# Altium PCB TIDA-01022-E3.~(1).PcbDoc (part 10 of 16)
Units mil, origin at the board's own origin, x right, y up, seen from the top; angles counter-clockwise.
Board outline 6929.13 x 11614.17 mil, 12 copper layers (L1_Top Layer, L2_GND, L3_GND, L4_Signal Layer 1, L5_GND, L6_PWR, L7_GND/PWR, L8_PWR, L9_GND/PWR, L10_Signal Layer 2, L11_GND, L12_Bottom Layer), stack 64.6 mil thick; 1733 components, 993 nets, 5987 pads, 3555 vias.

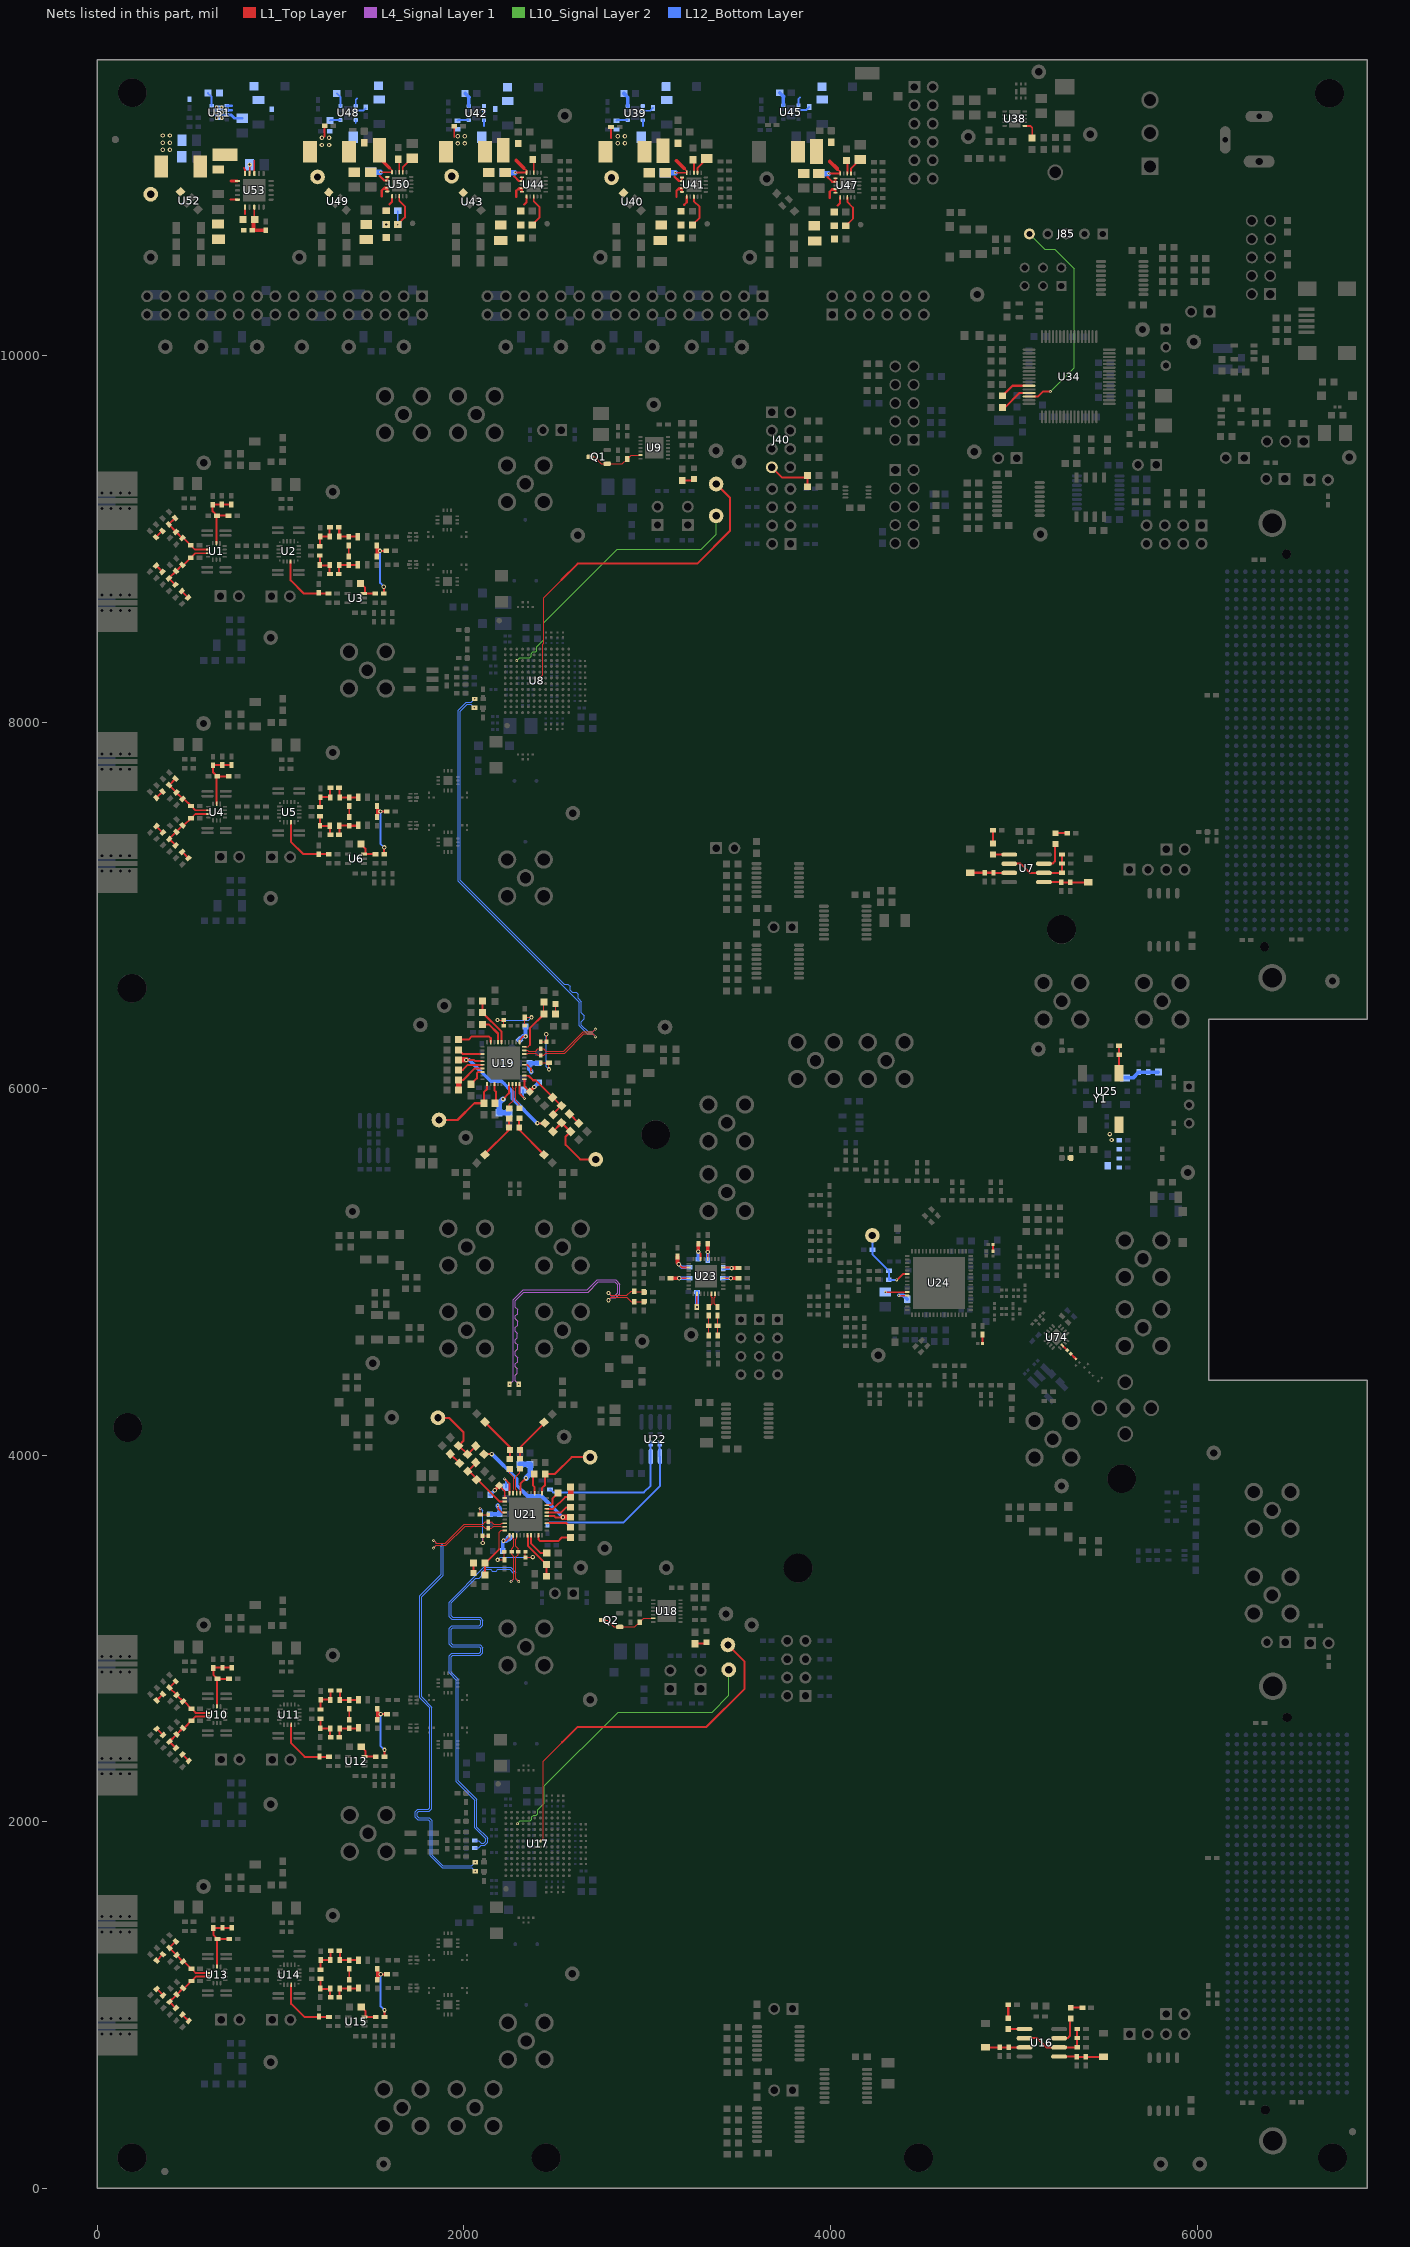
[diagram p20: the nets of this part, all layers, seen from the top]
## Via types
v1: diameter 16, hole 8, L1_Top Layer to L12_Bottom Layer, tented both sides, 1686 vias
v2: diameter 24, hole 12, L1_Top Layer to L12_Bottom Layer, tented both sides, 1590 vias
v3: diameter 20, hole 10, L1_Top Layer to L12_Bottom Layer, 279 vias

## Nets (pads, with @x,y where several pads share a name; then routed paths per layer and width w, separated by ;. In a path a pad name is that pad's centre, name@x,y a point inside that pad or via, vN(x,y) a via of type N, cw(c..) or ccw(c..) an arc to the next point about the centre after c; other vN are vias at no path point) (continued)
LMX2_CLKM: C253.2 R209.1 U21.22 | length 2893.9
  L1_Top Layer w6: v1(2256.84,3310.39) 2272.34,3325.89 2272.34,3446.04 2259.8,3458.58 R209.1@2259.8,3474.42 2259.8,3490.27 2272.2,3502.67 2272.2,3541.83 2267.86,3546.17 U21.22@2267.86,3563.98
  L12_Bottom Layer w6: C253.2@2058.74,1857.6 2080.49,1857.6 2094.99,1872.1 2112.65,1872.1 2125.78,1885.22 2129,1888.44 2129,1911.56 2125.78,1914.78 2069,1971.56 2069,2123.56 1969,2223.56 1969,2778 1930,2817 1930,2900.22 1938.28,2908.5 2088.28,2908.5 2103,2923.22 2103,2950.78 2088.28,2965.5 1938.28,2965.5 1930,2973.78 1930,3050.22 1938.28,3058.5 2088.28,3058.5 2103,3073.22 2103,3100.78 2088.28,3115.5 1938.28,3115.5 1930,3123.78 1930,3194 2019.93,3283.93 2053.16,3317.16 ; v1(2256.84,3310.39) 2272.34,3325.89 2272.34,3354.66 2250,3377 2184,3377 2175,3368 2154,3368 2145,3377 2113,3377 2097,3361 2097,3342 2083.47,3328.47 2064.47,3328.47 ; 2053.16,3317.16 2064.47,3328.47 ; 2053.16,3317.16 2064.47,3328.47
LMX2_CLKP: C252.2 R205.1 U21.23 | length 2877.7
  L1_Top Layer w6: U21.23@2287.55,3563.98 2287.55,3546.17 2283.2,3541.83 2283.2,3502.63 2295.89,3489.95 R205.1@2295.89,3474.1 2295.89,3458.26 2283.34,3445.72 2283.34,3325.89 v1(2298.84,3310.39)
  L12_Bottom Layer w6: C252.2@2058.74,1897.6 2080.49,1897.6 2094.99,1883.1 2108.1,1883.1 2118,1893 2118,1907 2058,1967 2058,2119 1958,2219 1958,2773.44 1919,2812.44 1919,2904.78 1933.72,2919.5 2083.72,2919.5 2092,2927.78 2092,2946.22 2083.72,2954.5 1933.72,2954.5 1919,2969.22 1919,3054.78 1933.72,3069.5 2083.72,3069.5 2092,3077.78 2092,3096.22 2083.72,3104.5 1933.72,3104.5 1919,3119.22 1919,3198.56 2108.44,3388 2254.56,3388 2283.34,3359.21 2283.34,3325.89 v1(2298.84,3310.39)
LMX2_CS: R454.1 U34.45 | length 180.5
  L1_Top Layer w11: R454.1@4935.38,9722.97 R454.1@4937.81,9722.97 ; R454.1@4937.81,9717 4951.96,9717 5030.35,9795.39 U34.45@5083.38,9795.39
LMX2_REFN: R244.1 R264.2 R265.1 R268.2 | length 1443.8
  L1_Top Layer w6: v2(2788.59,4845.83) 2803.54,4860.79 2888.31,4860.79 2911.19,4837.91 2929,4837.91 2929.5,4837.41 2930,4836.91 R265.1@2980,4836.91
  L4_Signal Layer 1 w4.9: v1(2248.66,4387.84) 2268.16,4407.34 2268.16,4848.13 2322.03,4902 2672.03,4902 2728.03,4958 2827,4958 2851,4934 2851,4881.61 2828.72,4859.33 2802.09,4859.33 v2(2788.59,4845.83)
LMX2_REFP: R226.2 R260.1 R262.2 R269.2 | length 1443.9
  L1_Top Layer w6: v2(2788.59,4884.83) 2801.63,4871.79 2888.31,4871.79 2911.19,4894.67 R269.2@2929,4894.67 2933,4890.67 R260.1@2981,4890.67
  L4_Signal Layer 1 w4.9: v1(2299.16,4387.35) 2280.16,4406.34 2280.16,4436 2291.16,4447 2291.16,4471 2280.16,4482 2280.16,4498 2292.16,4510 2292.16,4533 2280.16,4545 2280.16,4568 2292.16,4580 2292.16,4603 2280.16,4615 2280.16,4631 2291.16,4642 2291.16,4666 2280.16,4677 2280.16,4697 2292.16,4709 2292.16,4732 2280.16,4744 2280.16,4761 2292.16,4773 2292.16,4796 2280.16,4808 2280.16,4843.16 2327,4890 2677,4890 2733,4946 2822.03,4946 2839,4929.03 2839,4886.58 2823.75,4871.33 2802.09,4871.33 v2(2788.59,4884.83)
LMX2_SYNC: R219.2 R234.1 U22.7 | length 800.8
  L12_Bottom Layer w11: R219.2@2469.93,3813.45 2486.22,3797.16 2981.46,3797.16 3018.8,3834.5 U22.7@3018.8,3992.97 R234.1@3018.8,4064.21
LMX2_SYSREFREQ: R225.2 R239.2 U22.6 | length 934.1
  L12_Bottom Layer w11: R225.2@2455.3,3621.08 2467.49,3633.26 2870.96,3633.26 3068.8,3831.1 U22.6@3068.8,3992.97 3067.83,3993.94 R239.2@3067.83,4064.32
LMX_ADC1_SYSREF_M: C325.1 R180.1 U19.19 | length 2672
  L1_Top Layer w6: U19.19@2329.03,6208.71 2346.84,6208.71 2351.18,6204.37 2390.38,6204.37 2403.07,6217.06 R180.1@2418.91,6217.06 2434.75,6217.06 2447.3,6204.51 2545.3,6204.51 2650.1,6309.32 2701.66,6309.32 v1(2717.16,6324.82)
  L12_Bottom Layer w6: v1(2056.89,8077.19) 2037.89,8096.19 2017,8096.19 1979.97,8059.16 1979.97,7136.03 2545.93,6570.07 2567.14,6570.07 2579.16,6558.05 2579.16,6536.84 2590.47,6525.53 2611.69,6525.53 2623,6514.21 2623,6493 2641,6475 2641,6413 2656,6398 2656,6381 2641,6366 2641,6346.56 2678.24,6309.32 2701.66,6309.32 v1(2717.16,6324.82)
LMX_ADC1_SYSREF_P: C321.1 R175.2 U19.18 | length 2672.5
  L1_Top Layer w6: U19.18@2329.03,6189.03 2346.84,6189.03 2351.18,6193.37 2390.35,6193.37 2402.75,6180.97 R175.2@2418.59,6180.97 2434.43,6180.97 2443.76,6190.29 2446.98,6193.51 2549.85,6193.51 2654.66,6298.32 2701.66,6298.32 v1(2717.16,6282.82)
  L12_Bottom Layer w6: v1(2058.26,8126.19) 2039.26,8107.19 2012.44,8107.19 1968.97,8063.71 1968.97,7131.48 2630,6470.44 2630,6342 2673.68,6298.32 2701.66,6298.32 v1(2717.16,6282.82)
LMX_ADC2_SYSREF_M: C341.1 R221.1 U21.19 | length 2673.7
  L1_Top Layer w6: v1(1834.46,3493.16) 1849.96,3508.66 1901.51,3508.66 2006.32,3613.46 2104.32,3613.46 2116.86,3600.92 R221.1@2132.7,3600.92 2148.55,3600.92 2161.23,3613.6 2200.43,3613.6 2204.77,3609.26 U21.19@2222.59,3609.26
  L12_Bottom Layer w6: v1(1834.46,3493.16) 1849.96,3508.66 1868.34,3508.66 1875.67,3501.33 1875.67,3350.22 1758,3232.56 1758,2677.44 1814,2621.44 1814,2076.78 1805.72,2068.5 1748.72,2068.5 1734,2053.78 1734,2026.22 1748.72,2011.5 1805.72,2011.5 1814,2003.22 1814,1816.44 1819,1811.44 1880.25,1750.19 2042.59,1750.19 v1(2061.59,1731.19)
LMX_ADC2_SYSREF_P: C334.1 R216.2 U21.18 | length 2673.5
  L1_Top Layer w6: v1(1834.46,3535.16) 1849.96,3519.66 1896.96,3519.66 2001.76,3624.46 2104.64,3624.46 2107.86,3627.68 2117.18,3637.01 R216.2@2133.02,3637.01 2148.87,3637.01 2161.27,3624.6 2200.43,3624.6 2204.77,3628.95 U21.18@2222.59,3628.95
  L12_Bottom Layer w6: v1(1834.46,3535.16) 1849.96,3519.66 1872.9,3519.66 1886.67,3505.89 1886.67,3345.67 1769,3228 1769,2682 1825,2626 1825,2072.22 1810.28,2057.5 1753.28,2057.5 1745,2049.22 1745,2030.78 1753.28,2022.5 1810.28,2022.5 1825,2007.78 1825,1821 1884.81,1761.19 2042.59,1761.19 v1(2061.59,1780.19)
LMX_CS_1X: J85.5 U34.46 | length 1175.5
  L1_Top Layer w11: U34.46@5083.38,9775.7 5130.7,9775.7 5158,9803 v1(5199,9803)
  L10_Signal Layer 2 w6.5: J85.5@5085,10663 5168,10580 5224,10580 5330,10474 5330,9934 v1(5199,9803)
LMX_OSCIN1+: C348.2 U19.8 | length 144.6
  L1_Top Layer w6: C348.2@2246.86,5891.78 2246.86,5913.52 2268.41,5935.08 2268.41,6003.49 2264.07,6007.83 U19.8@2264.07,6025.64
LMX_OSCIN1-: C349.2 U19.9 | length 143.3
  L1_Top Layer w6: U19.9@2283.76,6025.64 2283.76,6007.83 2279.41,6003.49 2279.41,5937.85 2302.04,5915.22 C349.2@2302.04,5893.48
LMX_OSCIN2+: C378.2 U21.8 | length 144.6
  L1_Top Layer w6: U21.8@2287.55,3792.33 2287.55,3810.14 2283.2,3814.48 2283.2,3882.9 2304.76,3904.45 C378.2@2304.76,3926.2
LMX_OSCIN2-: C379.2 U21.9 | length 143.3
  L1_Top Layer w6: C379.2@2249.58,3924.5 2249.58,3902.75 2272.2,3880.13 2272.2,3814.48 2267.86,3810.14 U21.9@2267.86,3792.33
LMX_SDO: R449.1 U34.43 | length 168.3
  L1_Top Layer w11: R449.1@4937.81,9780 4992.57,9834.76 U34.43@5083.38,9834.76
LMX_SDO_MSEL: J40.7 R406.2 R408.2 | length 284.7
  L1_Top Layer w11: J40.7@3679.92,9390 3735.92,9334 3862.5,9334 R406.2@3874.5,9346 R408.2@3874.5,9284
MUXOUT1: R187.1 R190.2 U19.20 | length 300.5
  L1_Top Layer w6: U19.20@2329.03,6228.4 2349.5,6228.4 2359.81,6238.72 ; R187.1@2435.81,6472.22 2436.32,6471.72 R190.2@2436.32,6406.72
  L1_Top Layer w11: 2359.81,6238.72 2359.81,6330.21 R190.2@2436.32,6406.72
MUXOUT2: R227.1 R231.2 U21.20 | length 300.5
  L1_Top Layer w6: R227.1@2115.3,3346.26 R227.1@2115.8,3345.75 ; 2191.8,3487.76 2191.8,3579.26 2202.12,3589.58 U21.20@2222.59,3589.58
  L1_Top Layer w11: R227.1@2115.3,3346.26 R231.2@2115.3,3411.26 2191.8,3487.76
NetBG1_1: BG1.1 U8.C3 | length 1548.3
  L10_Signal Layer 2 w3.5: v1(2287.93,8335.33) 2304.6,8352 ; 2304.68,8352.08 2304.6,8352 ; 2434.67,8459.17 2434.67,8448 2397.92,8411.24 2397.92,8389.24 2391,8382.33 2376,8382.33 2366.92,8373.25 2366.92,8360.24 2358.67,8352 2304.6,8352
  L10_Signal Layer 2 w6.5: 2434.67,8459.17 2434.67,8542 2836,8943.33 3293.33,8943.33 3375.44,9025.44 BG1.1@3375.44,9124.69
NetBG2_1: BG2.1 U17.C3 | length 1659.3
  L10_Signal Layer 2 w3.5: v1(2291.26,1989.33) 2307.93,2006 ; 2308.01,2006.08 2307.93,2006 ; 2438,2113.17 2438,2102 2401.25,2065.25 2401.25,2043.25 2394.33,2036.33 2379.33,2036.33 2370.25,2027.25 2370.25,2014.25 2362,2006 2307.93,2006
  L10_Signal Layer 2 w6.5: 2438,2113.17 2438,2196 2840.75,2598.75 2850.8,2598.75 2851.05,2599 3353.77,2599 3444.77,2690 BG2.1@3444.77,2829.93
NetC1_1: C1.1 R1.1 R2.1 R3.2 R483.2 U1.2 | length 385.5
  L1_Top Layer w8: C1.1@648.91,9122.87 C1.1@652.03,9125.99
  L1_Top Layer w11: U1.2@648.91,8976.27 C1.1@648.91,9122.87 ; R2.1@715.29,9125.99 C1.1@652.03,9125.99 628.91,9149.11 R3.2@628.91,9185.99 630.29,9187.37 R483.2@678.91,9187.37 729.71,9187.37 R1.1@729.91,9187.16
NetC10_1: C10.1 C513.2 L1.1 R11.1 | length 157.9
  L1_Top Layer w11: R11.1@1213.24,8959 1213.24,9010.62 C10.1@1215,9012.38 L1.1@1266.33,9012.38 ; L1.1@1267.3,9011.41 1267.3,9060.92 C513.2@1269.38,9063
NetC11_1: C11.1 C513.1 L1.2 L2.1 | length 154.8
  L1_Top Layer w11: C513.1@1316.62,9063 1319.46,9060.16 L1.2@1319.46,9011.41 1371.01,9011.41 C11.1@1371.38,9011.05 1420.81,9011.05 L2.1@1421.18,9011.41
NetC11_2: C11.2 C16.2 | length 60.2
  L1_Top Layer w9: C16.2@1371.38,8903.65 C11.2@1371.38,8963.8
NetC12_1: C12.1 R7.1 R17.1 R22.2 | length 415.6
  L1_Top Layer w11: R17.1@1523.38,8903.65 R17.1@1523.38,8913.19 ; R7.1@1523.38,8949.76 R17.1@1523.38,8913.19 ; R7.1@1523.38,8963.8 1523.38,8952.62 1531,8945 ; v2@1539.14,8934 v2(1542,8934) ; R22.2@1562.71,8701.26 v2(1562.71,8738.45) ; C12.1@1576.38,8934 v2(1542,8934) ; R17.1@1523.38,8913.19 1531.34,8921.15 ; 1531,8945 v2(1542,8934) ; 1531,8945 1531,8921.49 1531.34,8921.15 ; 1531.34,8921.15 1543.09,8932.91 v2(1542,8934)
  L12_Bottom Layer w11: v2(1542,8934) 1542,8759.17 v2(1562.71,8738.45)
NetC13_2: C13.2 R20.2 | length 49.5
  L1_Top Layer w11: R20.2@319.21,9008.27 C13.2@354.21,9043.27
NetC14_2: C14.2 R21.2 | length 49.5
  L1_Top Layer w11: R21.2@320,8854 C14.2@355,8819
NetC15_1: C15.1 C514.2 L3.1 R15.1 | length 158.2
  L1_Top Layer w11: R15.1@1213.24,8909 1213.24,8854.87 1213,8854.62 1264.49,8854.62 L3.1@1266.3,8856.43 1266.3,8811.08 C514.2@1269.38,8808
NetC16_1: C16.1 C514.1 L3.2 L4.1 | length 153
  L1_Top Layer w11: C514.1@1316.62,8808 1318.46,8809.84 L3.2@1318.46,8856.43 C16.1@1371.38,8856.4 ; C16.1@1371.38,8856.4 1418.56,8856.4 L4.1@1421.18,8859.02
NetC26_2: C26.2 R22.1 U3.3 | length 129
  L1_Top Layer w11: C26.2@1435.59,8756.26 1460.19,8731.65 1460.19,8706.85 U3.3@1465.19,8701.85 ; U3.3@1453.38,8701.85 U3.3@1465.19,8701.85 ; R22.1@1515.47,8701.26 1514.88,8701.85 U3.3@1465.19,8701.85
NetC27_1: C27.1 R23.2 U2.7 | length 339.4
  L1_Top Layer w11: U2.7@1053.93,8876.14 1053.93,8773 1125.68,8701.26 R23.2@1260.47,8701.26
NetC35_1: C35.1 R25.1 R26.1 R27.2 R559.2 U4.2 | length 385.5
  L1_Top Layer w8: C35.1@650.71,7700.74 C35.1@653.83,7703.86
  L1_Top Layer w11: U4.2@650.71,7554.14 C35.1@650.71,7700.74 ; R26.1@717.09,7703.86 C35.1@653.83,7703.86 630.71,7726.98 R27.2@630.71,7763.86 632.09,7765.24 731.5,7765.24 R25.1@731.71,7765.04
NetC44_1: C44.1 C515.2 L5.1 R35.1 | length 157.9
  L1_Top Layer w11: R35.1@1215.04,7536.87 1215.04,7588.49 C44.1@1216.8,7590.25 L5.1@1268.13,7590.25 ; L5.1@1269.09,7589.29 1269.09,7638.79 C515.2@1271.18,7640.87
NetC45_1: C45.1 C515.1 L5.2 L6.1 | length 154.8
  L1_Top Layer w11: C515.1@1318.42,7640.87 1321.26,7638.03 L5.2@1321.26,7589.29 1372.81,7589.29 C45.1@1373.18,7588.92 1422.61,7588.92 L6.1@1422.98,7589.29
NetC45_2: C45.2 C50.2 | length 60.2
  L1_Top Layer w9: C50.2@1373.18,7481.52 C45.2@1373.18,7541.68
NetC46_1: C46.1 R31.1 R41.1 R46.2 | length 415.6
  L1_Top Layer w11: R41.1@1525.18,7481.52 R41.1@1525.18,7491.07 ; R31.1@1525.18,7527.63 R41.1@1525.18,7491.07 ; R31.1@1525.18,7541.68 1525.18,7530.49 1532.8,7522.87 ; v2@1540.94,7511.87 v2(1543.8,7511.87) ; R46.2@1564.51,7279.13 v2(1564.51,7316.32) ; C46.1@1578.18,7511.87 v2(1543.8,7511.87) ; R41.1@1525.18,7491.07 1533.13,7499.02 ; 1532.8,7522.87 v2(1543.8,7511.87) ; 1532.8,7522.87 1532.8,7499.36 1533.13,7499.02 ; 1533.13,7499.02 1544.89,7510.78 v2(1543.8,7511.87)
  L12_Bottom Layer w11: v2(1543.8,7511.87) 1543.8,7337.04 v2(1564.51,7316.32)
NetC47_2: C47.2 R44.2 | length 49.5
  L1_Top Layer w11: R44.2@321.01,7586.14 C47.2@356.01,7621.14
NetC48_2: C48.2 R45.2 | length 49.5
  L1_Top Layer w11: R45.2@321.8,7431.87 C48.2@356.8,7396.87
NetC49_1: C49.1 C520.2 L7.1 R39.1 | length 158.2
  L1_Top Layer w11: R39.1@1215.04,7486.87 1215.04,7432.74 1214.8,7432.49 1266.28,7432.49 L7.1@1268.09,7434.3 1268.09,7388.96 C520.2@1271.18,7385.87
NetC50_1: C50.1 C520.1 L7.2 L8.1 | length 153
  L1_Top Layer w11: C520.1@1318.42,7385.87 1320.26,7387.71 L7.2@1320.26,7434.3 C50.1@1373.18,7434.28 ; C50.1@1373.18,7434.28 1420.36,7434.28 L8.1@1422.98,7436.9
NetC60_2: C60.2 R46.1 U6.3 | length 129
  L1_Top Layer w11: C60.2@1437.39,7334.13 1461.99,7309.52 1461.99,7284.72 U6.3@1466.99,7279.72 ; U6.3@1455.18,7279.72 U6.3@1466.99,7279.72 ; R46.1@1517.27,7279.13 1516.68,7279.72 U6.3@1466.99,7279.72
NetC61_1: C61.1 R47.2 U5.7 | length 341.2
  L1_Top Layer w11: U5.7@1055.73,7454.01 1055.73,7347.87 1124.47,7279.13 C61.1@1208.47,7279.13 R47.2@1262.27,7279.13
NetC74_2: C74.2 D2.1 R51.2 U7.3 | length 211.9
  L1_Top Layer w11: D2.1@4763.11,7177.81 R51.2@4840.21,7177.81 C74.2@4889.21,7177.81 4889.83,7177.18 U7.3@4974.72,7177.18
NetC82_2: C82.2 R49.1 R60.2 U7.2 U7.6 | length 408
  L1_Top Layer w11: U7.2@4974.72,7227.18 5036.99,7227.18 5086.99,7177.18 U7.6@5163.7,7177.18 5261.59,7177.18 C82.2@5262.59,7178.18 R60.2@5262.59,7228.18 R49.1@5262.59,7277.18
NetC83_2: C83.2 D4.1 R62.2 U7.5 | length 243.1
  L1_Top Layer w11: U7.5@5163.7,7127.18 5257.83,7127.18 C83.2@5259.21,7125.81 R62.2@5308.21,7125.81 5406.12,7125.81 D4.1@5406.21,7125.72
NetC117_1: C117.1 Q1.1 Q1.3 U9.6 | length 311.5
  L1_Top Layer w6: Q1.3@2686.86,9446.65 2712.14,9446.65 2749.54,9409.25 Q1.1@2781.35,9409.25 2864.32,9409.25 C117.1@2890.1,9435.03 2911.29,9456.21 U9.6@2963.36,9456.21
NetC161_1: C161.1 R82.1 R83.1 R84.2 R568.2 U10.2 | length 385.5
  L1_Top Layer w8: C161.1@652.23,2776.51 C161.1@655.35,2779.63
  L1_Top Layer w11: U10.2@652.23,2629.9 C161.1@652.23,2776.51 ; R83.1@718.61,2779.63 C161.1@655.35,2779.63 632.23,2802.75 R84.2@632.23,2839.63 633.61,2841.01 733.02,2841.01 R82.1@733.23,2840.8
NetC170_1: C170.1 C521.2 L9.1 R92.1 | length 157.9
  L1_Top Layer w11: R92.1@1216.56,2612.64 1216.56,2664.26 C170.1@1218.32,2666.02 L9.1@1269.65,2666.02 ; L9.1@1270.61,2665.05 1270.61,2714.56 C521.2@1272.69,2716.64
NetC171_1: C171.1 C521.1 L9.2 L10.1 | length 154.8
  L1_Top Layer w11: C521.1@1319.94,2716.64 1322.78,2713.8 L9.2@1322.78,2665.05 1374.33,2665.05 C171.1@1374.69,2664.68 1424.13,2664.68 L10.1@1424.5,2665.05
NetC171_2: C171.2 C176.2 | length 60.2
  L1_Top Layer w9: C176.2@1374.69,2557.28 C171.2@1374.69,2617.44
NetC172_1: C172.1 R88.1 R98.1 R103.2 | length 415.6
  L1_Top Layer w11: R98.1@1526.69,2557.28 R98.1@1526.69,2566.83 ; R88.1@1526.69,2603.4 R98.1@1526.69,2566.83 ; R88.1@1526.69,2617.44 1526.69,2606.26 1534.32,2598.64 ; v2@1542.45,2587.64 v2(1545.32,2587.64) ; R103.2@1566.03,2354.9 v2(1566.03,2392.09) ; C172.1@1579.69,2587.64 v2(1545.32,2587.64) ; R98.1@1526.69,2566.83 1534.65,2574.79 ; 1534.32,2598.64 v2(1545.32,2587.64) ; 1534.32,2598.64 1534.32,2575.13 1534.65,2574.79 ; 1534.65,2574.79 1546.41,2586.55 v2(1545.32,2587.64)
  L12_Bottom Layer w11: v2(1545.32,2587.64) 1545.32,2412.8 v2(1566.03,2392.09)
NetC173_2: C173.2 R101.2 | length 49.5
  L1_Top Layer w11: R101.2@322.52,2661.9 C173.2@357.52,2696.9
NetC174_2: C174.2 R102.2 | length 49.5
  L1_Top Layer w11: R102.2@323.32,2507.64 C174.2@358.32,2472.64
NetC175_1: C175.1 C525.2 L11.1 R96.1 | length 158.2
  L1_Top Layer w11: R96.1@1216.56,2562.64 1216.56,2508.5 1216.32,2508.26 1267.8,2508.26 L11.1@1269.61,2510.07 1269.61,2464.72 C525.2@1272.69,2461.64
NetC176_1: C176.1 C525.1 L11.2 L12.1 | length 153
  L1_Top Layer w11: C525.1@1319.94,2461.64 1321.78,2463.48 L11.2@1321.78,2510.07 C176.1@1374.67,2510.07 ; C176.1@1374.69,2510.04 1421.88,2510.04 L12.1@1424.5,2512.66
NetC186_2: C186.2 R103.1 U12.3 | length 129
  L1_Top Layer w11: C186.2@1438.9,2409.9 1463.51,2385.29 1463.51,2360.49 U12.3@1468.51,2355.49 ; U12.3@1456.7,2355.49 U12.3@1468.51,2355.49 ; R103.1@1518.79,2354.9 1518.2,2355.49 U12.3@1468.51,2355.49
NetC187_1: C187.1 R104.2 U11.7 | length 338.2
  L1_Top Layer w11: U11.7@1057.25,2529.78 1057.25,2428.68 1131.04,2354.9 R104.2@1263.79,2354.9
NetC195_1: C195.1 R106.1 R107.1 R108.2 R577.2 U13.2 | length 385.5
  L1_Top Layer w8: C195.1@652.3,1357.17 C195.1@655.42,1360.29
  L1_Top Layer w11: U13.2@652.3,1210.57 C195.1@652.3,1357.17 ; R107.1@718.68,1360.29 C195.1@655.42,1360.29 632.3,1383.41 R108.2@632.3,1420.29 633.68,1421.67 733.1,1421.67 R106.1@733.3,1421.47
NetC204_1: C204.1 C526.2 L13.1 R116.1 | length 157.9
  L1_Top Layer w11: R116.1@1216.64,1193.3 1216.64,1244.92 C204.1@1218.39,1246.68 L13.1@1269.72,1246.68 ; L13.1@1270.69,1245.72 1270.69,1295.22 C526.2@1272.77,1297.3
NetC205_1: C205.1 C526.1 L13.2 L14.1 | length 154.8
  L1_Top Layer w11: C526.1@1320.01,1297.3 1322.85,1294.46 L13.2@1322.85,1245.72 1374.4,1245.72 C205.1@1374.77,1245.35 1424.21,1245.35 L14.1@1424.57,1245.72
NetC205_2: C205.2 C210.2 | length 60.2
  L1_Top Layer w9: C210.2@1374.77,1137.95 C205.2@1374.77,1198.1
NetC206_1: C206.1 R112.1 R122.1 R127.2 | length 415.6
  L1_Top Layer w11: R122.1@1526.77,1137.95 R122.1@1526.77,1147.5 ; R112.1@1526.77,1184.06 R122.1@1526.77,1147.5 ; R112.1@1526.77,1198.1 1526.77,1186.92 1534.39,1179.3 ; v2@1542.53,1168.3 v2(1545.39,1168.3) ; R127.2@1566.11,935.56 v2(1566.11,972.75) ; C206.1@1579.77,1168.3 v2(1545.39,1168.3) ; R122.1@1526.77,1147.5 1534.73,1155.45 ; 1534.39,1179.3 v2(1545.39,1168.3) ; 1534.39,1179.3 1534.39,1155.79 1534.73,1155.45 ; 1534.73,1155.45 1546.48,1167.21 v2(1545.39,1168.3)
  L12_Bottom Layer w11: v2(1545.39,1168.3) 1545.39,993.47 v2(1566.11,972.75)
NetC207_2: C207.2 R125.2 | length 49.5
  L1_Top Layer w11: R125.2@322.6,1242.57 C207.2@357.6,1277.57
NetC208_2: C208.2 R126.2 | length 49.5
  L1_Top Layer w11: R126.2@323.39,1088.3 C208.2@358.39,1053.3
NetC209_1: C209.1 C527.2 L15.1 R120.1 | length 158.2
  L1_Top Layer w11: R120.1@1216.64,1143.3 1216.64,1089.17 1216.39,1088.92 1267.88,1088.92 L15.1@1269.69,1090.73 1269.69,1045.39 C527.2@1272.77,1042.3
NetC210_1: C210.1 C527.1 L15.2 L16.1 | length 153
  L1_Top Layer w11: C527.1@1320.01,1042.3 1321.85,1044.14 L15.2@1321.85,1090.73 C210.1@1374.77,1090.7 ; C210.1@1374.77,1090.7 1421.95,1090.7 L16.1@1424.57,1093.33
NetC220_2: C220.2 R127.1 U15.3 | length 129
  L1_Top Layer w11: C220.2@1438.98,990.56 1463.59,965.95 1463.59,941.15 U15.3@1468.59,936.15 ; U15.3@1456.78,936.15 U15.3@1468.59,936.15 ; R127.1@1518.86,935.56 1518.27,936.15 U15.3@1468.59,936.15
NetC221_1: C221.1 R128.2 U14.7 | length 339.4
  L1_Top Layer w11: U14.7@1057.33,1110.44 1057.33,1007.35 1129.11,935.56 R128.2@1263.86,935.56
NetC234_2: C234.2 D7.1 R132.2 U16.3 | length 213.2
  L1_Top Layer w11: D7.1@4845.28,770.78 4846.19,769.87 R132.2@4923.3,769.87 C234.2@4972.3,769.87 4972.92,769.25 U16.3@5057.81,769.25
NetC242_2: C242.2 R130.1 R141.2 U16.2 U16.6 | length 408
  L1_Top Layer w11: U16.2@5057.81,819.25 5127.31,819.25 5177.31,769.25 U16.6@5246.78,769.25 5344.67,769.25 C242.2@5345.67,770.25 R130.1@5345.67,869.25
NetC243_2: C243.2 D9.1 R143.2 U16.5 | length 243.1
  L1_Top Layer w11: U16.5@5246.78,719.25 5340.92,719.25 C243.2@5342.3,717.87 R143.2@5391.3,717.87 5489.21,717.87 D9.1@5489.3,717.79
NetC277_1: C277.1 Q2.1 Q2.3 U18.6 | length 311.5
  L1_Top Layer w6: Q2.3@2755.19,3100.88 2780.47,3100.88 2817.87,3063.48 Q2.1@2849.68,3063.48 2932.65,3063.48 C277.1@2958.43,3089.26 2979.62,3110.45 U18.6@3031.69,3110.45
NetC307_1: C307.1 R401.2 | length 40.5
  L1_Top Layer w11: C307.1@5310.19,4553.81 R401.2@5338.81,4525.19
NetC307_2: C307.2 U74.2 | length 38.2
  L1_Top Layer w11: U74.2@5264.65,4598.78 5291.24,4572.19 C307.2@5291.81,4572.19
NetC322_2: C322.2 L17.2 R164.2 R168.2 | length 339
  L1_Top Layer w6: v2(2182.77,6374.32) 2214.22,6374.32 2214.77,6373.77 L17.2@2216.07,6375.07 2216.36,6374.78 R164.2@2216.36,6343.87 ; R168.2@2331.19,6343.55 2331.07,6343.67 C322.2@2331.07,6388.15 2367.45,6388.15 v2(2368.07,6388.77)
  L12_Bottom Layer w6: v2(2182.77,6374.32) 2352.52,6374.32 2353.07,6373.77 v2(2368.07,6388.77)
NetC323_2: C323.2 R165.2 U19.7 | length 233.3
  L1_Top Layer w11: v2(2213.28,5942.92) 2244.39,5974.02 U19.7@2244.39,6025.64
  L12_Bottom Layer w30: C323.2@2191.16,5868.21 2191.16,5920.79 v2(2213.28,5942.92) ; C323.2@2191.25,5868.3 R165.2@2245.1,5868.3
NetC324_2: C324.2 R167.2 U19.11 | length 159.7
  L1_Top Layer w11: U19.11@2329.03,6051.23 2329.03,6013.34 C324.2@2365.07,5977.3
  L1_Top Layer w20: C324.2@2358.61,5983.87 v2(2383.73,6008.99)
  L12_Bottom Layer w20: v2(2383.73,6008.99) 2408.65,6033.92 R167.2@2408.72,6033.92
NetC326_1: C326.1 R170.2 U19.15 | length 169.1
  L1_Top Layer w9: U19.15@2329.03,6129.97 2345.56,6129.97 2365.25,6110.28 2365.25,6093.58 v1(2367.87,6090.96)
  L12_Bottom Layer w25: v1(2367.87,6090.96) 2367.87,6095.88 2357.12,6106.7 C326.1@2357.12,6138.82 2408.13,6138.82 R170.2@2408.8,6138.15
NetC327_2: C327.2 R169.2 U19.21 | length 146.8
  L1_Top Layer w10: U19.21@2303.44,6253.99 2303.44,6264.45 2323.8,6284.82 v2(2335.86,6284.82)
  L12_Bottom Layer w20: R169.2@2335.25,6338.72 2335.86,6338.11 v2(2335.86,6284.82)
  L12_Bottom Layer w25: C327.2@2302.55,6265.5 2321.86,6284.82 v2(2335.86,6284.82)
NetC332_2: C332.2 R171.1 U19.26 | length 266.7
  L1_Top Layer w11: R171.1@2101.43,6477.29 2100.78,6476.64 C332.2@2100.78,6414.92 2205.02,6310.68 U19.26@2205.02,6253.99
NetC333_2: C333.2 R173.1 U19.37 | length 211.9
  L1_Top Layer w11: C333.2@1970.15,6047.12 1995.57,6047.12 2058.74,6110.29 U19.37@2100.68,6110.29
  L1_Top Layer w30: R173.1@1970.15,5991.92 C333.2@1970.15,6047.12
NetC335_2: C335.2 R176.1 U19.35 | length 723.4
  L1_Top Layer w11: v2(2012.28,6156.42) 2053.52,6156.42 2060.28,6149.66 U19.35@2100.68,6149.66 ; v2@2401.02,5811.09 R176.1@2441.39,5811.09
  L1_Top Layer w30: C335.2@1970.15,6156.42 v2(2012.28,6156.42)
  L12_Bottom Layer w20: v2(2012.28,6156.42) 2029.11,6156.42 2145.52,6040.01 2205.72,6040.01 2264.21,5981.52 2264.21,5946.06 v2@2398.49,5811.78
  other v2: 2400.32,5811.78
NetC336_1: C336.1 R176.2 R177.2 Vtune_TP1.1 | length 391.6
  L1_Top Layer w11: R176.2@2485.93,5766.55 2531.93,5812.55 R177.2@2531.93,5813.45 2579.29,5766.09 C336.1@2581.39,5766.09 2554.28,5738.98 2554.28,5692.92 2633.38,5613.82 Vtune_TP1.1@2693.66,5613.82
NetC337_1: C337.1 C339.1 R177.1 U19.12 | length 327
  L1_Top Layer w8: U19.12@2329.03,6070.92 2351.7,6070.92 2354.66,6067.96
  L1_Top Layer w11: 2354.66,6067.96 2376.81,6045.81 2391.39,6045.81 C337.1@2524.28,5912.92 ; R177.1@2487.39,5862.09 C337.1@2531.39,5906.09
  L1_Top Layer w30: R177.1@2487.39,5857.99 R177.1@2487.39,5862.09
NetC337_2: C337.2 R179.1 | length 71.1
  L1_Top Layer w11: C337.2@2575.93,5861.55 R179.1@2626.01,5811.47
  L1_Top Layer w30: R179.1@2626.01,5811.19 R179.1@2626.01,5811.47
NetC338_2: C338.2 L18.2 R175.1 R180.2 | length 352
  L1_Top Layer w6: R175.1@2418.59,6141.6 2418.71,6141.72 C338.2@2463.19,6141.72 2463.19,6105.34 v2(2463.81,6104.72) ; R180.2@2418.91,6256.43 2449.82,6256.43 L18.2@2450.11,6256.72 2448.81,6258.02 v2(2448.81,6296.72)
  L12_Bottom Layer w6: v2(2448.81,6296.72) 2448.81,6119.72 v2(2463.81,6104.72)
NetC340_2: C340.2 U19.10 | length 138.8
  L1_Top Layer w11: U19.10@2303.44,6025.64 2303.44,5972.93 v1(2329.56,5946.82)
  L12_Bottom Layer w11: C340.2@2322,5992.83 2322,5954.37 v1(2329.56,5946.82)
NetC342_1: C342.1 U19.36 | length 142.1
  L1_Top Layer w11: C342.1@1970.15,6102.02 1993.38,6102.02 2021.34,6129.97 U19.36@2100.68,6129.97
NetC343_2: C343.2 U19.38 | length 105.8
  L1_Top Layer w11: C343.2@2038.16,6024.21 2069.86,6055.91 2069.86,6082.87 2077.59,6090.6 U19.38@2100.68,6090.6
NetC344_1: C344.1 U19.29 | length 208.8
  L1_Top Layer w11: C344.1@1970.15,6267.52 2024.82,6267.52 2042.83,6285.52 2130.44,6285.52 2130.55,6285.42 2135.78,6285.42 2145.96,6275.24 U19.29@2145.96,6253.99
NetC345_1: C345.1 U19.3 | length 116.7
  L1_Top Layer w11: C345.1@2165.65,5923.33 C345.1@2168.66,5920.31 2175.78,5927.43 2175.78,5981.75 2165.65,5991.88 U19.3@2165.64,6025.64
NetC346_2: C346.2 U19.27 | length 152.5
  L1_Top Layer w11: C346.2@2100.37,6350.82 2135.38,6350.82 2185.33,6300.87 U19.27@2185.33,6253.99
NetC347_2: C347.2 U19.33 | length 139.7
  L1_Top Layer w11: C347.2@1970.15,6211.12 1992.24,6189.03 U19.33@2100.68,6189.03
NetC348_1: C348.1 R192.2 R196.2 | length 252.3
  L1_Top Layer w11: R192.2@2111.13,5640.53 2111.91,5641.31 2246.86,5776.26 2246.86,5788.82 C348.1@2246.86,5836.66
NetC349_1: C349.1 R196.1 R199.1 | length 251.9
  L1_Top Layer w11: C349.1@2302.04,5838.36 2300.54,5836.86 2300.54,5775.26 R199.1@2433.59,5642.21
NetC352_2: C352.2 L19.2 R205.2 R209.2 | length 352
  L1_Top Layer w6: v2(2183.55,3429.2) 2184.17,3429.82 C352.2@2220.55,3429.82 2220.55,3474.3 R209.2@2220.43,3474.42 ; R205.2@2335.26,3474.1 2335.26,3443.19 L19.2@2335.55,3442.9 2336.85,3444.2 v2(2375.55,3444.2)
  L12_Bottom Layer w6: v2(2183.55,3429.2) 2198.55,3444.2 v2(2375.55,3444.2)
NetC353_2: C353.2 R206.2 U21.7 | length 233.3
  L1_Top Layer w11: U21.7@2307.23,3792.33 2307.23,3843.95 v2(2338.34,3875.06)
  L12_Bottom Layer w30: R206.2@2306.51,3949.67 C353.2@2360.37,3949.67 ; v2(2338.34,3875.06) 2360.46,3897.18 C353.2@2360.46,3949.76
NetC354_2: C354.2 R208.2 U21.11 | length 159.7
  L1_Top Layer w10: C354.2@2186.55,3840.67 2222.59,3804.63 U21.11@2222.59,3766.74
  L1_Top Layer w20: v2(2167.89,3808.98) C354.2@2193.01,3834.11
  L12_Bottom Layer w20: R208.2@2142.89,3784.06 2142.96,3784.06 v2(2167.89,3808.98)
NetC355_1: C355.1 C494.1 L87.1 U39.1 U39.2 | length 61.3
  L12_Bottom Layer w10: U39.2@2976,11335.45 3015.83,11335.45 C355.1@3031,11350.62
NetC356_1: C356.1 R211.2 U21.15 | length 167.3
  L1_Top Layer w9: v1(2184.09,3726.67) 2186.71,3724.04 2186.71,3707.35 2206.41,3687.65 U21.15@2222.93,3687.65
  L12_Bottom Layer w25: R211.2@2142.48,3677.57 C356.1@2193.49,3677.57 ; v1@2183.34,3723.16 v1@2183.74,3723.56 ; v1@2183.71,3722.06 2194.5,3711.27 C356.1@2194.5,3679.16 ; v1@2183.74,3722.09 v1@2183.74,3723.56 ; v1@2183.74,3725.59 v1@2183.74,3723.56
NetC357_2: C357.2 R210.2 U21.21 | length 145.9
  L1_Top Layer w10: v2(2215.76,3533.16) 2227.81,3533.16 2248.18,3553.52 U21.21@2248.18,3563.98
  L12_Bottom Layer w20: R210.2@2211.44,3477.61 v2@2211.44,3530.91
  L12_Bottom Layer w25: v2(2215.76,3533.16) 2229.76,3533.16 C357.2@2249.07,3552.47
NetC362_2: C362.2 R212.1 U21.26 | length 267.2
  L1_Top Layer w11: U21.26@2346.6,3563.98 2348.39,3562.19 2348.39,3505.51 C362.2@2450.84,3403.06 2450.9,3403 R212.1@2450.9,3339.98
NetC363_2: C363.2 R214.1 U21.37 | length 211.9
  L1_Top Layer w11: U21.37@2450.93,3707.69 2488.1,3707.69 2551.27,3770.86 C363.2@2581.46,3770.86
  L1_Top Layer w30: C363.2@2581.46,3770.86 R214.1@2581.46,3826.06
NetC364_1: C364.1 C537.1 L88.1 U42.1 U42.2
NetC365_2: C365.2 R218.1 U21.35 | length 723.4
  L1_Top Layer w11: R218.1@2110.23,4006.89 v2@2150.6,4006.89 ; U21.35@2450.93,3668.32 2491.34,3668.32 2498.09,3661.56 v2(2539.34,3661.56)
  L1_Top Layer w30: v2(2539.34,3661.56) C365.2@2581.46,3661.56
  L12_Bottom Layer w20: v2@2153.13,4006.19 2287.41,3871.91 2287.41,3836.45 2345.89,3777.97 2422.92,3777.97 v2(2539.34,3661.56)
  other v2: 2151.29,4006.19
NetC366_1: C366.1 R217.2 R218.2 Vtune_TP2.1 | length 391.6
  L1_Top Layer w11: Vtune_TP2.1@1857.96,4204.16 1918.24,4204.16 1997.34,4125.06 1997.34,4078.99 C366.1@1970.23,4051.89 1972.33,4051.89 2019.69,4004.53 R217.2@2019.69,4005.43 R218.2@2064.32,4050.07 R218.2@2065.69,4051.43
NetC367_1: C367.1 C369.1 R217.1 U21.12 | length 327
  L1_Top Layer w10: 2194.8,3747.06 U21.12@2222.59,3747.06
  L1_Top Layer w11: C367.1@2020.23,3911.89 R217.1@2064.23,3955.89 ; C367.1@2027.34,3905.06 2036.8,3905.06 2194.8,3747.06
  L1_Top Layer w30: R217.1@2064.23,3955.89 R217.1@2064.23,3959.99
NetC367_2: C367.2 R220.1 | length 71.1
  L1_Top Layer w11: R220.1@1925.61,4006.51 C367.2@1975.69,3956.43
  L1_Top Layer w30: R220.1@1925.61,4006.51 R220.1@1925.61,4006.79
NetC368_2: C368.2 L20.2 R216.1 R221.2 | length 352.4
  L1_Top Layer w6: v1(2088,3710) 2088,3712.21 2088.43,3712.64 C368.2@2088.43,3676.26 2132.91,3676.26 R216.1@2133.02,3676.38 ; v2(2102.8,3521.26) 2102.8,3559.96 2101.5,3561.26 L20.2@2101.79,3561.55 R221.2@2132.7,3561.55
  L12_Bottom Layer w6: v1(2088,3710) 2091.06,3710 2102.8,3698.26 v2(2102.8,3521.26)
NetC370_2: C370.2 U21.10 | length 138.8
  L1_Top Layer w10: v1(2222.06,3871.16) 2248.18,3845.04 U21.10@2248.18,3792.33
  L12_Bottom Layer w11: v1(2222.06,3871.16) 2229.61,3863.6 C370.2@2229.61,3825.15
NetC371_1: C371.1 C600.1 L89.1 U45.1 U45.2 | length 109.7
  L12_Bottom Layer w10: U45.1@3825.01,11365.18 3825.01,11399.26 3832.75,11407
  L12_Bottom Layer w12: U45.2@3825.01,11339.59 3866.96,11339.59 C371.1@3883,11355.62
NetC372_1: C372.1 U21.36 | length 142.1
  L1_Top Layer w11: U21.36@2450.93,3688 2530.28,3688 2558.24,3715.96 C372.1@2581.46,3715.96
NetC373_2: C373.2 U21.38 | length 105.8
  L1_Top Layer w11: U21.38@2450.93,3727.37 2474.03,3727.37 2481.76,3735.1 2481.76,3762.06 C373.2@2513.46,3793.76
NetC374_1: C374.1 U21.29 | length 209.5
  L1_Top Layer w11: U21.29@2405.66,3563.98 2405.66,3542.74 2416.86,3531.53 2513.13,3531.53 2532.06,3550.46 C374.1@2581.46,3550.46
NetC375_1: C375.1 U21.3 | length 116.7
  L1_Top Layer w11: U21.3@2385.97,3792.33 2385.97,3826.09 2375.84,3836.22 2375.84,3890.54 C375.1@2382.96,3897.66 C375.1@2385.97,3894.65
NetC376_2: C376.2 U21.27 | length 152.5
  L1_Top Layer w11: U21.27@2366.29,3563.98 2366.29,3517.11 2416.24,3467.16 C376.2@2451.25,3467.16
NetC377_2: C377.2 U21.33 | length 139.7
  L1_Top Layer w11: U21.33@2450.93,3628.95 2559.37,3628.95 C377.2@2581.46,3606.86
NetC378_1: C378.1 R233.2 R237.2 | length 252.3
  L1_Top Layer w11: C378.1@2304.76,3981.32 2304.76,4041.72 R233.2@2440.49,4177.45
NetC379_1: C379.1 R237.1 R242.1 | length 251.9
  L1_Top Layer w11: R242.1@2118.03,4175.77 2251.08,4042.72 2251.08,4029.16 2251.08,3981.12 C379.1@2249.58,3979.62
NetC384_1: C384.1 R245.1 U23.2 | length 171.9
  L1_Top Layer w10: v2(3172,5042) 3189.01,5024.99 U23.2@3225.8,5024.99
  L1_Top Layer w20: R245.1@3164.5,5084.17 3164.5,5049.5 v2(3172,5042)
  L12_Bottom Layer w20: v2(3172,5042) 3188.71,5025.29 C384.1@3230.88,5025.29
NetC385_2: C385.2 R251.1 U23.10 | length 154
  L1_Top Layer w8: v2(3270.5,4808.91) U23.10@3270.5,4880.71
  L12_Bottom Layer w20: v2(3270.5,4808.91) 3271.5,4809.91 C385.2@3271.5,4890.67
NetC386_1: C386.1 R246.1 U23.5 | length 155
  L1_Top Layer w10: v2(3174,4966) 3174.07,4965.93 U23.5@3225.8,4965.93
  L1_Top Layer w20: R246.1@3127.12,4965.79 3173.79,4965.79 v2(3174,4966)
  L12_Bottom Layer w20: v2(3174,4966) 3174.71,4965.29 C386.1@3229.88,4965.29
NetC387_2: C387.2 R250.1 U23.28 | length 129
  L1_Top Layer w10: v2(3330,5109) 3330.13,5108.87 U23.28@3330.13,5070.26
  L1_Top Layer w20: v2(3330,5109) 3330,5153.17 R250.1@3330.5,5153.67
  L12_Bottom Layer w20: v2(3330,5109) 3330.5,5108.5 C387.2@3330.5,5063.91
NetC388_1: C388.1 R247.1 U23.20 | length 128.4
  L1_Top Layer w10: U23.20@3414.78,4965.93 3455.93,4965.93 v2(3455.87,4966)
  L1_Top Layer w20: v2(3455.87,4966) 3497.59,4966 R247.1@3497.88,4966.29
  L12_Bottom Layer w20: C388.1@3411.12,4965.29 3455.15,4965.29 v2(3455.87,4966)
NetC389_1: C389.1 R248.1 U23.23 | length 130.1
  L1_Top Layer w10: U23.23@3414.78,5024.99 3456.01,5024.99 v2(3460,5021)
  L1_Top Layer w20: v2(3460,5021) 3460.29,5021.29 R248.1@3497.88,5021.29
  L12_Bottom Layer w20: C389.1@3414.78,5021.05 3414.83,5021 v2(3460,5021)
NetC390_1: C390.1 R249.1 U23.30 | length 130.1
  L1_Top Layer w10: v2(3278,5111) 3290.76,5098.24 U23.30@3290.76,5070.26
  L1_Top Layer w20: v2(3278,5111) 3278,5151.67 R249.1@3279.5,5153.17
  L12_Bottom Layer w20: v2(3278,5111) 3278.12,5110.88 C390.1@3278.12,5069.79
NetC391_1: C391.1 R263.2 R267.2 | length 109.1
  L1_Top Layer w6: R263.2@3335.5,4652.91 3335.5,4706.91 R267.2@3335.88,4707.29 3335.88,4761.29 C391.1@3335.5,4761.67
NetC391_2: C391.2 U23.14 | length 81.9
  L1_Top Layer w6: C391.2@3335.5,4808.91 3354.16,4827.57 3354.16,4859.13 3349.81,4863.48 U23.14@3349.81,4881.29
NetC392_1: C392.1 R267.1 R270.2 | length 109.5
  L1_Top Layer w6: C392.1@3383.5,4761.67 3383.12,4761.29 R267.1@3383.12,4707.29 3384.5,4705.91 R270.2@3384.5,4652.91
NetC392_2: C392.2 U23.15 | length 81.8
  L1_Top Layer w6: U23.15@3369.5,4881.29 3369.5,4863.48 3365.16,4859.13 3365.16,4827.25 C392.2@3383.5,4808.91
NetC393_2: C393.2 R275.2 | length 38
  L1_Top Layer w11: C393.2@4886.47,5112.93 R275.2@4886.46,5150.94
NetC398_1: C398.1 R284.2 | length 48.4
  L1_Top Layer w11: R284.2@4828.96,4610.02 C398.1@4828.97,4658.39
NetC410_1: C410.1 R344.1
NetC411_2: C411.2 C412.2 L56.2 U25.6@5605.97,6058.67 | length 195.9
  L12_Bottom Layer w20: U25.6@5605.97,6058.67 5649.47,6058.67 C412.2@5680.97,6090.22 ; C412.2@5680.97,6090.22 C411.2@5733.97,6090.22 ; C411.2@5734.27,6089.92 C411.2@5733.97,6090.22 ; L56.2@5788.35,6090.22 C411.2@5733.97,6090.22
NetC414_2: C414.2 C416.2 C418.2 C419.2 L21.1 Y1.4
  other v2: 5533,5720 5523,5752
NetC417_2: C417.2 R359.1 Y1.1 | length 150.6
  L1_Top Layer w11: Y1.1@5574.02,6083.56 5574.02,6184.83 C417.2@5574.28,6185.09 5574.28,6233.79 R359.1@5574.12,6233.95
NetC424_2: C424.2 R369.2 R412.1 SYNC1.1 U24.6 | length 393.1
  L1_Top Layer w9.84: 4390,4984.26 4394.68,4988.94 U24.6@4418.03,4988.94
  L1_Top Layer w11: v1(4360.89,4957) 4362.74,4957 4390,4984.26
  L12_Bottom Layer w11: SYNC1.1@4227.97,5199.02 4227.97,5097.06 C424.2@4318.09,5006.94 4317.72,5006.56 R369.2@4317.72,4956.94 4317.78,4957 v1(4360.89,4957)
NetC431_1: C431.1 U24.12 | length 103.3
  L1_Top Layer w8: v1(4372.72,4871.96) 4371.78,4871.96 4371,4871.19 4371.47,4870.72 4371.58,4870.83 U24.12@4418.03,4870.83
  L12_Bottom Layer w20: v1(4372.72,4871.96) 4397.21,4871.96 C431.1@4418.03,4851.14
NetC432_1: C432.1 U24.11 | length 118.6
  L1_Top Layer w8: v1@4299.47,4890.51 U24.11@4418.03,4890.51
  other v1: 4298.97,4890.02
NetC481_1: C481.1 U38.1 | length 99.7
  L1_Top Layer w10: U38.1@5059.82,11252.43 5088.89,11252.43 5099.82,11241.51 C481.1@5099.82,11186.3
NetC490_1: C490.1 R5.1 R6.1 R8.2 R553.1 U1.5 | length 321.4
  L1_Top Layer w10: R6.1@509.38,8964 532.55,8940.83 U1.5@603.64,8940.83
  L1_Top Layer w11: C490.1@424.21,9113.27 R8.2@389.21,9078.27 428.62,9038.85 R553.1@428.62,9037.98 R5.1@463.62,9002.98 470.4,9002.98 R6.1@509.38,8964
NetC491_2: C491.2 R12.2 R16.1 R19.2 R554.1 U1.6 | length 320.2
  L1_Top Layer w10: R16.1@509.38,8897 533.53,8921.15 U1.6@603.64,8921.15
  L1_Top Layer w11: C491.2@425,8749 R12.2@390,8784 390,8784.38 R554.1@428.62,8823 R19.2@463.62,8858 470.38,8858 R16.1@509.38,8897
NetC492_2: C492.2 R555.2 | length 49.5
  L1_Top Layer w11: C492.2@460,8714 R555.2@495,8679
NetC493_1: C493.1 R29.1 R30.1 R32.2 R562.1 U4.5 | length 313.7
  L1_Top Layer w10: R30.1@511.18,7541.87 534.34,7518.71 U4.5@605.43,7518.71
  L1_Top Layer w11: C493.1@426.01,7691.14 R32.2@391.01,7656.14 R562.1@430.42,7616.73 ; R562.1@430.42,7615.85 R29.1@465.42,7580.85 ; R29.1@472.2,7580.85 R30.1@511.18,7541.87
NetC495_1: C495.1 L57.2 R489.2 R490.2 R491.2 TP21.1 U39.4 U39.5 U40.1 | length 157.2
  L1_Top Layer w10: 2802.69,11185.81 R489.2@2802.69,11246.7
  L12_Bottom Layer w10: R490.2@2832.28,11281.33 2835.23,11284.27 U39.5@2893.32,11284.27 ; 2976,11250.25 U39.4@2976,11284.27
  other v2: 2839.04,11157.49 2878.04,11157.49 2839.04,11196.49 2878.04,11196.49
NetC499_2: C499.2 R36.2 R40.1 R43.2 R563.1 U4.6 | length 313
  L1_Top Layer w10: R40.1@511.18,7474.87 535.32,7499.02 U4.6@605.43,7499.02
  L1_Top Layer w11: R36.2@391.8,7361.87 C499.2@426.8,7326.87 ; R36.2@391.8,7362.25 R563.1@430.42,7400.87 R43.2@465.42,7435.87 ; R43.2@472.18,7435.87 R40.1@511.18,7474.87
NetC500_2: C500.2 R564.2 | length 49.5
  L1_Top Layer w11: C500.2@461.8,7291.87 R564.2@496.8,7256.87
NetC501_2: C501.2 U39.8 | length 77.2
  L12_Bottom Layer w20: C501.2@2873.16,11429.33 2893.99,11408.51 2893.32,11407.84 U39.8@2893.32,11361.05
NetC502_1: C502.1 R86.1 R87.1 R89.2 R571.1 U10.5 | length 313.7
  L1_Top Layer w10: R87.1@512.69,2617.64 535.86,2594.47 U10.5@606.95,2594.47
  L1_Top Layer w11: C502.1@427.52,2766.9 R89.2@392.52,2731.9 R571.1@431.94,2692.49 ; R571.1@431.94,2691.62 R86.1@466.94,2656.62 ; R86.1@473.71,2656.62 R87.1@512.69,2617.64
NetC503_2: C503.2 R93.2 R97.1 R100.2 R572.1 U10.6 | length 313
  L1_Top Layer w10: R97.1@512.69,2550.64 536.84,2574.79 U10.6@606.95,2574.79
  L1_Top Layer w11: R93.2@393.32,2437.64 C503.2@428.32,2402.64 ; R93.2@393.32,2438.02 R572.1@431.94,2476.64 R100.2@466.94,2511.64 ; R100.2@473.7,2511.64 R97.1@512.69,2550.64
NetC504_2: C504.2 R573.2 | length 49.5
  L1_Top Layer w11: C504.2@463.32,2367.64 R573.2@498.32,2332.64
NetC505_1: C505.1 R110.1 R111.1 R113.2 R580.1 U13.5 | length 313.7
  L1_Top Layer w10: R111.1@512.77,1198.3 535.94,1175.14 U13.5@607.03,1175.14
  L1_Top Layer w11: C505.1@427.6,1347.57 R113.2@392.6,1312.57 R580.1@432.01,1273.16 ; R580.1@432.01,1272.28 R110.1@467.01,1237.28 ; R110.1@473.79,1237.28 R111.1@512.77,1198.3
NetC506_2: C506.2 R117.2 R121.1 R124.2 R581.1 U13.6 | length 313
  L1_Top Layer w10: R121.1@512.77,1131.3 536.92,1155.45 U13.6@607.03,1155.45
  L1_Top Layer w11: R117.2@393.39,1018.3 C506.2@428.39,983.3 ; R117.2@393.39,1018.68 R581.1@432.01,1057.3 R124.2@467.01,1092.3 ; R124.2@473.77,1092.3 R121.1@512.77,1131.3
NetC507_2: C507.2 R582.2 | length 49.5
  L1_Top Layer w11: C507.2@463.39,948.3 R582.2@498.39,913.3
NetC509_1: C509.1 C643.1 L90.1 U48.1 U48.2 | length 104.9
  L12_Bottom Layer w10: U48.1@1409.21,11361.21 1409.21,11395.07 1417.14,11403
  L12_Bottom Layer w11: U48.2@1409.21,11335.62 1451.13,11335.62 C509.1@1463.76,11348.25
NetC510_1: C510.1 C690.1 L91.2 U51.1 U51.2 | length 54.6
  L12_Bottom Layer w15: U51.2@705.89,11337.44 733.38,11337.44 ; U51.1@705.89,11363.03 732.98,11363.03
NetC516_1: C516.1 C517.1 C518.1 L57.1 R222.1 TP82.1 U41.15 U41.16 U41.17 | length 279.1
  L1_Top Layer w10: v1(3152.42,10997.6) 3153.42,10996.6 U41.15@3215.18,10996.6 3215.18,11006.53 3200.25,11021.46 ; U41.17@3189.59,10951.32 U41.16@3189.59,10971.01
  L1_Top Layer w12: 3147.7,10976.28 3172.65,10951.32 U41.17@3189.59,10951.32
  L1_Top Layer w20: 3159.16,11062.55 3200.25,11021.46
  L12_Bottom Layer w20: v1@3151.5,10996.68 v1(3152.42,10997.6)
  L12_Bottom Layer w30: C517.1@3097.92,10996.68 v1@3151.5,10996.68
NetC519_1: C519.1 C522.1 R493.1 R494.2 R614.1 U41.1 U41.19 U41.20 | length 157.8
  L1_Top Layer w10: 3165.03,10903.6 3166.43,10905.01 3189.59,10905.01 U41.20@3189.59,10892.27
  L1_Top Layer w12: 3158.7,10864.66 3158.7,10897.28 3173.38,10911.95 U41.19@3189.59,10911.95 ; 3201.6,10822.01 3215.18,10835.59 U41.1@3215.18,10866.68
NetC522_2: C522.2 U41.3 | length 183.9
  L1_Top Layer w10: C522.2@3246.35,10711.68 3285.36,10750.68 3285.36,10810.66 3254.55,10841.47 U41.3@3254.55,10866.68
NetC523_1: C523.1 U41.12 | length 98.1
  L1_Top Layer w10: U41.12@3274.24,10996.6 3274.24,11022.99 C523.1@3324.92,11073.68
NetC524_1: C524.1 U41.13 | length 73.9
  L1_Top Layer w10: C524.1@3248.92,11068.18 3254.55,11062.55 U41.13@3254.55,10996.6
NetC538_1: C538.1 L58.2 R501.2 R502.1 R503.2 TP25.1 U42.4 U42.5 U43.1 | length 155.9
  L1_Top Layer w10: 1946.76,11191.25 R503.2@1946.76,11250.87
  L12_Bottom Layer w10: R501.2@1965.28,11281.28 1968.23,11284.23 U42.5@2026.32,11284.23 ; 2109,11250.2 U42.4@2109,11284.23
  other v2: 1965.53,11156.86 2004.53,11156.86 1965.53,11195.86 2004.53,11195.86
NetC544_2: C544.2 U42.8 | length 77.2
  L12_Bottom Layer w20: C544.2@2006.17,11429.28 2026.99,11408.46 2026.32,11407.8 U42.8@2026.32,11361
NetC587_1: C587.1 C588.1 C589.1 L58.1 R415.1 TP83.1 U44.15 U44.16 U44.17 | length 279.1
  L1_Top Layer w10: v1(2278.59,10998.46) 2279.59,10997.46 U44.15@2341.35,10997.46 2341.35,11007.39 2326.42,11022.32 ; U44.17@2315.76,10952.18 U44.16@2315.76,10971.87
  L1_Top Layer w12: 2273.87,10977.13 2298.83,10952.18 U44.17@2315.76,10952.18
  L1_Top Layer w20: 2285.34,11063.41 2326.42,11022.32
  L12_Bottom Layer w20: v1@2277.67,10997.54 v1(2278.59,10998.46)
  L12_Bottom Layer w30: C588.1@2224.09,10997.54 v1@2277.67,10997.54
NetC590_1: C590.1 C593.1 R505.1 R506.2 R618.1 U44.1 U44.19 U44.20 | length 157.8
  L1_Top Layer w10: 2291.2,10904.46 2292.6,10905.86 2315.76,10905.86 U44.20@2315.76,10893.13
  L1_Top Layer w12: 2284.87,10865.52 2284.87,10898.13 2299.55,10912.81 U44.19@2315.76,10912.81 ; 2327.77,10822.86 2341.35,10836.44 U44.1@2341.35,10867.54
NetC593_2: C593.2 U44.3 | length 183.9
  L1_Top Layer w10: C593.2@2372.53,10712.54 2411.53,10751.54 2411.53,10811.52 2380.72,10842.33 U44.3@2380.72,10867.54
NetC595_1: C595.1 U44.13 | length 73.9
  L1_Top Layer w10: C595.1@2375.09,11069.04 2380.72,11063.41 U44.13@2380.72,10997.46
NetC608_2: C608.2 U45.8 | length 77.2
  L12_Bottom Layer w20: C608.2@3722.17,11433.46 3742.99,11412.64 3742.33,11411.97 U45.8@3742.33,11365.18
NetC613_1: C613.1 C614.1 C615.1 L59.1 R417.1 TP84.1 U47.15 U47.16 U47.17 | length 279.1
  L1_Top Layer w10: v1(3989.4,10993.59) 3990.4,10992.59 U47.15@4052.15,10992.59 4052.15,11002.53 4037.22,11017.46 ; U47.17@4026.56,10947.32 U47.16@4026.56,10967
  L1_Top Layer w12: 3984.67,10972.27 4009.63,10947.32 U47.17@4026.56,10947.32
  L1_Top Layer w20: 3996.14,11058.54 4037.22,11017.46
  L12_Bottom Layer w20: v1@3988.47,10992.67 v1(3989.4,10993.59)
  L12_Bottom Layer w30: C615.1@3934.9,10992.67 v1@3988.47,10992.67
NetC616_1: C616.1 C619.1 R517.1 R518.2 R622.1 U47.1 U47.19 U47.20 | length 157.8
  L1_Top Layer w10: 4002,10899.59 4003.41,10901 4026.56,10901 U47.20@4026.56,10888.26
  L1_Top Layer w12: 3995.67,10860.65 3995.67,10893.27 4010.35,10907.95 U47.19@4026.56,10907.95 ; 4038.57,10818 4052.15,10831.58 U47.1@4052.15,10862.67
NetC619_2: C619.2 U47.3 | length 183.9
  L1_Top Layer w10: C619.2@4083.33,10707.67 4122.33,10746.67 4122.33,10806.65 4091.53,10837.46 U47.3@4091.53,10862.67
NetC620_1: C620.1 U47.12 | length 98.1
  L1_Top Layer w10: U47.12@4111.21,10992.59 4111.21,11018.99 C620.1@4161.9,11069.67
NetC621_1: C621.1 U47.13 | length 73.9
  L1_Top Layer w10: C621.1@4085.9,11064.17 4091.53,11058.54 U47.13@4091.53,10992.59
NetC647_1: C647.1 L68.2 R525.2 R526.2 R527.2 TP42.1 U48.4 U48.5 U49.1 | length 134.8
  L1_Top Layer w10: 1239.76,11194.53 R525.2@1239.76,11252.87
  L12_Bottom Layer w10: R526.2@1268.37,11281.5 1271.31,11284.44 U48.5@1326.53,11284.44 ; 1409.21,11267.36 U48.4@1409.21,11284.44
  other v2: 1224.83,11148.44 1263.83,11148.44 1224.83,11187.44 1263.83,11187.44
NetC654_2: C654.2 U48.8 | length 76.6
  L12_Bottom Layer w10: C654.2@1306.37,11429.5 1326.53,11409.34 U48.8@1326.53,11361.21
NetC655_1: C655.1 C656.1 C657.1 L68.1 R419.1 TP85.1 U50.15 U50.16 U50.17 | length 279.1
  L1_Top Layer w10: v1(1544.72,11000.32) 1545.72,10999.32 U50.15@1607.48,10999.32 1607.48,11009.26 1592.55,11024.19 ; U50.17@1581.89,10954.05 U50.16@1581.89,10973.73
  L1_Top Layer w12: 1540,10979 1564.95,10954.05 U50.17@1581.89,10954.05
  L1_Top Layer w20: TP85.1@1551.46,11065.28 1592.55,11024.19
  L12_Bottom Layer w20: v1@1543.8,10999.4 v1(1544.72,11000.32)
  L12_Bottom Layer w30: C657.1@1490.22,10999.4 v1@1543.8,10999.4
NetC660_1: C660.1 C667.1 R529.1 R530.2 R531.2 R626.1 U50.1 U50.19 U50.20 | length 159.2
  L1_Top Layer w8: C667.1@1574.66,10713.4 v2(1575.66,10714.4)
  L1_Top Layer w10: 1557.33,10906.33 1558.73,10907.73 1581.89,10907.73 U50.20@1581.89,10894.99
  L1_Top Layer w12: 1551,10867.38 1551,10900 1565.68,10914.68 U50.19@1581.89,10914.68 ; 1593.9,10824.73 1607.48,10838.31 U50.1@1607.48,10869.4
NetC667_2: C667.2 R531.1 R532.2 U50.3 | length 258.9
  L1_Top Layer w10: v1(1638.65,10714.4) 1677.66,10753.41 1677.66,10813.39 1646.85,10844.19 U50.3@1646.85,10869.4
  L12_Bottom Layer w8: v1(1638.65,10714.4) R532.2@1638.65,10789.4
NetC668_1: C668.1 U50.12 | length 98.1
  L1_Top Layer w8: U50.12@1666.54,10999.32 1666.54,11025.72 C668.1@1717.22,11076.4
NetC669_1: C669.1 U50.13 | length 73.9
  L1_Top Layer w8: C669.1@1641.22,11070.91 1646.85,11065.28 U50.13@1646.85,10999.32
NetC695_2: C695.2 C696.2 C697.2 C698.1 L69.2 R535.1 TP59.1 U51.3 U51.9 U52.1 | length 139.9
  L12_Bottom Layer w10: U51.9@666.05,11326.14 U51.9@664.55,11324.65 677.35,11311.85 U51.3@705.89,11311.85
  L12_Bottom Layer w15: U51.3@705.89,11311.85 730.07,11311.85 747.55,11294.36 C695.2@789.8,11294.36
  other v2: 356.39,11122 395.39,11122 356.39,11161 395.39,11161 356.39,11200 395.39,11200
  other v3: 650.55,11295.12 678.55,11295.59 650.55,11324.65 678.55,11325.12 650.55,11354.18 678.55,11354.65
NetC698_2: C698.2 U51.8 | length 76.6
  L12_Bottom Layer w10: C698.2@603.06,11431.32 623.22,11411.16 U51.8@623.22,11363.03
NetC714_1: C714.1 C716.1 R536.2 R630.1 U53.1 U53.20 | length 76.8
  L1_Top Layer w11: 725.19,10849.92 U53.20@764.38,10849.92 ; 804.73,10771.99 U53.1@804.73,10809.57
NetC715_2: C715.2 L69.1 TP86.1 U53.13 U53.15 U53.16 | length 139.8
  L1_Top Layer w8: U53.13@855.91,10992.64 855.91,11065.17
  L1_Top Layer w10: 798,11023 804.73,11016.27 U53.15@804.73,10992.64
  L1_Top Layer w18: 730.29,10952.29 U53.16@764.38,10952.29
NetC716_2: C716.2 R536.1 R537.2 U53.3 | length 206.7
  L1_Top Layer w8: C716.2@855.91,10744.66 U53.3@855.91,10809.57
  L1_Top Layer w20: C716.2@855.91,10744.66 C716.2@858,10742.57 851.42,10735.99 851.42,10688.87 R536.1@845.12,10682.57 918.12,10682.57 R537.2@918.5,10682.95
NetC723_1: C723.1 U53.14 | length 49
  L1_Top Layer w8: U53.14@830.32,10992.64 v2@830.32,11041.47
  L1_Top Layer w10: v2@830.32,11041.47 v2(830.42,11041.57)
NetCALSAT1_1: CALSAT1.1 U8.F7 | length 1900.8
  L1_Top Layer w3.5: U8.F7@2413.91,8240.84 2429.93,8256.86 2429.93,8425.11 2433.82,8429 2433.82,8677.49 2531.33,8775
  L1_Top Layer w11: 2531.33,8775 2620.33,8864 3272,8864 3451.44,9043.44 3451.44,9222.69 CALSAT1.1@3375.44,9298.69
NetCALSAT2_1: CALSAT2.1 U17.F7 | length 1981.1
  L1_Top Layer w3.5: U17.F7@2417.24,1894.85 2433.26,1910.86 2433.26,2331.48 2535.87,2434.09
  L1_Top Layer w11: 2535.87,2434.09 2619.79,2518 3323,2518 3531,2726 3531,2874 CALSAT2.1@3440,2965
NetCE_TP1_1: CE_TP1.1 R172.2 U19.1 | length 395.5
  L1_Top Layer w11: CE_TP1.1@1863.66,5828.82 1964.61,5828.82 2056.1,5920.31 R172.2@2108.66,5920.31 2108.66,5980.56 2126.28,5998.18 U19.1@2126.28,6025.64
NetCE_TP2_1: CE_TP2.1 R213.2 U21.1 | length 395.5
  L1_Top Layer w11: U21.1@2425.34,3792.33 2425.34,3819.8 2442.96,3837.41 R213.2@2442.96,3897.66 2495.51,3897.66 2587.01,3989.16 CE_TP2.1@2687.96,3989.16
NetD1_1: D1.1 U7.1 | length 88.7
  L1_Top Layer w11: D1.1@4886.21,7277.66 4886.68,7277.18 U7.1@4974.72,7277.18
NetD1_2: D1.2 R50.2 | length 72.6
  L1_Top Layer w11: D1.2@4886.21,7336.71 4886.21,7408.81 R50.2@4886.59,7409.18
NetD3_1: D3.1 U7.7 | length 161.3
  L1_Top Layer w11: U7.7@5163.7,7227.18 5210.71,7227.18 5223.21,7239.68 5223.21,7330.66 D3.1@5227.21,7334.66
NetD3_2: D3.2 R61.2 | length 63.6
  L1_Top Layer w11: D3.2@5227.21,7393.71 5290.12,7393.71 R61.2@5290.59,7394.18
NetD5_2: D5.2 R77.2 | length 67.5
  L1_Top Layer w11: R77.2@3191.1,9317.53 3246.61,9317.53 D5.2@3255.1,9326.03
NetD6_1: D6.1 U16.1 | length 88.7
  L1_Top Layer w11: D6.1@4969.3,869.72 4969.77,869.25 U16.1@5057.81,869.25
NetD6_2: D6.2 R131.2 | length 72.6
  L1_Top Layer w11: D6.2@4969.3,928.78 4969.3,1000.87 R131.2@4969.67,1001.25
NetD8_1: D8.1 U16.7 | length 161.3
  L1_Top Layer w11: U16.7@5246.78,819.25 5293.8,819.25 5306.3,831.75 5306.3,922.72 D8.1@5310.3,926.72
NetD8_2: D8.2 R142.2 | length 63.6
  L1_Top Layer w11: D8.2@5310.3,985.78 5373.2,985.78 R142.2@5373.67,986.25
NetD10_2: D10.2 R158.2 | length 67.5
  L1_Top Layer w11: R158.2@3259.43,2971.76 3314.94,2971.76 D10.2@3323.43,2980.26
NetD11_1: D11.1 R190.1 | length 54.7
  L1_Top Layer w6: R190.1@2499.31,6406.72 2499.31,6460.69 D11.1@2499.81,6461.19
NetD12_1: D12.1 R231.1 | length 54.7
  L1_Top Layer w6: D12.1@2051.8,3356.79 D12.1@2052.31,3357.29
  L1_Top Layer w11: D12.1@2052.31,3357.29 R231.1@2052.31,3411.26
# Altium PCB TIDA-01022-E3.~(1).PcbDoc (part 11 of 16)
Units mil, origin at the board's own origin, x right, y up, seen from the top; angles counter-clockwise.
Board outline 6929.13 x 11614.17 mil, 12 copper layers (L1_Top Layer, L2_GND, L3_GND, L4_Signal Layer 1, L5_GND, L6_PWR, L7_GND/PWR, L8_PWR, L9_GND/PWR, L10_Signal Layer 2, L11_GND, L12_Bottom Layer), stack 64.6 mil thick; 1733 components, 993 nets, 5987 pads, 3555 vias.

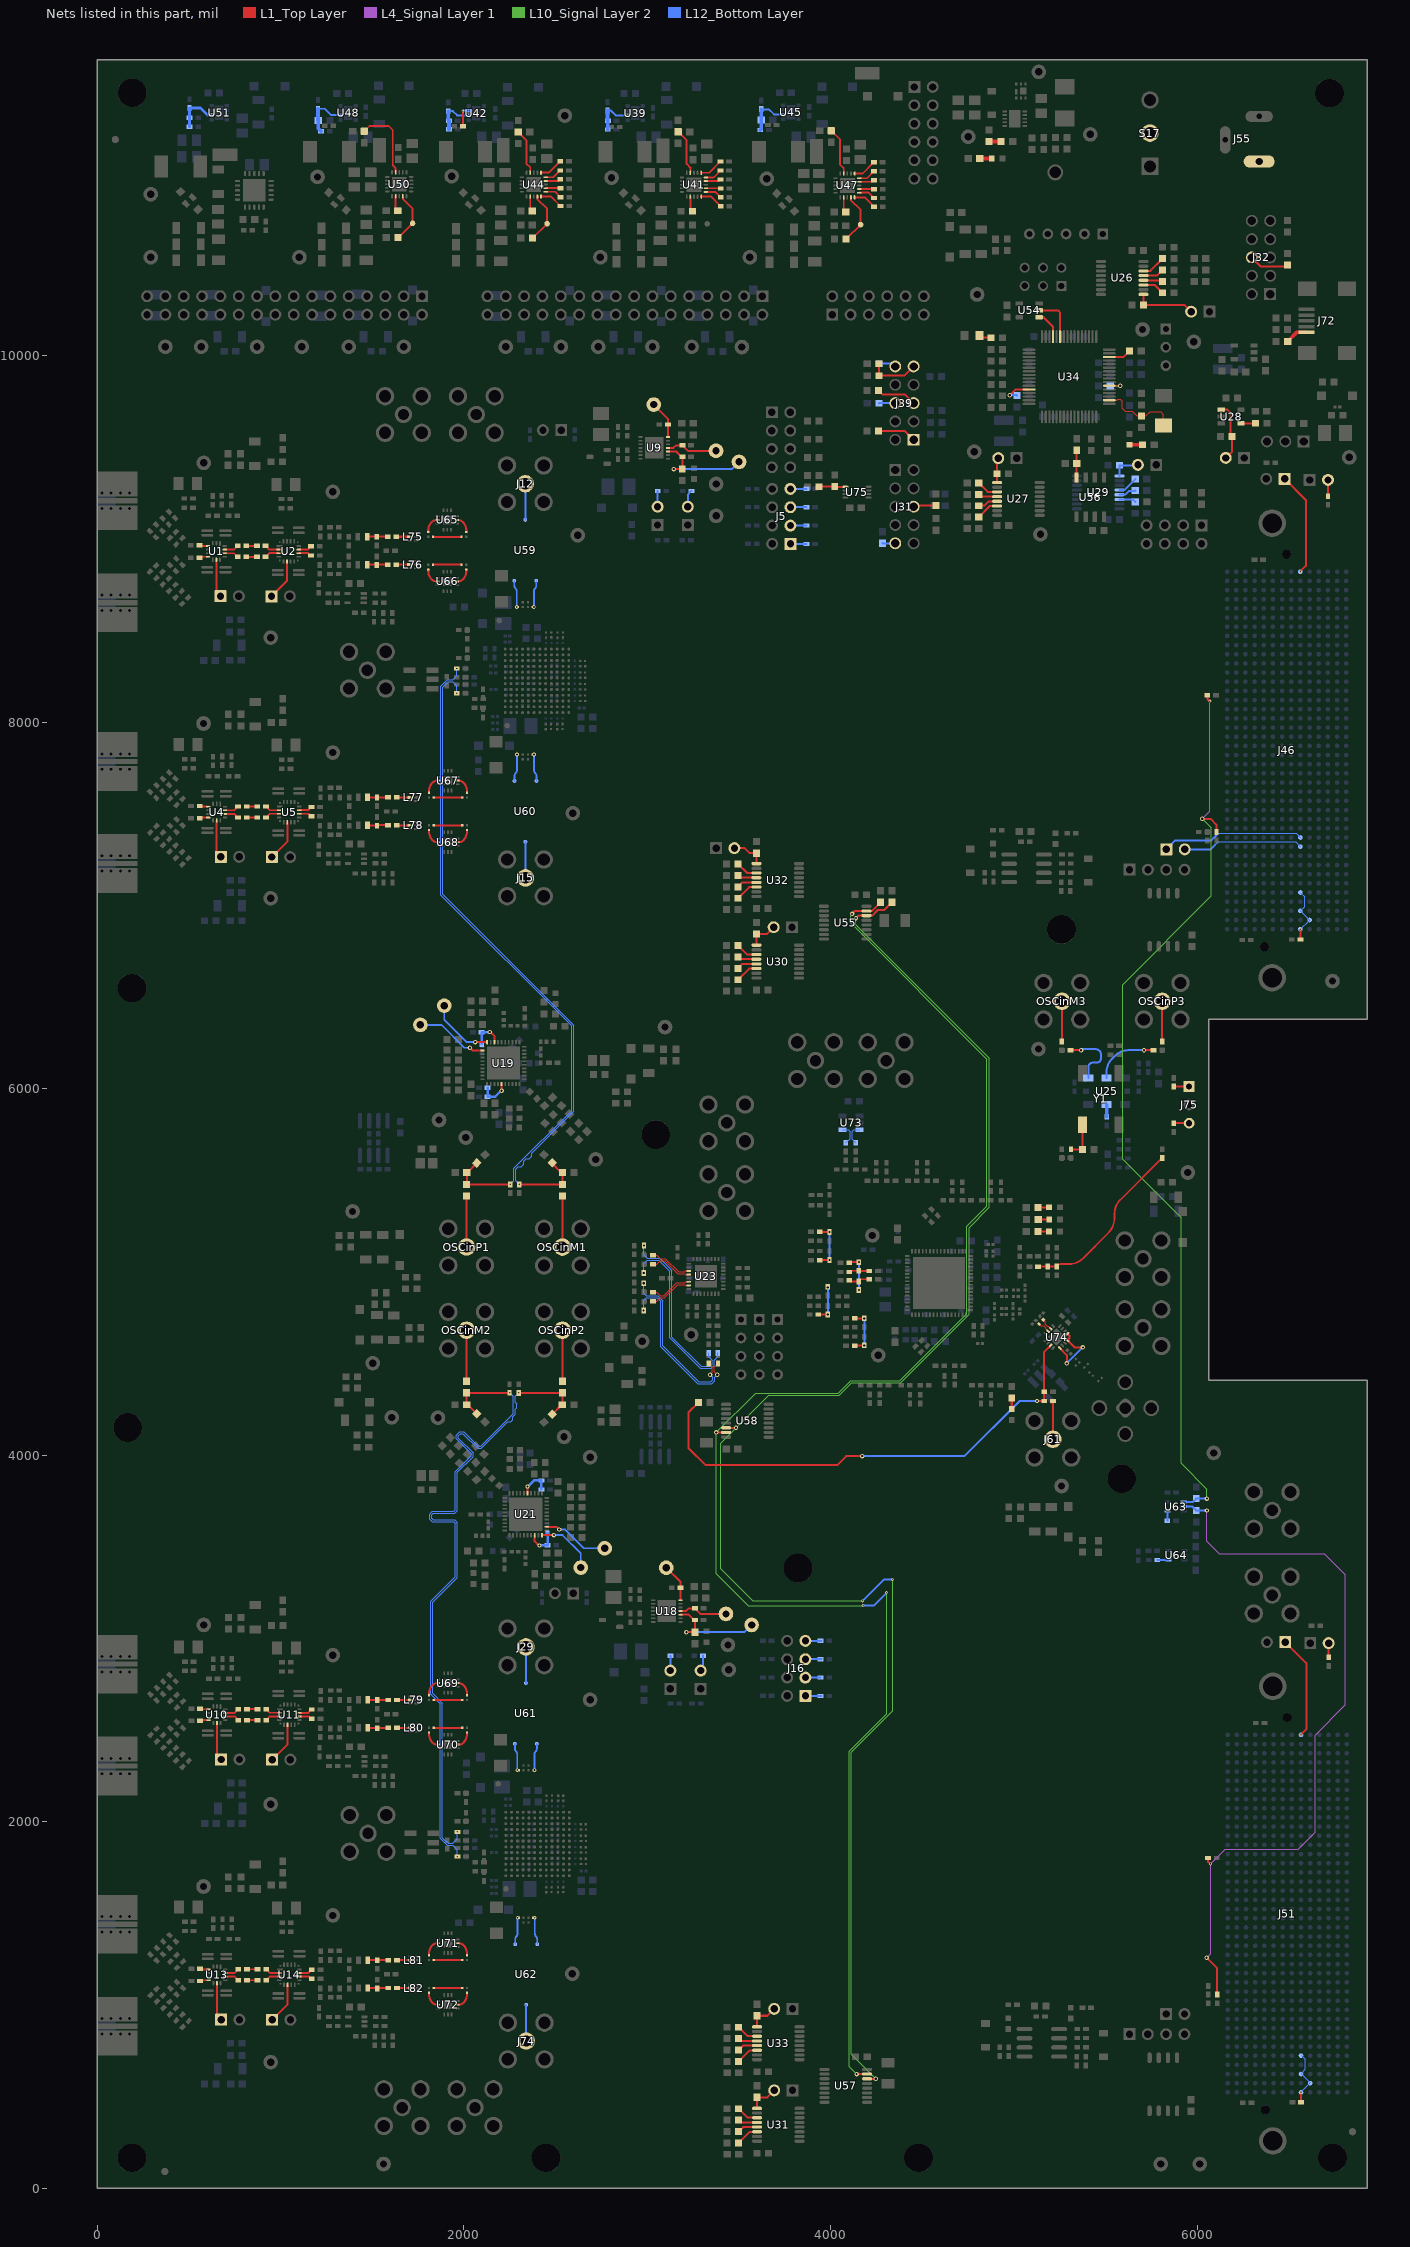
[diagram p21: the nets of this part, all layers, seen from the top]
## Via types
v1: diameter 16, hole 8, L1_Top Layer to L12_Bottom Layer, tented both sides, 1686 vias
v2: diameter 24, hole 12, L1_Top Layer to L12_Bottom Layer, tented both sides, 1590 vias
v3: diameter 20, hole 10, L1_Top Layer to L12_Bottom Layer, 279 vias

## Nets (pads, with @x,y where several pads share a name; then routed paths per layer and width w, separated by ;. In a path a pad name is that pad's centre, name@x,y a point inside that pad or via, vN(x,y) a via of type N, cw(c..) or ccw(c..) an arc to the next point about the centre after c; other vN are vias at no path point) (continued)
NetD13_1: D13.1 R370.2 | length 61.4
  L1_Top Layer w11: R370.2@5130.98,5352.39 5190.96,5352.39 D13.1@5191.96,5353.39
NetD14_1: D14.1 R371.2 | length 60
  L1_Top Layer w11: R371.2@5132.52,5286.39 D14.1@5192.5,5286.39
NetD15_1: D15.1 R372.2 | length 60
  L1_Top Layer w11: D15.1@4988.39,4251.5 R372.2@4988.39,4311.48
NetD16_1: D16.1 R373.2 | length 61
  L1_Top Layer w11: R373.2@5130.97,5220.14 D16.1@5191.94,5220.14
NetD17_2: D17.2 R469.2 | length 71
  L1_Top Layer w20: D17.2@5630.88,9512.44 R469.2@5701.86,9512.44
NetD18_2: D18.2 R549.2 | length 66.9
  L1_Top Layer w11: D18.2@4813.34,10109 4825.34,10097 R549.2@4875.31,10097
NetD21_1: D21.1 R485.1 | length 65.5
  L1_Top Layer w20: R485.1@4813.81,11074.8 D21.1@4879.29,11074.8
NetJ5_1: J5.1 R57.2 | length 87.5
  L12_Bottom Layer w6: J5.1@3781.08,8971.88 J5.1@3781.97,8970.99
  L12_Bottom Layer w11: J5.1@3781.97,8970.99 R57.2@3868.18,8970.99
NetJ5_3: J5.3 R56.2 | length 87.1
  L12_Bottom Layer w6: J5.3@3781.08,9071.88 J5.3@3781.19,9071.99
  L12_Bottom Layer w11: J5.3@3781.19,9071.99 R56.2@3868.18,9071.99
NetJ5_5: J5.5 R55.2 | length 87.1
  L12_Bottom Layer w6: J5.5@3781.08,9171.88 J5.5@3781.19,9171.99
  L12_Bottom Layer w11: J5.5@3781.19,9171.99 R55.2@3868.18,9171.99
NetJ5_7: J5.7 R54.2 | length 87.1
  L12_Bottom Layer w6: R54.2@3868.07,9271.88 R54.2@3868.18,9271.99
  L12_Bottom Layer w11: J5.7@3781.08,9271.88 R54.2@3868.07,9271.88
NetJ6_2: J6.2 R63.1 | length 86.2
  L12_Bottom Layer w11: J6.2@3056.08,9174.99 3056.08,9260.31 R63.1@3056.68,9260.91
NetJ7_2: J7.2 R64.1 | length 94.1
  L12_Bottom Layer w11: J7.2@3221.08,9174.99 3221.08,9241.06 R64.1@3240.92,9260.91
NetJ12_1: J12.1 U59.1 | length 197
  L12_Bottom Layer w11: U59.1@2334.48,9103.21 J12.1@2334.48,9300.21
NetJ15_1: J15.1 U60.1 | length 197
  L12_Bottom Layer w11: J15.1@2335.24,7149.98 U60.1@2335.24,7346.98
NetJ16_1: J16.1 R138.2 | length 87.5
  L12_Bottom Layer w6: J16.1@3862.72,2686.99 J16.1@3863.61,2686.1
  L12_Bottom Layer w11: J16.1@3863.61,2686.1 R138.2@3949.81,2686.1
NetJ16_3: J16.3 R137.2 | length 87.1
  L12_Bottom Layer w6: J16.3@3862.72,2786.99 J16.3@3862.82,2787.1 ; R137.2@3945.09,2787.1 R137.2@3949.81,2787.1
  L12_Bottom Layer w11: J16.3@3862.82,2787.1 R137.2@3945.09,2787.1
NetJ16_5: J16.5 R136.2 | length 87.1
  L12_Bottom Layer w6: J16.5@3862.72,2886.99 J16.5@3862.82,2887.1
  L12_Bottom Layer w11: J16.5@3862.82,2887.1 R136.2@3949.81,2887.1
NetJ16_7: J16.7 R135.2 | length 87
  L12_Bottom Layer w11: J16.7@3862.72,2986.99 R135.2@3949.71,2986.99
NetJ17_2: J17.2 R144.1 | length 80.7
  L12_Bottom Layer w11: J17.2@3126.01,2825.21 3126.01,2905.4 R144.1@3126.37,2905.76
NetJ18_2: J18.2 R145.1 | length 86.6
  L12_Bottom Layer w11: J18.2@3291.01,2825.21 3303.9,2838.1 R145.1@3303.9,2906.49
NetJ29_1: J29.1 U61.1 | length 197
  L12_Bottom Layer w11: U61.1@2337.48,2757.59 J29.1@2337.48,2954.59
NetJ31_6: J31.6 R595.2 | length 130.4
  L1_Top Layer w11: J31.6@4447.07,9182.1 4448.07,9181.1 J31.6@4453,9181.1 ; J31.6@4453,9175 4459.1,9181.1 R595.2@4574.57,9181.1
NetJ31_9: J31.9 R593.1 | length 70.2
  L12_Bottom Layer w11: R593.1@4283,8975.5 4283.5,8975 J31.9@4353,8975
NetJ32_6: J32.6 R596.2 | length 218.1
  L1_Top Layer w11: J32.6@6298.35,10534.59 6348.35,10484.59 6483.74,10484.59 R596.2@6492.24,10493.09
NetJ35_2: J35.2 R404.2 U26.9 | length 332.7
  L1_Top Layer w11: U26.9@5707,10333.41 R404.2@5707,10276 5930,10276 J35.2@5967,10239
NetJ36_2: J36.2 R411.2 U27.9 | length 136.1
  L1_Top Layer w11: U27.9@4908.68,9306.77 4908.68,9354.65 R411.2@4908.32,9355 4908.32,9433.5 J36.2@4914.82,9440
NetJ37_2: J37.2 R420.2 U28.1 | length 321.6
  L1_Top Layer w11: U28.1@6131.45,9704.31 6164.69,9704.31 6183,9686 6183,9564.83 R420.2@6190.54,9557.28 6190.54,9475.54 J37.2@6156,9441
NetJ38_2: J38.2 R425.2 U29.9 | length 160.1
  L12_Bottom Layer w11: U29.9@5575.96,9342.57 5575.96,9400.65 R425.2@5576.31,9401 5675,9401 J38.2@5677,9403
NetJ39_1: J39.1 R601.2 | length 210.9
  L1_Top Layer w11: R601.2@4262,9588 4405,9588 J39.1@4453,9540
NetJ39_5: J39.5 R602.2 | length 219.6
  L1_Top Layer w11: R602.2@4262,9809 4282.82,9788.18 4404.82,9788.18 J39.5@4453,9740
NetJ39_6: J39.6 R600.2 | length 89.9
  L12_Bottom Layer w11: R600.2@4263.5,9739 4264.5,9740 J39.6@4353,9740
NetJ39_9: J39.9 R597.1 R598.1 | length 276.2
  L1_Top Layer w11: R597.1@4263.5,9889 R597.1@4263.5,9890 ; R598.1@4263.5,9955 R597.1@4263.5,9890 ; J39.9@4453,9940 4403,9890 R597.1@4263.5,9890
NetJ39_10: J39.10 R599.1 | length 95.7
  L12_Bottom Layer w11: R599.1@4263.5,9955 4338,9955 J39.10@4353,9940
NetJ41_2: J41.2 R440.2 U30.9 | length 170.1
  L1_Top Layer w11: U30.9@3595.33,6782.79 3595.33,6842.97 R440.2@3595.07,6843.23 3651.58,6843.23 J41.2@3689.07,6880.73
NetJ42_2: J42.2 R441.2 U31.9 | length 170.1
  L1_Top Layer w11: U31.9@3598.66,436.79 3598.66,496.98 R441.2@3598.4,497.23 3654.91,497.23 J42.2@3692.4,534.73
NetJ43_2: J43.2 R467.2 U32.9 | length 188.7
  L1_Top Layer w11: J43.2@3475.43,7312.26 3531.43,7312.26 3558.93,7284.76 R467.2@3595.43,7284.76 3595.33,7284.66 U32.9@3595.33,7227.49
NetJ44_2: J44.2 R468.2 U33.9 | length 169.7
  L1_Top Layer w11: R468.2@3598.4,941.94 3654.91,941.94 J44.2@3692.4,979.44 ; U33.9@3598.66,881.5 R468.2@3598.66,941.68
NetJ45_1: J45.1 J46.D1 | length 563.5
  L1_Top Layer w11: J45.1@6477.4,9326.54 6592.51,9211.42 6592.51,8851.9 v1@6563.42,8822.81
  other v1: 6563.11,8820.01
NetJ46_C39: J46.C39 J46.D36 J46.D38 J46.D40 R474.2 | length 316.9
  L1_Top Layer w11: R474.2@6563.11,6813.63 v1(6563.11,6870.01)
  L12_Bottom Layer w5: v1(6563.11,6870.01) J46.C39@6613.11,6920.01 J46.D38@6563.11,6970.01 6586.11,6993.01 6586.11,7047.01 J46.D36@6563.11,7070.01
NetJ46_D30: J46.D30 J47.1 | length 776.9
  L12_Bottom Layer w5: 6104.09,7381.18 6115.92,7393.01 6540.11,7393.01 J46.D30@6563.11,7370.01
  L12_Bottom Layer w11: J47.1@5832.09,7305.18 5880.91,7354 6076.91,7354 6104.09,7381.18
NetJ46_D31: J46.D31 J47.2 | length 658.7
  L12_Bottom Layer w5: 6098.09,7330.01 6114.09,7346.01 6537.11,7346.01 J46.D31@6563.11,7320.01
  L12_Bottom Layer w11: J47.2@5932.09,7305.18 6073.26,7305.18 6098.09,7330.01
NetJ49_2: J49.2 R475.2 | length 88.9
  L1_Top Layer w11: J49.2@6713.79,9320.76 R475.2@6713.79,9232.4 R475.2@6714.19,9232.81
NetJ50_1: J50.1 J51.D1 | length 563.5
  L1_Top Layer w11: J50.1@6480.73,2980.54 6595.84,2865.43 6595.84,2505.91 v1@6566.75,2476.81
  other v1: 6566.44,2474.01
NetJ51_C39: J51.C39 J51.D36 J51.D38 J51.D40 R479.2 | length 313.4
  L1_Top Layer w11: v1(6566.44,524.01) 6566.75,523.7 R479.2@6566.75,470.43
  L12_Bottom Layer w5: J51.D40@6566.75,526.81 6616.75,576.81 6566.75,626.81 6588.75,648.81 6588.75,704.81 J51.D36@6566.75,726.81
NetJ54_2: J54.2 R480.2 | length 77.1
  L1_Top Layer w11: R480.2@6717.12,2897.67 J54.2@6717.12,2974.77
NetJ55_1: J55.1 S17.2
NetJ61_1: J61.1 R393.1 | length 209.1
  L1_Top Layer w11: J61.1@5212.88,4087.24 5212.88,4295.95 R393.1@5213.17,4296.24
NetJ64_1: J64.1 U2.6 | length 225.5
  L1_Top Layer w11: J64.1@949.68,8685.66 1034.25,8770.23 U2.6@1034.25,8876.14
NetJ67_1: J67.1 U1.9 | length 208.5
  L1_Top Layer w11: U1.9@648.91,8885.71 648.91,8709.42 J67.1@671.68,8686.66
NetJ68_1: J68.1 U5.6 | length 225.5
  L1_Top Layer w11: J68.1@951.47,7263.53 1036.05,7348.1 U5.6@1036.05,7454.01
NetJ72_1: J72.1 R470.1 | length 123
  L1_Top Layer w20: R470.1@6493.71,10077.06 6542.46,10125.81 J72.1@6596.53,10125.81
NetJ74_1: J74.1 U62.1 | length 197
  L12_Bottom Layer w11: J74.1@2339.42,804.02 U62.1@2339.42,1001.02
NetJ75_1: J75.1 R163.1 | length 83.8
  L1_Top Layer w11: R163.1@5872.62,6011.62 R163.1@5872.89,6011.36 J75.1@5956.31,6011.36
NetJ75_3: J75.3 R166.2 | length 83.4
  L1_Top Layer w11: R166.2@5872.89,5811.36 J75.3@5956.31,5811.36
NetJ78_1: J78.1 U4.9 | length 208.5
  L1_Top Layer w11: U4.9@650.71,7463.59 650.71,7287.29 J78.1@673.47,7264.53
NetJ79_1: J79.1 U11.6 | length 225.5
  L1_Top Layer w11: J79.1@952.99,2339.29 1037.57,2423.87 U11.6@1037.57,2529.78
NetJ82_1: J82.1 U10.9 | length 208.5
  L1_Top Layer w11: U10.9@652.23,2539.35 652.23,2363.06 J82.1@674.99,2340.29
NetJ83_1: J83.1 U14.6 | length 225.5
  L1_Top Layer w11: J83.1@953.07,919.96 1037.64,1004.53 U14.6@1037.64,1110.44
NetJ84_1: J84.1 U13.9 | length 208.5
  L1_Top Layer w11: U13.9@652.3,1120.02 652.3,943.72 J84.1@675.07,920.96
NetL2_2: L2.2 R4.1 R7.2 | length 111.8
  L1_Top Layer w11: L2.2@1471.57,9011.41 R7.2@1523.01,9011.41 ; R7.2@1523.38,9011.05 R4.1@1583.76,9011 R4.1@1583.76,9011
NetL4_2: L4.2 R17.2 R18.1 | length 112.5
  L1_Top Layer w11: L4.2@1471.57,8859.02 1523,8859.02 1523.38,8859.4 1583.38,8859.4 R18.1@1583.76,8859.02
NetL6_2: L6.2 R28.1 R31.2 | length 112.4
  L1_Top Layer w11: L6.2@1473.37,7589.29 1524.81,7589.29 R31.2@1525.18,7588.92 R28.1@1585.55,7588.87 R28.1@1585.55,7588.87
NetL8_2: L8.2 R41.2 R42.1 | length 112.5
  L1_Top Layer w11: L8.2@1473.37,7436.9 1524.8,7436.9 1525.18,7437.28 1585.18,7437.28 R42.1@1585.55,7436.9
NetL10_2: L10.2 R85.1 R88.2 | length 111.8
  L1_Top Layer w11: L10.2@1474.89,2665.05 R88.2@1526.33,2665.05 ; R88.2@1526.69,2664.68 1587.03,2664.68 R85.1@1587.07,2664.64
NetL12_2: L12.2 R98.2 R99.1 | length 112.5
  L1_Top Layer w11: L12.2@1474.89,2512.66 1526.32,2512.66 1526.69,2513.04 1586.69,2513.04 R99.1@1587.07,2512.66
NetL14_2: L14.2 R109.1 R112.2 | length 112.4
  L1_Top Layer w11: L14.2@1474.97,1245.72 1526.4,1245.72 R112.2@1526.77,1245.35 R109.1@1587.15,1245.3 R109.1@1587.15,1245.3
NetL16_2: L16.2 R122.2 R123.1 | length 112.5
  L1_Top Layer w11: L16.2@1474.97,1093.33 1526.39,1093.33 1526.77,1093.7 1586.77,1093.7 R123.1@1587.15,1093.33
NetL75_2: L75.2 R4.2 R638.1 | length 74.8
  L1_Top Layer w9: L75.2@1705.5,9011.13 L75.2@1705.63,9011
  L1_Top Layer w9.84: R638.1@1697.76,9011 L75.2@1705.63,9011
  L1_Top Layer w11: R4.2@1631,9011 R638.1@1697.76,9011
NetL76_2: L76.2 R18.2 R639.1 | length 66.8
  L1_Top Layer w11: R18.2@1631,8859.02 R639.1@1697.76,8859
NetL77_2: L77.2 R28.2 R640.1 | length 74.8
  L1_Top Layer w9: L77.2@1707.29,7589.01 L77.2@1707.43,7588.87
  L1_Top Layer w9.84: R640.1@1699.55,7588.87 L77.2@1707.43,7588.87
  L1_Top Layer w11: R28.2@1632.8,7588.87 R640.1@1699.55,7588.87
NetL78_2: L78.2 R42.2 R641.1 | length 66.8
  L1_Top Layer w11: R42.2@1632.8,7436.9 R641.1@1699.55,7436.87
NetL79_2: L79.2 R85.2 R642.1 | length 74.8
  L1_Top Layer w9: L79.2@1708.81,2664.77 L79.2@1708.95,2664.64
  L1_Top Layer w9.84: R642.1@1701.07,2664.64 L79.2@1708.95,2664.64
  L1_Top Layer w11: R85.2@1634.32,2664.64 R642.1@1701.07,2664.64
NetL80_2: L80.2 R99.2 R643.1 | length 66.8
  L1_Top Layer w11: R99.2@1634.32,2512.66 R643.1@1701.07,2512.64
NetL81_2: L81.2 R109.2 R644.1 | length 74.8
  L1_Top Layer w9: L81.2@1708.89,1245.44 L81.2@1709.02,1245.3
  L1_Top Layer w9.84: R644.1@1701.15,1245.3 L81.2@1709.02,1245.3
  L1_Top Layer w11: R109.2@1634.39,1245.3 R644.1@1701.15,1245.3
NetL82_2: L82.2 R123.2 R645.1 | length 66.8
  L1_Top Layer w11: R123.2@1634.39,1093.33 R645.1@1701.15,1093.3
NetOSCinM1_1: OSCinM1.1 R198.1 | length 278.5
  L1_Top Layer w11: OSCinM1.1@2537.16,5135.82 R198.1@2537.16,5414.32
NetOSCinM2_1: OSCinM2.1 R241.1 | length 278.5
  L1_Top Layer w11: R241.1@2014.46,4403.65 OSCinM2.1@2014.46,4682.16
NetOSCinM3_1: OSCinM3.1 R326.2 | length 219.8
  L1_Top Layer w11: R326.2@5262.04,6257.06 OSCinM3.1@5262.06,6476.85
NetOSCinP1_1: OSCinP1.1 R191.1 | length 278.5
  L1_Top Layer w11: OSCinP1.1@2014.46,5135.82 R191.1@2014.46,5414.32
NetOSCinP2_1: OSCinP2.1 R232.1 | length 278.5
  L1_Top Layer w11: R232.1@2537.16,4403.65 OSCinP2.1@2537.16,4682.16
NetOSCinP3_1: OSCinP3.1 R323.2 | length 219.8
  L1_Top Layer w11: R323.2@5809.06,6257.06 OSCinP3.1@5809.06,6476.85
NetR6_2: R6.2 U1.4 | length 48.5
  L1_Top Layer w10: R6.2@556.62,8964 560.1,8960.52 U1.4@603.64,8960.52
NetR9_1: R9.1 U1.13 | length 79.5
  L1_Top Layer w10: U1.13@694.19,8940.83 745.13,8940.83 R9.1@765.29,8960.99
NetR9_2: R9.2 R10.2 | length 58
  L1_Top Layer w6: R10.2@870.2,8960.99 R10.2@870.47,8961.26
  L1_Top Layer w10: R9.2@812.53,8960.99 R10.2@870.2,8960.99
NetR10_1: R10.1 U2.2 | length 79.6
  L1_Top Layer w10: R10.1@917.71,8961.26 937.87,8941.1 U2.2@988.97,8941.1
NetR11_2: R11.2 U2.11 | length 74.2
  L1_Top Layer w11: U2.11@1099.21,8941.1 1148.1,8941.1 R11.2@1166,8959
NetR13_1: R13.1 U1.12 | length 79.5
  L1_Top Layer w10: U1.12@694.19,8921.15 745.13,8921.15 R13.1@765.29,8900.99
NetR13_2: R13.2 R14.2 | length 58
  L1_Top Layer w6: R14.2@870.2,8900.99 R14.2@870.47,8901.26
  L1_Top Layer w10: R13.2@812.53,8900.99 R14.2@870.2,8900.99
NetR14_1: R14.1 U2.3 | length 79.6
  L1_Top Layer w10: R14.1@917.71,8901.26 937.87,8921.42 U2.3@988.97,8921.42
NetR15_2: R15.2 U2.10 | length 71.9
  L1_Top Layer w10: U2.10@1099.21,8921.42 1150.55,8921.42 1162.97,8909 R15.2@1166,8909
NetR16_2: R16.2 U1.7 | length 48.9
  L1_Top Layer w10: R16.2@556.62,8897 561.08,8901.46 U1.7@603.64,8901.46
NetR30_2: R30.2 U4.4 | length 43.5
  L1_Top Layer w10: R30.2@561.9,7538.39 U4.4@605.43,7538.39
NetR33_1: R33.1 U4.13 | length 79.5
  L1_Top Layer w10: U4.13@695.98,7518.71 746.93,7518.71 R33.1@767.09,7538.86
NetR33_2: R33.2 R34.2 | length 58
  L1_Top Layer w6: R34.2@872,7538.86 R34.2@872.27,7539.13
  L1_Top Layer w10: R33.2@814.33,7538.86 R34.2@872,7538.86
NetR34_1: R34.1 U5.2 | length 79.6
  L1_Top Layer w10: R34.1@919.51,7539.13 939.67,7518.97 U5.2@990.77,7518.97
NetR35_2: R35.2 U5.11 | length 74.2
  L1_Top Layer w11: U5.11@1101.01,7518.97 1149.9,7518.97 R35.2@1167.8,7536.87
NetR37_1: R37.1 U4.12 | length 79.5
  L1_Top Layer w10: U4.12@695.98,7499.02 746.93,7499.02 R37.1@767.09,7478.86
NetR37_2: R37.2 R38.2 | length 58
  L1_Top Layer w6: R38.2@872,7478.86 R38.2@872.27,7479.13
  L1_Top Layer w10: R37.2@814.33,7478.86 R38.2@872,7478.86
NetR38_1: R38.1 U5.3 | length 79.6
  L1_Top Layer w10: R38.1@919.51,7479.13 939.67,7499.29 U5.3@990.77,7499.29
NetR39_2: R39.2 U5.10 | length 71.9
  L1_Top Layer w10: U5.10@1101.01,7499.29 1152.35,7499.29 1164.76,7486.87 R39.2@1167.8,7486.87
NetR40_2: R40.2 U4.7 | length 42.6
  L1_Top Layer w10: R40.2@562.88,7479.34 U4.7@605.43,7479.34
NetR74_1: R74.1 R77.1 TP1.1 U9.10 | length 575.3
  L1_Top Layer w11: U9.10@3112.97,9475.9 3156.89,9475.9 3185.76,9447.03 R74.1@3191.48,9447.03 3191.48,9380.9 R77.1@3191.1,9380.52 3190.68,9380.1 v2@3145.25,9380.1
  L12_Bottom Layer w11: v2(3144.61,9380.1) 3461.21,9380.1 TP1.1@3500.46,9419.35
NetR75_1: R75.1 TP3.1 U9.11 | length 266.5
  L1_Top Layer w11: U9.11@3112.97,9495.58 3142.59,9495.58 3157.03,9510.03 R75.1@3191.48,9510.03 3221.61,9479.89 TP3.1@3360.97,9479.89
NetR76_1: R76.1 TP2.1 U9.14 | length 209.6
  L1_Top Layer w11: TP2.1@3035.1,9732.03 3112.72,9654.4 R76.1@3112.72,9623.03 3112.97,9622.78 U9.14@3112.97,9554.64
NetR87_2: R87.2 U10.4 | length 43.5
  L1_Top Layer w10: R87.2@563.42,2614.16 U10.4@606.95,2614.16
NetR90_1: R90.1 U10.13 | length 79.5
  L1_Top Layer w10: U10.13@697.5,2594.47 748.45,2594.47 R90.1@768.61,2614.63
NetR90_2: R90.2 R91.2 | length 58
  L1_Top Layer w6: R91.2@873.52,2614.63 R91.2@873.79,2614.9
  L1_Top Layer w10: R90.2@815.85,2614.63 R91.2@873.52,2614.63
NetR91_1: R91.1 U11.2 | length 79.6
  L1_Top Layer w10: R91.1@921.03,2614.9 941.19,2594.74 U11.2@992.29,2594.74
NetR92_2: R92.2 U11.11 | length 74.2
  L1_Top Layer w11: U11.11@1102.53,2594.74 1151.42,2594.74 R92.2@1169.32,2612.64
NetR94_1: R94.1 U10.12 | length 79.5
  L1_Top Layer w10: U10.12@697.5,2574.79 748.45,2574.79 R94.1@768.61,2554.63
NetR94_2: R94.2 R95.2 | length 58
  L1_Top Layer w6: R95.2@873.52,2554.63 R95.2@873.79,2554.9
  L1_Top Layer w10: R94.2@815.85,2554.63 R95.2@873.52,2554.63
NetR95_1: R95.1 U11.3 | length 79.6
  L1_Top Layer w10: R95.1@921.03,2554.9 941.19,2575.05 U11.3@992.29,2575.05
NetR96_2: R96.2 U11.10 | length 68.9
  L1_Top Layer w10: U11.10@1102.53,2575.05 1153.87,2575.05 R96.2@1166.28,2562.64
NetR97_2: R97.2 U10.7 | length 42.6
  L1_Top Layer w10: R97.2@564.4,2555.1 U10.7@606.95,2555.1
NetR111_2: R111.2 U13.4 | length 43.5
  L1_Top Layer w10: R111.2@563.5,1194.82 U13.4@607.03,1194.82
NetR114_1: R114.1 U13.13 | length 79.5
  L1_Top Layer w10: U13.13@697.58,1175.14 748.52,1175.14 R114.1@768.68,1195.29
NetR114_2: R114.2 R115.2 | length 58
  L1_Top Layer w6: R115.2@873.59,1195.29 R115.2@873.86,1195.56
  L1_Top Layer w10: R114.2@815.92,1195.29 R115.2@873.59,1195.29
NetR115_1: R115.1 U14.2 | length 79.6
  L1_Top Layer w10: R115.1@921.11,1195.56 941.26,1175.4 U14.2@992.37,1175.4
NetR116_2: R116.2 U14.11 | length 74.2
  L1_Top Layer w11: U14.11@1102.6,1175.4 1151.49,1175.4 R116.2@1169.39,1193.3
NetR118_1: R118.1 U13.12 | length 79.5
  L1_Top Layer w10: U13.12@697.58,1155.45 748.52,1155.45 R118.1@768.68,1135.29
NetR118_2: R118.2 R119.2 | length 58
  L1_Top Layer w6: R119.2@873.59,1135.29 R119.2@873.86,1135.56
  L1_Top Layer w10: R118.2@815.92,1135.29 R119.2@873.59,1135.29
NetR119_1: R119.1 U14.3 | length 79.6
  L1_Top Layer w10: R119.1@921.11,1135.56 941.26,1155.72 U14.3@992.37,1155.72
NetR120_2: R120.2 U14.10 | length 68.9
  L1_Top Layer w10: U14.10@1102.6,1155.72 1153.94,1155.72 R120.2@1166.36,1143.3
NetR121_2: R121.2 U13.7 | length 42.6
  L1_Top Layer w10: R121.2@564.48,1135.76 U13.7@607.03,1135.76
NetR155_1: R155.1 R158.1 TP7.1 U18.10 | length 574.7
  L1_Top Layer w11: U18.10@3181.3,3130.13 3225.22,3130.13 3254.09,3101.26 R155.1@3259.81,3101.26 3259.81,3035.13 R158.1@3259.43,3034.75 v2@3214.01,3034.75
  L12_Bottom Layer w11: v2(3213.36,3034.75) 3529.96,3034.75 TP7.1@3569.21,3074
NetR156_1: R156.1 TP9.1 U18.11 | length 266.5
  L1_Top Layer w11: U18.11@3181.3,3149.82 3210.92,3149.82 3225.36,3164.26 R156.1@3259.81,3164.26 3289.95,3134.12 TP9.1@3429.3,3134.12
NetR157_1: R157.1 TP8.1 U18.14 | length 209.6
  L1_Top Layer w11: TP8.1@3103.43,3386.26 3181.05,3308.64 R157.1@3181.05,3277.26 3181.3,3277.01 U18.14@3181.3,3208.87
NetR178_1: R178.1 R182.1 U19.5 | length 176.3
  L1_Top Layer w11: v2@2205.02,5988.82 U19.5@2205.02,6025.64
  L1_Top Layer w13.5: v2@2205.02,5988.82 v2(2205.31,5988.52)
  L12_Bottom Layer w13.5: R178.1@2128.93,6004.52 R182.1@2128.93,5955.52 2169.31,5955.52 2202.31,5988.52 v2(2205.31,5988.52)
NetR183_1: R183.1 R184.1 U19.28 | length 176.8
  L1_Top Layer w11: v2(2140.28,6308.92) 2144.28,6308.92 2165.65,6287.55 U19.28@2165.64,6253.99
  L12_Bottom Layer w13.5: R184.1@2096.31,6244.14 2095.93,6244.52 R183.1@2095.93,6308.52 2139.89,6308.52 v2(2140.28,6308.92)
NetR185_1: R185.1 R189.1 R191.2 R192.1 R195.2 | length 3680.5
  L1_Top Layer w11: R191.2@2015.15,5477.82 R189.1@2015.15,5542.82 ; R191.2@2015.41,5477.56 v1(2252.66,5477.56) ; R189.1@2016.91,5541.06 R192.1@2069.99,5594.15
  L12_Bottom Layer w6: v1(1960.92,8292.24) 1960.92,8252.42 1939,8230.5 1908.5,8230.5 1873,8195 1873,7056 2587,6342 2587,5880 2271.76,5564.76 2271.76,5496.66 v1(2252.66,5477.56)
NetR197_2: R197.2 R198.2 R199.2 R202.2 R203.2 | length 3676.6
  L1_Top Layer w11: R203.2@2302.41,5477.31 R198.2@2537.16,5477.31 ; R199.2@2481.53,5591.65 2533.76,5539.42 2537.16,5536.02 R198.2@2537.16,5477.37
  L12_Bottom Layer w6: v1(1960.92,8157.76) 1960.92,8197.58 1939,8219.5 1913.06,8219.5 1884,8190.44 1884,7060.56 2598,6346.56 2598,5875.44 2369,5646.44 2369,5630 2356.28,5617.28 2339.84,5617.28 2326,5603.44 2326,5587 2312.44,5573.44 2296,5573.44 2282.76,5560.2 2282.76,5496.35 v1(2301.86,5477.25)
NetR219_1: R219.1 R223.1 U21.5 | length 176.3
  L1_Top Layer w11: U21.5@2346.6,3792.33 v2@2346.6,3829.16
  L1_Top Layer w13.5: v2(2346.3,3829.45) v2@2346.6,3829.16
  L12_Bottom Layer w13.5: v2(2346.3,3829.45) 2349.3,3829.45 2382.3,3862.45 R223.1@2422.68,3862.45 R219.1@2422.68,3813.45
NetR222_2: R222.2 R386.1 R387.2 U41.14 | length 251.6
  L1_Top Layer w10: R222.2@3168,11220.5 R386.1@3168.46,11220.04 3214.54,11173.95 3214.54,11045.15 3234.87,11024.83 U41.14@3234.87,10996.6
NetR224_1: R224.1 R225.1 U21.28 | length 179.3
  L1_Top Layer w11: U21.28@2385.97,3563.98 2385.97,3530.42 2408.9,3507.49 v2(2411.74,3507.49)
  L12_Bottom Layer w13.5: v2(2411.74,3507.49) 2411.73,3509.45 R224.1@2455.68,3509.45 2455.68,3573.45 R225.1@2455.3,3573.83
NetR226_1: R226.1 R230.1 R232.2 R233.1 R236.2 | length 3680.7
  L1_Top Layer w11: v1(2298.96,4340.41) 2299.16,4340.41 R232.2@2536.21,4340.41 ; R233.1@2481.63,4223.83 R230.1@2534.71,4276.91 ; R230.1@2536.46,4275.16 R232.2@2536.46,4340.16
  L12_Bottom Layer w6: v1(1964.25,1944.84) 1964.25,1907.47 1939.88,1883.1 1912.76,1883.1 1882,1913.86 1882,2647.56 1828.78,2700.78 1828.78,3197.78 1963,3332 1963,3632.78 1948.28,3647.5 1831.28,3647.5 1823,3655.78 1823,3674.22 1831.28,3682.5 1948.28,3682.5 1963,3697.22 1963,3906 2049.24,3992.24 2049.24,4013.06 1968.63,4093.67 1968.63,4105.38 1981.67,4118.42 1993.38,4118.42 2073.99,4037.81 2094.81,4037.81 2239,4182 2256,4182 2266.58,4192.58 2266.58,4209.58 2279.58,4222.58 2279.58,4251 2288.58,4260 2288.58,4281 2279.58,4290 2279.58,4321.04 v1(2298.96,4340.41)
NetR238_2: R238.2 R241.2 R242.2 R243.2 R244.2 | length 3676.5
  L1_Top Layer w11: R241.2@2014.45,4340.61 2014.45,4281.96 2017.85,4278.56 R242.2@2070.09,4226.33 ; R241.2@2014.46,4340.66 2248.66,4340.66 v1(2249.21,4340.66)
  L12_Bottom Layer w6: v1(1964.25,1810.35) 1964.25,1847.72 1939.88,1872.1 1908.2,1872.1 1881.26,1899.04 1871,1909.3 1871,2643 1821,2693 1817.78,2696.22 1817.78,3202.33 1821,3205.56 1952,3336.56 1952,3628.22 1943.72,3636.5 1826.72,3636.5 1812,3651.22 1812,3678.78 1826.72,3693.5 1943.72,3693.5 1952,3701.78 1952,3910.56 2038.24,3996.8 2038.24,4008.51 1957.63,4089.12 1957.63,4109.94 1977.12,4129.42 1997.94,4129.42 2078.55,4048.81 2090.25,4048.81 2175.22,4133.78 2268.58,4227.14 2268.58,4321.29 v1(2249.21,4340.66)
NetR252_2: R252.2 R253.1 | length 963.1
  L12_Bottom Layer w6: v2(2982,5143.91) 2982,5092.92 3000.13,5074.79 3067.9,5074.79 3134.13,5008.56 3134.13,4644.87 3293.55,4485.45 3344.45,4485.45 3354.5,4495.5 3354.5,4517.67 3335.5,4536.67 R253.1@3335.5,4558.42
NetR254_1: R254.1 U23.3 | length 234.5
  L1_Top Layer w6: R254.1@3030.62,5091.58 3052.37,5091.58 3071.37,5072.58 3099.11,5072.58 3170.73,5000.96 3203.65,5000.96 3207.99,5005.3 U23.3@3225.8,5005.3
NetR255_1: R255.1 U23.4 | length 234.5
  L1_Top Layer w6: R255.1@3030.62,5042.58 3052.37,5042.58 3071.37,5061.58 3094.56,5061.58 3166.17,4989.96 3203.65,4989.96 3207.99,4985.62 U23.4@3225.8,4985.62
NetR256_2: R256.2 R257.1 | length 981.7
  L12_Bottom Layer w6: v2(2981,4994.67) 2981,5044.66 3000.13,5063.79 3063.35,5063.79 3123.13,5004 3123.13,4640.31 3288.99,4474.45 3349.01,4474.45 3352.23,4477.68 3365.5,4490.94 3365.5,4517.67 3384.5,4536.67 R257.1@3384.5,4558.42
NetR260_2: R260.2 R261.1 | length 888.3
  L1_Top Layer w6: R261.1@3335.75,4499.92 3355.25,4480.42 3355.25,4451.24 v2(3342.71,4438.69)
  L12_Bottom Layer w6: v2(2981,4937.91) 2981,4882.42 2994.13,4869.29 3058.4,4869.29 3084.13,4843.56 3084.13,4596.33 3280.01,4400.45 3346.71,4400.45 3356.71,4410.45 3356.71,4424.69 v2(3342.71,4438.69)
NetR262_1: R262.1 U23.6 | length 234.5
  L1_Top Layer w6: R262.1@3030.62,4889.29 3052.37,4889.29 3071.37,4870.29 3088.96,4870.29 3160.58,4941.91 3203.65,4941.91 3207.99,4946.25 U23.6@3225.8,4946.25
NetR264_1: R264.1 U23.7 | length 234.5
  L1_Top Layer w6: R264.1@3030.62,4840.29 3052.37,4840.29 3071.37,4859.29 3093.51,4859.29 3165.13,4930.91 3203.65,4930.91 3207.99,4926.56 U23.7@3225.8,4926.56
NetR265_2: R265.2 R266.1 | length 908.2
  L1_Top Layer w6: v2(3381.71,4438.69) 3366.25,4454.15 3366.25,4480.42 R266.1@3385.75,4499.92
  L12_Bottom Layer w6: v2(2980,4789.67) 2980,4844.16 2994.13,4858.29 3053.85,4858.29 3073.13,4839 3073.13,4591.78 3275.45,4389.45 3351.26,4389.45 3367.71,4405.9 3367.71,4424.69 v2(3381.71,4438.69)
NetR271_1: R271.1 R272.2 R273.1 R274.1 | length 259.1
  L1_Top Layer w6: R272.2@3941.09,5064.44 R272.2@3942.02,5065.37
  L1_Top Layer w9.84: R271.1@3941.09,5219.44 R271.1@3942.92,5217.61
  L1_Top Layer w10: R272.2@3942.02,5065.37 v2(3993.95,5065.37) ; R271.1@3942.92,5217.61 v2(3993.95,5217.61)
  L12_Bottom Layer w11: v2(3993.95,5065.37) v2(3993.95,5217.61)
NetR276_1: R276.1 R277.1 R282.2 | length 112
  L1_Top Layer w10: R277.1@4102.03,4999.77 4108.41,5006.15 R282.2@4154.41,5006.15 4155.79,5004.77 R276.1@4210.79,5004.77
NetR279_1: R279.1 R280.1 R283.2 | length 116.1
  L1_Top Layer w10: R280.1@4102.03,4954.77 4108.41,4948.39 R283.2@4154.41,4948.39 4165.79,4959.77 R279.1@4210.79,4959.77
NetR282_1: R282.1 R283.1 R285.1 | length 206.1
  L1_Top Layer w6: R285.1@4102.03,5049.77 R285.1@4105.65,5053.39
  L1_Top Layer w10: R285.1@4105.65,5053.39 v2(4154.41,5053.39)
  L12_Bottom Layer w11: v2(4154.41,4901.15) v2(4154.41,5053.39)
NetR286_1: R286.1 R287.2 R288.1 R289.1 | length 253.1
  L1_Top Layer w6: R287.2@4131.63,4598.08 R287.2@4133.01,4599.46 ; R286.1@4131.63,4748.08 R286.1@4133.01,4746.7
  L1_Top Layer w10: R287.2@4133.01,4599.46 v2(4184.01,4599.46) ; R286.1@4133.01,4746.7 v2(4184.01,4746.7)
  L12_Bottom Layer w11: v2(4184.01,4599.46) v2(4184.01,4746.7)
NetR299_1: R299.1 R300.1 R303.1 | length 198.8
  L1_Top Layer w10: R303.1@3934.14,4767.15 v2(3985.03,4767.15)
  L12_Bottom Layer w6: v2@3984.89,4767.29 v2(3985.03,4767.15)
  L12_Bottom Layer w11: v2@3984.89,4767.29 v2(3984.89,4915)
NetR344_2: R344.2 R351.2 Y1.3 | length 198.4
  L1_Top Layer w11: R344.2@5311.63,5668.72 5374.51,5668.72 R351.2@5374.63,5668.6 ccw(c5373.68,5669.55) 5375.03,5669.55 5375.03,5801.14 ccw(c5371.6,5801.14) Y1.3@5374.02,5803.56
NetR356_1: R356.1 U25.4@5405.97,6058.67 | length 349.9
  L1_Top Layer w11: R356.1@5319.44,6209.82 v2(5366.82,6209.82)
  L12_Bottom Layer w11: v2(5366.82,6209.82) cw(c5382.65,6193.99) 5382.65,6216.37 5441.03,6216.37 cw(c5441.03,6177.65) 5468.42,6205.03 cw(c5454.76,6191.37) 5474.08,6191.37 5474.08,6161.45 cw(c5457.01,6161.45) 5469.08,6149.37 cw(c5452.18,6166.27) 5452.18,6142.37 5432.39,6142.37 ccw(c5432.39,6115.06) 5413.08,6134.37 ccw(c5430.23,6117.22) 5405.97,6117.22 U25.4@5405.97,6058.67
NetR357_1: R357.1 U25.5@5505.97,6058.67 | length 353.5
  L1_Top Layer w11: v2(5709.82,6209.82) R357.1@5761.82,6209.82
  L12_Bottom Layer w11: U25.5@5505.97,6058.67 5505.97,6091.85 cw(c5605.97,6091.85) 5535.26,6162.56 5553.22,6180.52 cw(c5623.93,6109.81) 5623.93,6209.81 v2(5709.82,6209.82)
NetR358_2: R358.2 U25.2@5505.97,5913 | length 66.9
  L12_Bottom Layer w20: R358.2@5505.97,5846.11 U25.2@5505.97,5913
NetR388_1: R388.1 R389.2 R415.2 U44.14 | length 249
  L1_Top Layer w10: R415.2@2296,11219.5 2296,11218.77 2340.72,11174.06 2340.72,11046.01 2361.04,11025.69 U44.14@2361.04,10997.46
NetR390_2: R390.2 U73.3 | length 115.3
  L12_Bottom Layer w6: R390.2@4137.62,5704.37 4117,5724.99 4117,5765 4127.6,5775.6 U73.3@4158.74,5775.6
NetR391_2: R391.2 U73.4 | length 116.4
  L12_Bottom Layer w6: U73.4@4064.26,5775.6 4095.4,5775.6 4106,5765 4106,5727.75 R391.2@4082.62,5704.37
NetR393_2: R393.2 R397.2 R403.1 U74.15 | length 2714.2
  L1_Top Layer w11: R403.1@3279.8,4288.29 3225,4233.5 3225,4038.78 3318.33,3945.44 4035.44,3945.44 4085,3995 v2(4173,3995) ; v2(5126,4296) 5126.24,4296.24 R393.2@5165.92,4296.24 5165.64,4296.53 5165.64,4563.8 U74.15@5200.62,4598.78
  L12_Bottom Layer w11: v2(4173,3995) 4730,3995 5031,4296 v2(5126,4296)
NetR394_1: R394.1 U26.14 | length 131.5
  L1_Top Layer w11: U26.14@5707,10461.36 5744.09,10461.36 R394.1@5810.85,10528.12
NetR395_2: R395.2 U74.10 | length 69.2
  L1_Top Layer w6: R395.2@5160.46,4739.65 5171.11,4729.01 5171.11,4714.02 5181.88,4703.24 5188.02,4703.24 U74.10@5200.62,4690.65
NetR396_1: R396.1 U26.13 | length 116.4
  L1_Top Layer w11: U26.13@5707,10435.77 5780.5,10435.77 R396.1@5810.85,10466.12
NetR398_1: R398.1 U26.12 | length 106.4
  L1_Top Layer w11: U26.12@5707,10410.18 5804.79,10410.18 R398.1@5810.85,10404.12
NetR399_2: R399.2 U74.11 | length 69.6
  L1_Top Layer w6: R399.2@5137.13,4716.32 5147.77,4705.67 5163.9,4705.67 5174.11,4695.46 5174.11,4689.32 U74.11@5186.7,4676.73
NetR400_1: R400.1 U26.11 | length 121.4
  L1_Top Layer w11: U26.11@5707,10384.59 5768.38,10384.59 R400.1@5810.85,10342.12
NetR402_1: R402.1 U27.14 | length 125.5
  L1_Top Layer w11: R402.1@4808.31,9118.2 4868.93,9178.81 U27.14@4908.68,9178.81
NetR405_1: R405.1 U27.13 | length 110.4
  L1_Top Layer w11: R405.1@4808.31,9180.2 4839,9180.2 4863.2,9204.4 U27.13@4908.68,9204.4
NetR407_1: R407.1 U27.12 | length 105.4
  L1_Top Layer w11: R407.1@4808.31,9242.2 4820.52,9230 U27.12@4908.68,9230
NetR408_1: R408.1 R410.1 U75.5 | length 143.7
  L1_Top Layer w11: R408.1@3937.5,9284 4022.5,9284 4022.97,9283.53 U75.5@4081.01,9283.53
NetR409_1: R409.1 U27.11 | length 120.5
  L1_Top Layer w11: R409.1@4808.31,9304.2 4856.93,9255.59 U27.11@4908.68,9255.59
NetR416_1: R416.1 U28.4 | length 78
  L1_Top Layer w11: U28.4@6239.72,9629.51 6317.02,9629.51 R416.1@6317.5,9630
NetR417_2: R417.2 R418.1 U47.14 | length 262
  L1_Top Layer w10: R418.1@4003.63,11226.3 4051.52,11178.41 4051.52,11041.15 4071.84,11020.82 U47.14@4071.84,10992.59
NetR419_2: R419.2 R422.1 U50.14 | length 414
  L1_Top Layer w10: R422.1@1455.74,11223.3 1484.44,11252 1589.7,11252 1611.52,11230.18 1611.52,11036.95 1627.17,11021.3 U50.14@1627.17,10999.32
NetR421_1: R421.1 U29.14 | length 91.9
  L12_Bottom Layer w11: U29.14@5575.96,9214.61 5648.91,9214.61 R421.1@5662.32,9201.2
NetR423_1: R423.1 U29.13 | length 95.9
  L12_Bottom Layer w11: U29.13@5575.96,9240.2 5608.2,9240.2 5629,9261 5660.12,9261 R423.1@5662.32,9263.2
NetR424_1: R424.1 U29.12 | length 111
  L12_Bottom Layer w11: U29.12@5575.96,9265.8 5602.92,9265.8 R424.1@5662.32,9325.2
NetR432_1: R432.1 U30.14 | length 125.5
  L1_Top Layer w11: R432.1@3494.97,6594.22 3555.58,6654.83 U30.14@3595.33,6654.83
NetR433_1: R433.1 U31.14 | length 125.5
  L1_Top Layer w11: R433.1@3498.3,248.22 3558.91,308.84 U31.14@3598.66,308.84
NetR434_1: R434.1 U30.13 | length 110.4
  L1_Top Layer w11: R434.1@3494.97,6656.22 3519.17,6680.42 U30.13@3595.33,6680.42
NetR435_1: R435.1 U31.13 | length 110.4
  L1_Top Layer w11: R435.1@3498.3,310.22 3522.5,334.43 U31.13@3598.66,334.43
NetR436_1: R436.1 U30.12 | length 105.4
  L1_Top Layer w11: R436.1@3494.97,6718.22 3507.17,6706.01 U30.12@3595.33,6706.01
NetR437_1: R437.1 U31.12 | length 105.4
  L1_Top Layer w11: R437.1@3498.3,372.22 3510.5,360.02 U31.12@3598.66,360.02
NetR438_1: R438.1 U30.11 | length 120.5
  L1_Top Layer w11: R438.1@3494.97,6780.22 3496.58,6780.22 3545.19,6731.61 U30.11@3595.33,6731.61
NetR439_1: R439.1 U31.11 | length 120.5
  L1_Top Layer w11: R439.1@3498.3,434.22 3499.91,434.22 3548.52,385.61 U31.11@3598.66,385.61
NetR442_1: R442.1 U55.14 U57.14 U58.14 | length 9091
  L1_Top Layer w11: U58.14@3430.04,4149.77 3483.84,4149.77 v2(3484.18,4149.43) ; v2(4138.43,6930.26) 4152.07,6943.9 U55.14@4195.96,6943.9 ; U57.14@4199.29,597.9 4246.23,597.9 v2(4246.4,597.73) ; U55.14@4212.96,6943.9 4226.37,6943.9 4255.89,6973.42 4291.28,6973.42 R442.1@4334.36,7016.5
  L10_Signal Layer 2 w6.5: v2(4138.43,6930.26) 4138.43,6893.57 4867,6165 4867,5352 4756.22,5241.22 4756.22,4768.03 4383.19,4395 4114.9,4395 4046.63,4326.74 3661.49,4326.74 v2(3484.18,4149.43) 3400.21,4065.46 3400.21,3379.79 3575,3205 v1(4175,3205) ; v2(4246.4,597.73) 4113.59,730.54 4113.59,2380.59 4338,2605 v1(4338,3323)
  L12_Bottom Layer w11: v1(4175,3205) 4293,3323 v1(4338,3323)
NetR443_1: R443.1 U55.15 U57.15 U58.15 | length 9002.1
  L1_Top Layer w11: v2(3375.89,4124.51) 3376.23,4124.17 U58.15@3430.04,4124.17 ; v2(4117.18,6953.47) 4133.2,6969.49 U55.15@4195.96,6969.49 4227.01,6969.49 4271.61,7014.09 R443.1@4271.61,7016.31 ; v2(4142.17,623.49) U57.15@4199.29,623.49
  L10_Signal Layer 2 w6.5: v2(4117.18,6953.47) 4110,6946.29 4110,6904.32 4852.76,6161.56 4852.76,5358.76 4743.72,5249.72 4743.72,4773.21 4378.01,4407.5 4109.72,4407.5 4041.46,4339.24 3590.62,4339.24 v2(3375.89,4124.51) 3375.89,3353.07 3549.97,3179 v1(4178,3179) ; v2(4142.17,623.49) 4101.09,664.57 4101.09,2385.77 4305.5,2590.18 v1(4305.5,3250)
  L12_Bottom Layer w11: v2@4117.18,6947.83 v2(4117.18,6953.47) ; v1(4178,3179) 4234.5,3179 v1(4305.5,3250)
NetR455_1: R455.1 U32.14 | length 125.5
  L1_Top Layer w11: R455.1@3494.97,7038.93 3555.58,7099.54 U32.14@3595.33,7099.54
NetR456_1: R456.1 U33.14 | length 125.5
  L1_Top Layer w11: R456.1@3498.3,692.93 3558.91,753.55 U33.14@3598.66,753.55
NetR458_1: R458.1 U32.13 | length 110.4
  L1_Top Layer w11: R458.1@3494.97,7100.93 3519.17,7125.13 U32.13@3595.33,7125.13
NetR459_1: R459.1 U33.13 | length 110.4
  L1_Top Layer w11: R459.1@3498.3,754.93 3522.5,779.14 U33.13@3598.66,779.14
NetR461_1: R461.1 U32.12 | length 105.4
  L1_Top Layer w11: R461.1@3494.97,7162.93 3507.17,7150.72 U32.12@3595.33,7150.72
NetR462_1: R462.1 U33.12 | length 105.4
  L1_Top Layer w11: R462.1@3498.3,816.93 3510.5,804.73 U33.12@3598.66,804.73
NetR464_1: R464.1 U32.11 | length 120.5
  L1_Top Layer w11: R464.1@3494.97,7224.93 3496.58,7224.93 3545.19,7176.31 U32.11@3595.33,7176.31
NetR465_1: R465.1 U33.11 | length 120.5
  L1_Top Layer w11: R465.1@3498.3,878.93 3499.91,878.93 3548.52,830.32 U33.11@3598.66,830.32
NetR487_1: R487.1 R488.2 | length 66.7
  L1_Top Layer w20: R487.1@4863.82,11167.31 4929.83,11167.31 R488.2@4930.32,11167.8
NetR490_1: R490.1 R491.1 R492.2 U39.6 | length 225.8
  L12_Bottom Layer w10: 2827.89,11309.86 2827.93,11309.83 2893.28,11309.83 U39.6@2893.32,11309.86
  L12_Bottom Layer w11: R492.2@2782.75,11336.31 2801.45,11336.31 2827.89,11309.86
  L12_Bottom Layer w20: R492.2@2782.75,11336.31 2782.75,11283.61 R490.1@2785.04,11281.33 2785.04,11233.31 R491.1@2784.82,11233.09
NetR494_1: R494.1 U41.2 | length 84.8
  L1_Top Layer w10: U41.2@3234.87,10866.68 3234.87,10798.17 R494.1@3246.35,10786.68
NetR495_2: R495.2 U41.11 | length 131.1
  L1_Top Layer w10: U41.11@3293.92,10996.6 3337.22,10996.6 R495.2@3399.3,11058.68
NetR496_2: R496.2 U41.10 | length 95.4
  L1_Top Layer w10: U41.10@3319.51,10971.01 3361.63,10971.01 R496.2@3399.3,11008.68
NetR497_2: R497.2 U41.9 | length 83.2
  L1_Top Layer w10: U41.9@3319.51,10951.32 3390.94,10951.32 R497.2@3399.3,10959.68
NetR498_2: R498.2 U41.7 | length 81.3
  L1_Top Layer w10: U41.7@3319.51,10911.95 3399.02,10911.95 R498.2@3400.3,10910.68
NetR499_2: R499.2 U41.6 | length 93
  L1_Top Layer w10: U41.6@3319.51,10892.27 3370.71,10892.27 R499.2@3400.3,10862.68
NetR500_2: R500.2 U41.5 | length 127.9
  L1_Top Layer w10: U41.5@3293.92,10866.68 3348.3,10866.68 R500.2@3400.3,10814.68
NetR501_1: R501.1 R502.2 R504.2 U42.6 | length 223.8
  L12_Bottom Layer w10: 2003,11309.82 U42.6@2026.32,11309.82
  L12_Bottom Layer w11: R504.2@1913.41,11332.69 1939.32,11332.69 1962.18,11309.82 2003,11309.82
  L12_Bottom Layer w20: R504.2@1913.41,11332.69 1913.41,11285.91 R501.1@1918.04,11281.28 1918.04,11233.37 R502.2@1918.13,11233.28
NetR503_1: R503.1 U42.7 | length 115.5
  L1_Top Layer w10: R503.1@1994,11250.87 v1(1994,11333)
  L12_Bottom Layer w11: v1(1994,11333) 1996.41,11335.41 U42.7@2026.32,11335.41
NetR505_2: R505.2 TP78.1 U44.4 | length 282.9
  L1_Top Layer w10: R505.2@2373.13,10640.92 2375.25,10640.92 TP78.1@2453.2,10718.86 2453.2,10799.55 2400.41,10852.34 U44.4@2400.41,10867.54
NetR506_1: R506.1 U44.2 | length 84.8
  L1_Top Layer w10: U44.2@2361.04,10867.54 2361.04,10799.02 R506.1@2372.53,10787.54
NetR507_2: R507.2 U44.11 | length 131.1
  L1_Top Layer w10: U44.11@2420.09,10997.46 2463.39,10997.46 R507.2@2525.47,11059.54
NetR508_2: R508.2 U44.10 | length 95.4
  L1_Top Layer w10: U44.10@2445.69,10971.87 2487.8,10971.87 R508.2@2525.47,11009.54
NetR509_2: R509.2 U44.9 | length 83.2
  L1_Top Layer w10: U44.9@2445.69,10952.18 2517.12,10952.18 R509.2@2525.47,10960.54
NetR510_2: R510.2 U44.7 | length 81.3
  L1_Top Layer w10: U44.7@2445.69,10912.81 2525.2,10912.81 R510.2@2526.47,10911.54
NetR511_2: R511.2 U44.6 | length 93
  L1_Top Layer w10: U44.6@2445.69,10893.13 2496.88,10893.13 R511.2@2526.47,10863.54
NetR512_2: R512.2 U44.5 | length 127.9
  L1_Top Layer w10: U44.5@2420.09,10867.54 2474.47,10867.54 R512.2@2526.47,10815.54
NetR514_1: R514.1 R515.1 R516.2 U45.6 | length 248.2
  L12_Bottom Layer w10: 3663.5,11343.03 3691.38,11315.16 3741.16,11315.16 U45.6@3742.33,11313.99
  L12_Bottom Layer w11: R516.2@3621.17,11343.03 3663.5,11343.03
  L12_Bottom Layer w20: R515.1@3616.87,11229.79 3621.17,11234.09 R514.1@3621.17,11285.46 R516.2@3621.17,11343.03
NetR517_2: R517.2 TP79.1 U47.4 | length 280.8
  L1_Top Layer w10: R517.2@4086.06,10636.06 TP79.1@4164,10714 4164,10794.68 4111.21,10847.47 U47.4@4111.21,10862.67
NetR518_1: R518.1 U47.2 | length 84.8
  L1_Top Layer w10: U47.2@4071.84,10862.67 4071.84,10794.16 R518.1@4083.33,10782.67
NetR519_2: R519.2 U47.11 | length 131.1
  L1_Top Layer w10: U47.11@4130.9,10992.59 4174.19,10992.59 R519.2@4236.27,11054.67
NetR520_2: R520.2 U47.10 | length 95.4
  L1_Top Layer w10: U47.10@4156.49,10967 4198.6,10967 R520.2@4236.27,11004.67
NetR521_2: R521.2 U47.9 | length 83.2
  L1_Top Layer w10: U47.9@4156.49,10947.32 4227.92,10947.32 R521.2@4236.27,10955.67
NetR522_2: R522.2 U47.7 | length 81.3
  L1_Top Layer w10: U47.7@4156.49,10907.95 4236,10907.95 R522.2@4237.27,10906.67
NetR523_2: R523.2 U47.6 | length 93
  L1_Top Layer w10: U47.6@4156.49,10888.26 4207.68,10888.26 R523.2@4237.27,10858.67
NetR524_2: R524.2 U47.5 | length 127.9
  L1_Top Layer w10: U47.5@4130.9,10862.67 4185.27,10862.67 R524.2@4237.27,10810.67
NetR526_1: R526.1 R527.1 R528.2 U48.6 | length 266.7
  L12_Bottom Layer w10: R528.2@1203.63,11345.9 1241.36,11345.9 1276.06,11311.2 1325.37,11311.2 U48.6@1326.53,11310.03
  L12_Bottom Layer w20: R528.2@1203.63,11345.9 1203.63,11283.25 R526.1@1205.37,11281.5 1205.37,11238.47 R527.1@1220.04,11223.81
NetR529_2: R529.2 TP80.1 U50.4 | length 282.9
  L1_Top Layer w10: R529.2@1639.25,10642.79 1641.38,10642.79 TP80.1@1719.33,10720.73 1719.33,10801.41 1666.54,10854.2 U50.4@1666.54,10869.4
NetR530_1: R530.1 U50.2 | length 84.8
  L1_Top Layer w10: U50.2@1627.17,10869.4 1627.17,10800.89 R530.1@1638.65,10789.4
NetR533_1: R533.1 R534.1 R535.2 U51.6 | length 239
  L12_Bottom Layer w15: R533.1@502.37,11247.92 R534.1@502.37,11296.92 502.75,11297.3 R535.2@502.75,11350.33 562.59,11350.33 601.07,11311.85 U51.6@623.22,11311.85
NetR542_1: R542.1 U34.6 | length 114.7
  L1_Top Layer w10: U34.6@5520.39,9834.76 5579.58,9834.76 v2(5579.87,9834.47)
  L12_Bottom Layer w10: R542.1@5525.38,9832.97 5526.88,9834.47 v2(5579.87,9834.47)
NetR543_2: R543.2 U34.14 | length 124.6
  L1_Top Layer w10: U34.14@5520.39,9992.24 5598.66,9992.24 R543.2@5631.39,10024.97
NetR545_1: R545.1 R547.1 U56.4 | length 148.6
  L1_Top Layer w11: U56.4@5341.88,9334.25 5342.88,9335.25 R545.1@5342.88,9410.97 R547.1@5342.88,9482.47
NetR551_1: R551.1 U59.3 | length 147.3
  L12_Bottom Layer w10: v3@2381.32,8627.43 2381.32,8714.05 cw(c2400.64,8714.05) 2386.98,8727.71 ccw(c2368.86,8745.82) 2394.48,8745.82 U59.3@2394.49,8771.21
  other v3: 2381.27,8627.43
NetR552_1: R552.1 U59.2 | length 147.3
  L12_Bottom Layer w10: U59.2@2274.48,8771.21 2274.49,8745.82 ccw(c2300.1,8745.82) 2281.99,8727.71 cw(c2268.33,8714.05) 2287.65,8714.05 v3@2287.65,8627.43
  other v3: 2288.27,8627.43
NetR560_1: R560.1 U60.3 | length 147.3
  L12_Bottom Layer w10: U60.3@2275.24,7678.98 2275.24,7704.37 cw(c2300.86,7704.37) 2282.74,7722.49 ccw(c2269.09,7736.15) 2288.4,7736.15 v3@2288.4,7822.77
  other v3: 2289.08,7822.77
NetR561_1: R561.1 U60.2 | length 147.3
  L12_Bottom Layer w10: v3(2382.08,7822.77) 2382.08,7736.15 ccw(c2401.39,7736.14) 2387.74,7722.49 cw(c2369.62,7704.37) 2395.24,7704.37 U60.2@2395.24,7678.98
NetR569_1: R569.1 U61.3 | length 147.3
  L12_Bottom Layer w10: v3(2384.32,2281.8) 2384.32,2368.43 cw(c2403.63,2368.43) 2389.97,2382.08 ccw(c2371.86,2400.2) 2397.48,2400.2 U61.3@2397.48,2425.59
NetR570_1: R570.1 U61.2 | length 147.3
  L12_Bottom Layer w10: U61.2@2277.48,2425.59 2277.48,2400.2 ccw(c2303.1,2400.2) 2284.98,2382.08 cw(c2271.32,2368.43) 2290.64,2368.43 v3(2290.64,2281.8)
NetR578_1: R578.1 U62.3 | length 147.3
  L12_Bottom Layer w10: U62.3@2279.42,1333.02 2279.42,1358.41 cw(c2305.04,1358.41) 2286.92,1376.53 ccw(c2273.27,1390.18) 2292.58,1390.18 v3(2292.58,1476.8)
NetR579_1: R579.1 U62.2 | length 147.3
  L12_Bottom Layer w10: v3(2386.26,1476.8) 2386.26,1390.18 ccw(c2405.57,1390.18) 2391.92,1376.53 cw(c2373.8,1358.41) 2399.42,1358.41 U62.2@2399.42,1333.02
NetR586_1: R586.1 R587.2 R635.1 U63.1 | length 5082.3
  L1_Top Layer w11: v2(6028,7472) 6073,7472 6105.11,7439.89 R587.2@6105.11,7400.63 ; R586.1@6055.48,8146.01 6055.48,8125.63 6067.11,8114.01 v1(6069.11,8114.01)
  L4_Signal Layer 1 w5.5: v2(6028,7472) 6069.11,7513.11 v1(6069.11,8114.01)
  L10_Signal Layer 2 w6.5: v2(6028,7472) 6078,7422 6078,7052 5593,6567 5593,5615 5912,5296 5912,3956 6053.31,3814.68 v2(6053.31,3763.32)
  L12_Bottom Layer w11: U63.1@5926.76,3745.69 5977.27,3745.69 R635.1@5994.9,3763.32 v2(6053.31,3763.32)
NetR588_1: R588.1 U63.4 | length 51.8
  L12_Bottom Layer w11: R588.1@5837.38,3643 5838.18,3643.8 U63.4@5838.18,3694.51
NetR589_2: R589.2 R590.2 R634.1 U63.2 | length 4035.5
  L1_Top Layer w11: v2(6051.21,1258.71) 6108.75,1201.17 R589.2@6108.75,1057.43 ; R590.2@6059.13,1802.81 6059.13,1782.43 6070.75,1770.81 v1(6072.75,1770.81)
  L4_Signal Layer 1 w5.5: v2(6051.21,1258.71) 6072.75,1280.24 v1(6072.75,1770.81) 6152.94,1851 6552,1851 6643,1942 6643,2472.78 6809.25,2639.03 6809.25,3346.9 6694.15,3462 6121.31,3462 6053.31,3530 v2(6053.31,3698.31)
  L12_Bottom Layer w11: U63.2@5926.76,3720.1 5973.11,3720.1 R634.1@5994.9,3698.31 v2(6053.31,3698.31)
NetR591_1: R591.1 U34.44 | length 158.3
  L1_Top Layer w11: v2(4978,9783) 5010.07,9815.07 U34.44@5083.38,9815.07
  L12_Bottom Layer w11: v2(4978,9783) 5015.5,9783 R591.1@5017,9781.5
NetR636_1: R636.1 U64.4 | length 60.1
  L12_Bottom Layer w11: R636.1@5782.62,3428 5782.85,3428.23 U64.4@5842.61,3428.23
NetR646_2: R646.2 U65.2 | length 94.1
  L1_Top Layer w11: R646.2@1805.01,9036.66 1805.01,9044.86 cw(c1871.22,9044.86) 1824.4,9091.68 cw(c1850.61,9065.47) 1850.61,9102.54 U65.2@1855.38,9102.54
NetR647_2: R647.2 U65.8 | length 94.1
  L1_Top Layer w11: U65.8@1962.46,9102.54 1967.23,9102.54 cw(c1967.23,9065.47) 1993.44,9091.68 cw(c1946.63,9044.86) 2012.83,9044.86 R647.2@2012.83,9036.66
NetR648_2: R648.2 R649.1 | length 155.9
  L1_Top Layer w11: R648.2@1830.99,9010.68 R649.1@1986.85,9010.68
NetR650_2: R650.2 U66.2 | length 94.1
  L1_Top Layer w11: R650.2@1805.01,8832.72 1805.01,8824.52 ccw(c1871.22,8824.52) 1824.4,8777.7 ccw(c1850.61,8803.91) 1850.61,8766.84 U66.2@1855.38,8766.84
NetR651_2: R651.2 U66.8 | length 94.1
  L1_Top Layer w11: U66.8@1962.46,8766.84 1967.23,8766.84 ccw(c1967.23,8803.91) 1993.44,8777.7 ccw(c1946.63,8824.52) 2012.83,8824.52 R651.2@2012.83,8832.72
NetR652_2: R652.2 R653.1 | length 155.9
  L1_Top Layer w11: R652.2@1830.99,8858.7 R653.1@1986.85,8858.7
NetR654_2: R654.2 U67.8 | length 94.1
  L1_Top Layer w11: U67.8@1966.08,7680.46 1970.85,7680.46 cw(c1970.85,7643.39) 1997.06,7669.6 cw(c1950.24,7622.78) 2016.45,7622.78 R654.2@2016.45,7614.58
NetR655_2: R655.2 U67.2 | length 94.1
  L1_Top Layer w11: R655.2@1808.63,7614.58 1808.63,7622.78 cw(c1874.83,7622.78) 1828.02,7669.6 cw(c1854.23,7643.39) 1854.23,7680.46 U67.2@1859,7680.46
NetR656_2: R656.2 R657.1 | length 155.9
  L1_Top Layer w11: R656.2@1834.61,7588.6 R657.1@1990.47,7588.6
NetR658_2: R658.2 U68.2 | length 94.1
  L1_Top Layer w11: R658.2@1808.63,7410.64 1808.63,7402.44 ccw(c1874.83,7402.44) 1828.02,7355.62 ccw(c1854.23,7381.83) 1854.23,7344.76 U68.2@1859,7344.76
NetR659_2: R659.2 U68.8 | length 94.1
  L1_Top Layer w11: U68.8@1966.08,7344.76 1970.85,7344.76 ccw(c1970.85,7381.83) 1997.06,7355.62 ccw(c1950.24,7402.44) 2016.45,7402.44 R659.2@2016.45,7410.64
NetR660_2: R660.2 R661.1 | length 155.9
  L1_Top Layer w11: R660.2@1834.61,7436.62 R661.1@1990.47,7436.62
NetR662_2: R662.2 U69.8 | length 94.1
  L1_Top Layer w11: U69.8@1966.08,2756.86 1970.85,2756.86 cw(c1970.85,2719.79) 1997.06,2746 cw(c1950.24,2699.18) 2016.45,2699.18 R662.2@2016.45,2690.98
NetR663_2: R663.2 U69.2 | length 94.1
  L1_Top Layer w11: R663.2@1808.63,2690.98 1808.63,2699.18 cw(c1874.83,2699.18) 1828.02,2746 cw(c1854.23,2719.79) 1854.23,2756.86 U69.2@1859,2756.86
NetR664_2: R664.2 R665.1 | length 155.9
  L1_Top Layer w11: R664.2@1834.61,2665 R665.1@1990.47,2665
NetR666_2: R666.2 U70.2 | length 94.1
  L1_Top Layer w11: R666.2@1808.63,2487.04 1808.63,2478.84 ccw(c1874.83,2478.84) 1828.02,2432.02 ccw(c1854.23,2458.23) 1854.23,2421.16 U70.2@1859,2421.16
NetR667_2: R667.2 U70.8 | length 94.1
  L1_Top Layer w11: U70.8@1966.08,2421.16 1970.85,2421.16 ccw(c1970.85,2458.23) 1997.06,2432.02 ccw(c1950.24,2478.84) 2016.45,2478.84 R667.2@2016.45,2487.04
NetR668_2: R668.2 R669.1 | length 155.9
  L1_Top Layer w11: R668.2@1834.61,2513.02 R669.1@1990.47,2513.02
NetR670_2: R670.2 U71.8 | length 94.1
  L1_Top Layer w11: U71.8@1966.08,1337.76 1970.85,1337.76 cw(c1970.85,1300.69) 1997.06,1326.9 cw(c1950.24,1280.08) 2016.45,1280.08 R670.2@2016.45,1271.88
NetR671_2: R671.2 U71.2 | length 94.1
  L1_Top Layer w11: R671.2@1808.63,1271.88 1808.63,1280.08 cw(c1874.83,1280.08) 1828.02,1326.9 cw(c1854.23,1300.69) 1854.23,1337.76 U71.2@1859,1337.76
NetR672_2: R672.2 R673.1 | length 155.9
  L1_Top Layer w11: R672.2@1834.61,1245.9 R673.1@1990.47,1245.9
NetR674_2: R674.2 U72.2 | length 94.1
  L1_Top Layer w11: R674.2@1808.63,1067.94 1808.63,1059.74 ccw(c1874.83,1059.74) 1828.02,1012.92 ccw(c1854.23,1039.13) 1854.23,1002.06 U72.2@1859,1002.06
NetR675_2: R675.2 U72.8 | length 94.1
  L1_Top Layer w11: U72.8@1966.08,1002.06 1970.85,1002.06 ccw(c1970.85,1039.13) 1997.06,1012.92 ccw(c1950.24,1059.74) 2016.45,1059.74 R675.2@2016.45,1067.94
NetR676_2: R676.2 R677.1 | length 155.9
  L1_Top Layer w11: R676.2@1834.61,1093.92 R677.1@1990.47,1093.92
NetRMPCLK1_1: RMPCLK1.1 U19.30 | length 361.6
  L1_Top Layer w11: v2(2061.28,6253.92) 2126.2,6253.92 U19.30@2126.28,6253.99
  L12_Bottom Layer w9.84: RMPCLK1.1@1892.22,6452.81 1892.22,6375.81 2014.12,6253.92 v2(2061.28,6253.92)
NetRMPCLK2_1: RMPCLK2.1 U21.30 | length 352.5
  L1_Top Layer w11: U21.30@2425.34,3563.98 2425.41,3564.06 v2(2490.34,3564.06)
  L12_Bottom Layer w9.84: v2(2490.34,3564.06) 2537.5,3564.06 2637.47,3464.09 RMPCLK2.1@2637.47,3387.09 ; RMPCLK2.1@2659.39,3365.17 RMPCLK2.1@2659.39,3387.09
NetRMPDIR1_1: RMPDIR1.1 U19.32 | length 396.1
  L1_Top Layer w11: v2(2032.28,6222.92) 2046.48,6208.71 U19.32@2100.68,6208.71
  L12_Bottom Layer w9.84: RMPDIR1.1@1762.22,6347.81 1877.22,6347.81 2002.12,6222.92 v2(2032.28,6222.92)
NetRMPDIR2_1: RMPDIR2.1 U21.32 | length 387
  L1_Top Layer w11: U21.32@2450.93,3609.26 2505.13,3609.26 v2(2519.34,3595.06)
  L12_Bottom Layer w9.84: v2(2519.34,3595.06) 2549.5,3595.06 2652.47,3492.09 RMPDIR2.1@2767.47,3492.09 ; RMPDIR2.1@2767.47,3470.17 RMPDIR2.1@2789.39,3470.17
NetU34_27: U34.27 U54.2 | length 250.9
  L1_Top Layer w11: U54.2@5138.02,10245.97 5138.71,10245.28 5241.06,10245.28 5252.67,10233.67 U34.27@5252.67,10102.47
NetU34_29: U34.29 U54.1 | length 151.2
  L1_Top Layer w11: U54.1@5138.02,10208.57 5161.77,10208.57 5213.3,10157.04 U34.29@5213.3,10102.47
NetU74_1: U74.1 U74.4 U74.5 | length 368
  L1_Top Layer w11: U74.1@5250.73,4584.86 5289,4546.59 v2(5289,4501) ; U74.4@5292.49,4626.51 U74.4@5292.49,4626.62 ; U74.5@5292.49,4662.81 5303,4652.29 5303,4637.13 U74.4@5292.49,4626.62 ; v2(5376.35,4588.35) 5330.76,4588.35 U74.4@5292.49,4626.62
  L12_Bottom Layer w11: v2(5289,4501) v2(5376.35,4588.35)
OSCI: C739.1 U34.2 Y2.1 | length 432.1
  L1_Top Layer w6: U34.2@5520.39,9756.02 5561.82,9756.02 5566.16,9760.36 5580.31,9760.36 5590.31,9750.36 5590.31,9712.88 5605.49,9697.69 5608.72,9694.47 5647.18,9694.47 5671.18,9670.47 C739.1@5695.88,9670.47 5720.58,9670.47 5743.59,9693.47 5800.31,9693.47 5815.88,9677.89 Y2.1@5815.88,9618.26
OSCIN+: C407.2 R319.2 R321.2 R324.2 | length 975.6
  L1_Top Layer w10: C407.2@5132.28,5028.8 5185.31,5028.8 R319.2@5185.67,5029.16 R321.2@5234.67,5029.16 5243.87,5038.35 cw(c5255.17,5027.05) 5255.17,5043.03 5304.16,5043.03 ccw(c5304.16,5143.03) 5374.88,5072.32 5383.08,5080.52 5512.1,5209.54 ccw(c5421.59,5300.05) 5549.59,5300.05 5549.59,5321.34 cw(c5649.59,5321.34) 5578.87,5392.05 R324.2@5809.09,5622.27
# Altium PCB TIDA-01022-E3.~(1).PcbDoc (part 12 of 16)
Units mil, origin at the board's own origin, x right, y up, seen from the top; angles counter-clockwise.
Board outline 6929.13 x 11614.17 mil, 12 copper layers (L1_Top Layer, L2_GND, L3_GND, L4_Signal Layer 1, L5_GND, L6_PWR, L7_GND/PWR, L8_PWR, L9_GND/PWR, L10_Signal Layer 2, L11_GND, L12_Bottom Layer), stack 64.6 mil thick; 1733 components, 993 nets, 5987 pads, 3555 vias.

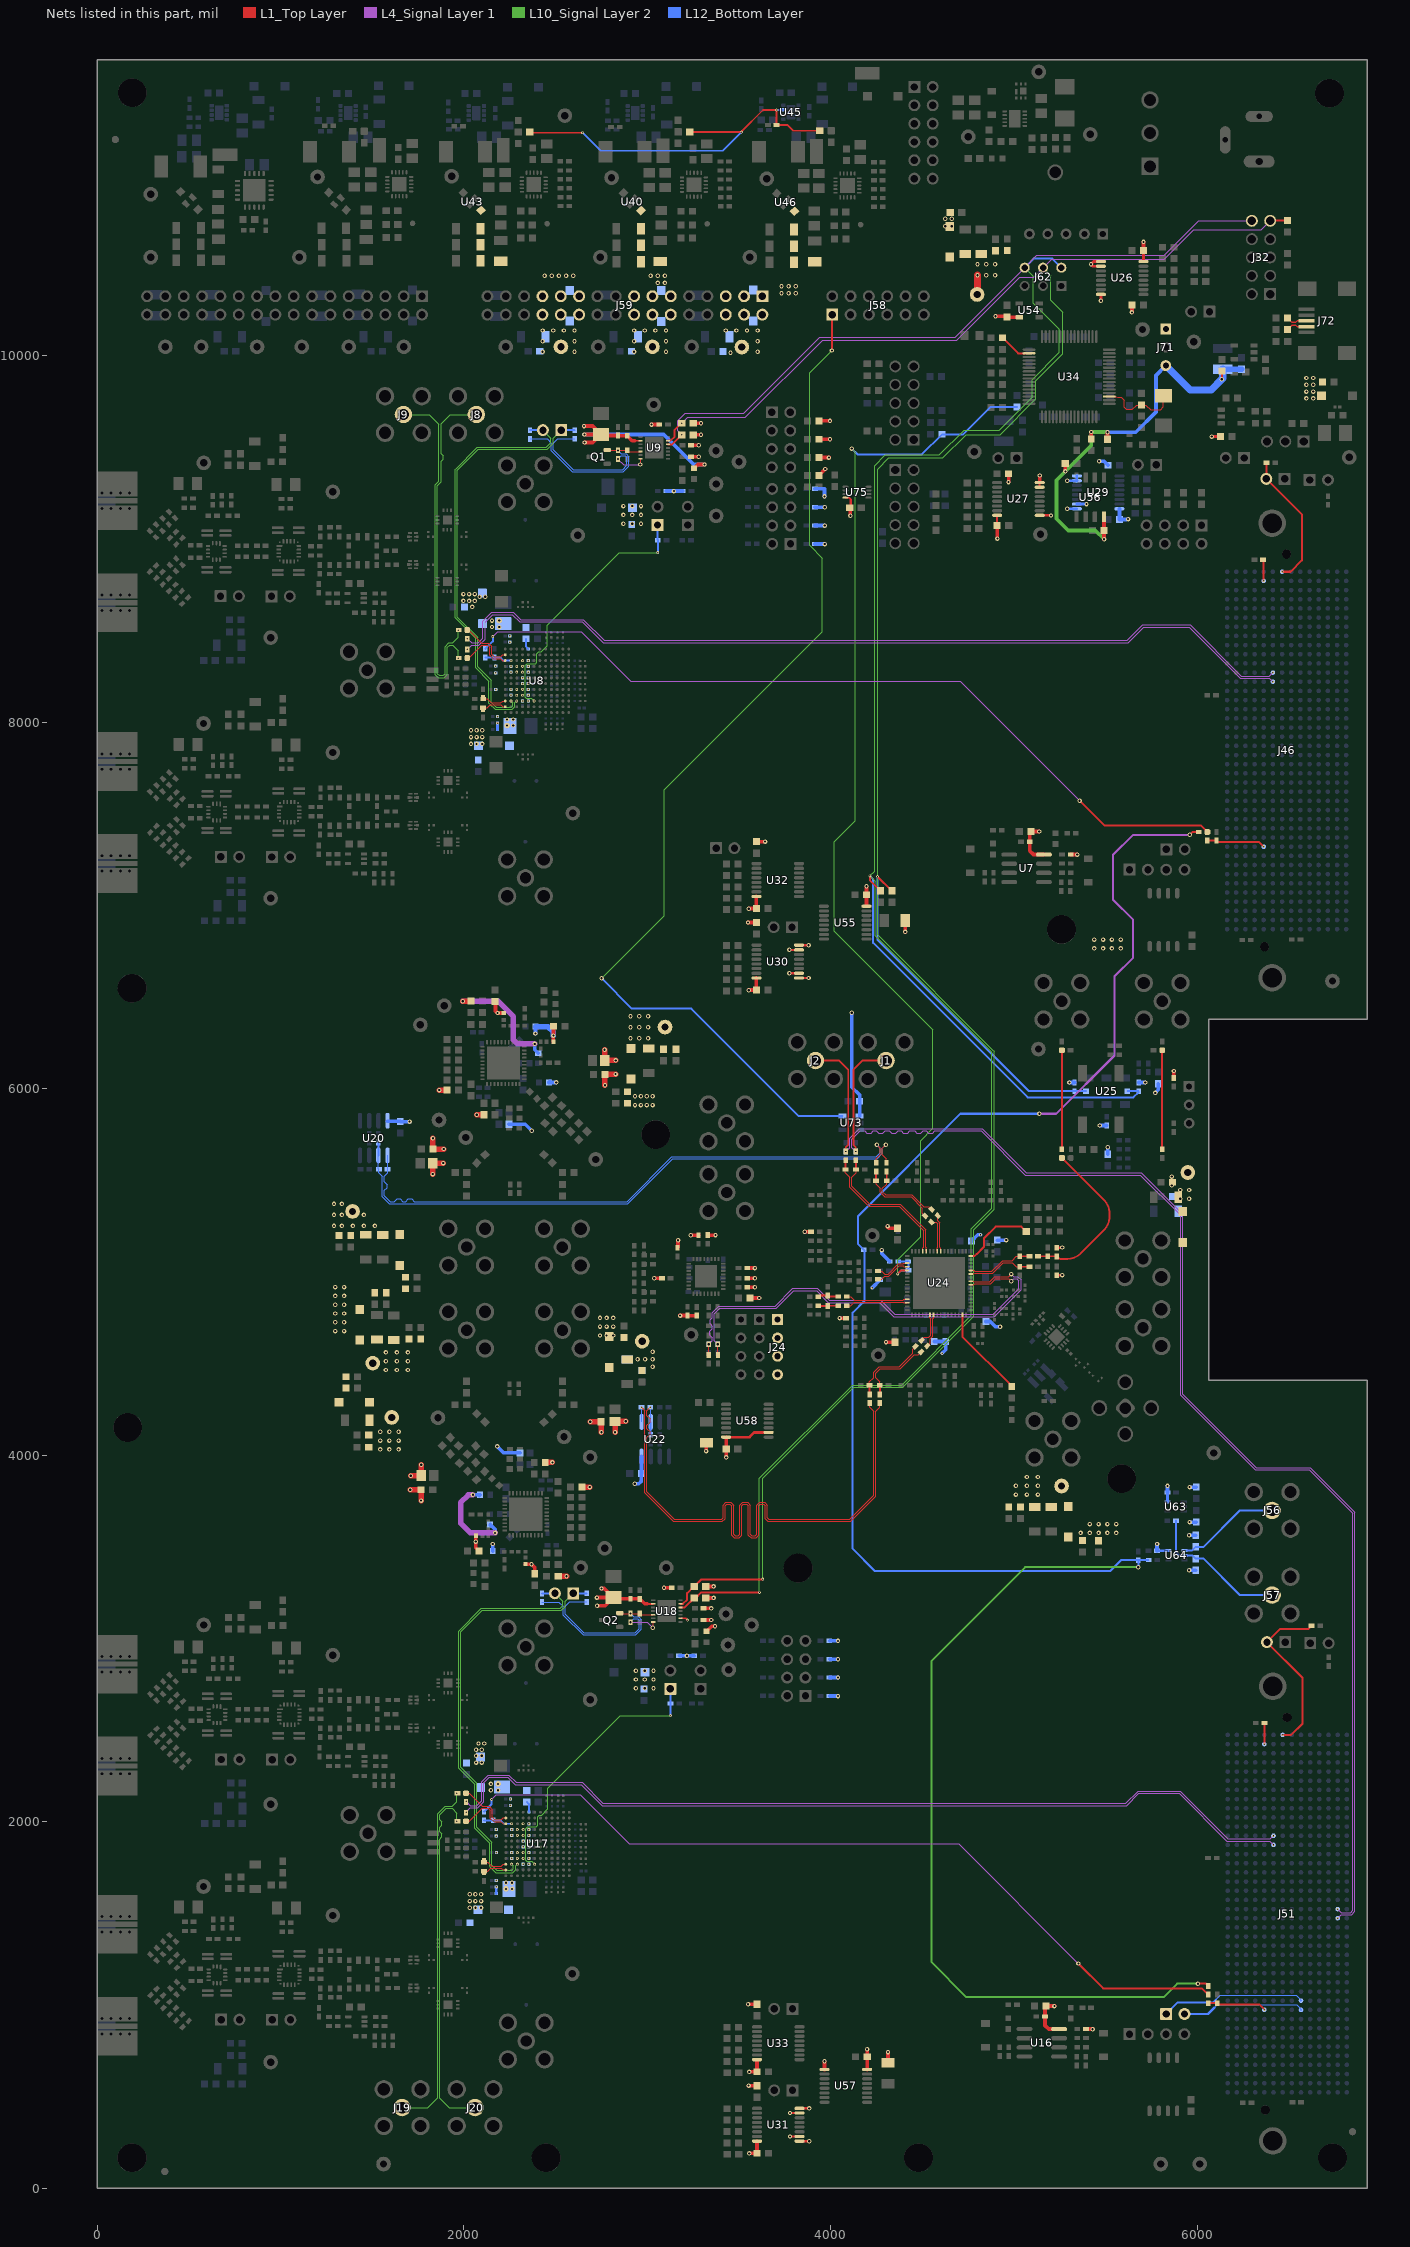
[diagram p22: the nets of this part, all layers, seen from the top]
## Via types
v1: diameter 16, hole 8, L1_Top Layer to L12_Bottom Layer, tented both sides, 1686 vias
v2: diameter 24, hole 12, L1_Top Layer to L12_Bottom Layer, tented both sides, 1590 vias
v3: diameter 20, hole 10, L1_Top Layer to L12_Bottom Layer, 279 vias

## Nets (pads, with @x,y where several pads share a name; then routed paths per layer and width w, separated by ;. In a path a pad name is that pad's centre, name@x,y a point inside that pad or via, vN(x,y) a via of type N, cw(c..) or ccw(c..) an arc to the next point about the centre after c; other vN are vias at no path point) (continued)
OSCIN-: C408.2 C410.2 R327.2 R340.2 R341.2 | length 930.7
  L1_Top Layer w10: C408.2@5132.28,5085.8 5185.49,5085.8 R341.2@5185.67,5085.62 5233.96,5085.62 R340.2@5234.67,5084.91 5243.87,5075.72 ccw(c5255.17,5087.02) 5255.17,5071.03 5292.57,5071.03 ccw(c5292.57,5171.03) 5363.28,5100.32 5492.3,5229.34 ccw(c5421.59,5300.05) 5521.59,5300.05 5521.59,5321.34 ccw(c5421.59,5321.34) 5492.3,5392.05 C410.2@5262.08,5622.27
OSCIN_N: C408.1 C409.2 U24.44 | length 356.1
  L1_Top Layer w6: U24.44@4764.49,5008.62 4782.3,5008.62 4786.64,5004.28 4880.17,5004.28 4938.19,5062.3 4990.97,5062.3 5013.85,5085.17 C409.2@5031.66,5085.17 ; C408.1@5084.42,5085.17 C408.1@5085.04,5085.8
  L1_Top Layer w10: C409.2@5031.66,5085.17 C408.1@5084.42,5085.17
OSCIN_P: C406.2 C407.1 U24.43 | length 356
  L1_Top Layer w6: U24.43@4764.49,4988.94 4782.3,4988.94 4786.64,4993.28 4884.73,4993.28 4942.74,5051.3 4990.97,5051.3 5013.85,5028.42 C406.2@5031.66,5028.42 ; C407.1@5084.66,5028.42 C407.1@5085.04,5028.8
  L1_Top Layer w10: C406.2@5031.66,5028.42 C407.1@5084.66,5028.42
OSCO: C740.1 U34.3 Y2.2 | length 432.9
  L1_Top Layer w6: U34.3@5520.39,9775.7 5561.82,9775.7 5566.16,9771.36 5584.86,9771.36 5601.31,9754.92 5601.31,9717.44 5613.27,9705.47 5647.18,9705.47 5671.18,9729.47 C740.1@5695.88,9729.47 5720.58,9729.47 5745.59,9704.47 5800.31,9704.47 5815.88,9720.05 Y2.2@5815.88,9779.68
OSCOUT_N: R257.2 R266.2 R270.1 U24.41 | length 2438.1
  L1_Top Layer w6: v2(3384.5,4605.67) 3384.5,4548.41 R266.2@3385.75,4547.16 ; U24.41@4764.49,4949.57 4782.3,4949.57 4786.64,4945.22 4868.11,4945.22 4896.39,4973.5 4971.43,4973.5 v2(4985.93,4988)
  L4_Signal Layer 1 w4.9: v2(3384.5,4605.67) 3366,4624.17 3366,4771 3396,4801 3702.97,4801 3799.72,4897.75 3923.25,4897.75 3988,4833 4268.03,4833 4345.03,4756 4891.97,4756 5039,4903.03 5039,4957.22 5021.72,4974.5 4999.43,4974.5 v2(4985.93,4988)
OSCOUT_P: R253.2 R261.2 R263.1 U24.40 | length 2436.4
  L1_Top Layer w6: v2(3335.5,4605.67) 3335.5,4547.41 R261.2@3335.75,4547.16 ; U24.40@4764.49,4929.88 4782.3,4929.88 4786.64,4934.22 4872.67,4934.22 4900.94,4962.5 4972.43,4962.5 v2(4985.93,4949)
  L4_Signal Layer 1 w4.9: v2(3335.5,4605.67) 3354,4624.17 3354,4642 3342,4654 3342,4677 3354,4689 3354,4705 3343,4716 3343,4740 3354,4751 3354,4775.97 3391.03,4813 3698,4813 3794.75,4909.75 3928.22,4909.75 3992.97,4845 4273,4845 4350,4768 4887,4768 5027,4908 5027,4952.25 5016.75,4962.5 4999.43,4962.5 v2(4985.93,4949)
OUT_N: R326.1 R327.1 R356.2 | length 540.3
  L1_Top Layer w11: R327.1@5262.08,5669.52 R326.1@5262.04,6209.82
OUT_P: R323.1 R324.1 R357.2 | length 540.3
  L1_Top Layer w11: R324.1@5809.09,5669.52 R323.1@5809.06,6209.82
PD1: J6.1 R65.2 U8.K6 | length 1452.5
  L10_Signal Layer 2 w3.5: v1(2382.42,8114.86) 2366.67,8130.61 2340.06,8130.61 2334.67,8136 2334.67,8309.5 2344.5,8319.33 2391.01,8319.33 2398.08,8326.41 2398.08,8373.23 2407.67,8382.82 2420.33,8382.82 2453.67,8416.16 2453.67,8465.67
  L10_Signal Layer 2 w6.5: 2453.67,8465.67 2453.67,8529.35 2848.32,8924 v1(3057,8924)
  L12_Bottom Layer w11: J6.1@3056.08,9074.99 3056.08,8993.51 R65.2@3057.68,8991.91 3057.68,8924.68 v1(3057,8924)
PD2: J17.1 R146.2 U17.K6 | length 1512.5
  L10_Signal Layer 2 w3.5: v1(2385.75,1768.86) 2370,1784.61 2343.39,1784.61 2338,1790 2338,1963.51 2347.83,1973.34 2394.34,1973.34 2401.41,1980.41 2401.41,2027.24 2411,2036.83 2423.66,2036.83 2457,2070.16 2457,2119.67
  L10_Signal Layer 2 w6.5: 2457,2119.67 2457,2183.36 2852.64,2579 v1(3126,2579)
  L12_Bottom Layer w11: v1(3126,2579) 3126.65,2579.65 R146.2@3126.65,2645.49 ; R146.2@3126.01,2646.14 J17.1@3126.01,2725.21
PG_3P3V: R386.2 R388.2 R418.2 R513.1 U45.7 | length 2129.5
  L1_Top Layer w10: R388.2@2358.99,11219.5 2363.49,11215 v1(2647.28,11215) ; R386.2@3231.45,11220.04 3512.08,11220.04 3631.31,11339.27 v1(3705.27,11339.27) R513.1@3705.27,11257.14 3766.07,11257.14 3796.9,11226.3 R418.2@3940.63,11226.3
  L12_Bottom Layer w10: v1(2647.28,11215) 2745.28,11117 3411.12,11117 v1(3513.12,11219)
  L12_Bottom Layer w11: v1(3705.27,11339.27) 3705.58,11339.59 U45.7@3742.33,11339.59
PG_RX1: J45.2 J46.F1 R473.1 | length 748.3
  L1_Top Layer w11: R473.1@6378.77,9415.54 6377.4,9414.16 J45.2@6377.4,9326.54 6571.27,9132.67 6571.27,8881.88 6509.4,8820.01 v1(6463.11,8820.01)
PG_RX2: J50.2 J51.F1 R478.1 | length 938.9
  L1_Top Layer w11: v1(6466.44,2474.01) 6512.73,2474.01 6574.6,2535.88 6574.6,2786.67 J50.2@6380.73,2980.54 6451.18,3051 6605.24,3051 R478.1@6623.97,3069.74
PRSNT_M2C_L_1: J46.H2 R476.2 | length 117.4
  L1_Top Layer w11: R476.2@6359.73,8886.01 6363.11,8882.63 v1(6363.11,8770.01)
PRSNT_M2C_L_2: J51.H2 R481.2 | length 112.6
  L1_Top Layer w11: v1@6366.75,2426.81 R481.2@6366.75,2539.43
  other v1: 6366.44,2424.01
PWR_SYNC: J58.1 U73.5 | length 5823.5
  L1_Top Layer w11: v2(4007,10027) 4007,10221 J58.1@4009,10223
  L10_Signal Layer 2 w6.5: v2(2751,6602) 3091.23,6942.23 3091.23,7630.23 3955,8494 3955,8895 3886.36,8963.64 3886.36,9906.36 v2(4007,10027)
  L12_Bottom Layer w11: v2(2751,6602) 2916,6437 3240,6437 3826.6,5850.4 U73.5@4064.26,5850.4
RESET: C423.2 R228.2 R368.2 R591.2 R603.1 U24.5 | length 6118.2
  L1_Top Layer w9.84: 4400,5008.62 U24.5@4418.03,5008.62
  L1_Top Layer w11: v1(4366.47,4988.94) 4386.16,5008.62 4400,5008.62
  L10_Signal Layer 2 w6.5: v2@4115,9497 v2(4115,9492) 4134,9473 4134,7461 4020,7347 4020,6859.68 4558.5,6321.18 4558.5,5782.82 4492.5,5716.82 4492.5,5192.28 4366.47,5066.25 v1(4366.47,4988.94)
  L12_Bottom Layer w11: v2(4115,9492) 4147,9460 4498.5,9460 R603.1@4608.5,9570 4723,9570 4871.5,9718.5 R591.2@5017,9718.5 ; v1(4366.47,4988.94) 4386.16,5008.62 R368.2@4425.03,5008.62 4425.03,5056.23 C423.2@4424.27,5057 4371.27,5057 R228.2@4369.89,5058.38
SDCLKOUT1+: R276.2 U24.3 | length 192
  L1_Top Layer w6: R276.2@4258.03,5004.77 4279.78,5004.77 4296.78,4987.77 4313.89,4987.77 4369.77,5043.65 4395.88,5043.65 4400.22,5047.99 U24.3@4418.03,5047.99
SDCLKOUT1-: R279.2 U24.4 | length 192
  L1_Top Layer w6: R279.2@4258.03,4959.77 4279.78,4959.77 4296.78,4976.77 4318.45,4976.77 4374.33,5032.65 4395.88,5032.65 4400.22,5028.31 U24.4@4418.03,5028.31
SDCLKOUT3+: R292.2 U24.13 | length 339
  L1_Top Layer w6: R292.2@4088.65,4865.77 4110.4,4865.77 4129.37,4846.8 4395.88,4846.8 4400.22,4851.14 U24.13@4418.03,4851.14
SDCLKOUT3+*: R292.1 R293.1 R299.2 | length 113.7
  L1_Top Layer w6: R293.1@3933.09,4865.44 R293.1@3939.8,4872.15 ; R299.2@3985.03,4872.15 R299.2@3991.41,4865.77
  L1_Top Layer w10: R293.1@3939.8,4872.15 R299.2@3985.03,4872.15 ; R299.2@3991.41,4865.77 R292.1@4041.41,4865.77
SDCLKOUT3-: R294.2 U24.14 | length 339.5
  L1_Top Layer w6: R294.2@4088.65,4815.77 4110.4,4815.77 4130.43,4835.8 4395.88,4835.8 4400.22,4831.46 U24.14@4418.03,4831.46
SDCLKOUT3-*: R294.1 R295.1 R300.2 | length 109.3
  L1_Top Layer w6: R295.1@3933.09,4815.44 R295.1@3934.14,4814.39 ; R300.2@3985.03,4814.39 R300.2@3986.41,4815.77
  L1_Top Layer w10: R295.1@3934.14,4814.39 R300.2@3985.03,4814.39 ; R300.2@3986.41,4815.77 R294.1@4041.41,4815.77
SDCLKOUT5+: R342.2 U24.22 | length 175.5
  L1_Top Layer w6: R342.2@4496.34,4626.92 4511.72,4642.29 4534.54,4642.29 4546.39,4654.15 4546.39,4744.34 4542.05,4748.69 U24.22@4542.05,4766.5
SDCLKOUT5+*: R342.1 R343.1 R348.2 | length 430.5
  L1_Top Layer w6: R343.1@4211.59,4333.02 R343.1@4212.97,4331.64 ; R348.2@4211.59,4382.29 4211.59,4400.1 4234.71,4423.22 4234.71,4451.56 4265.15,4482 4374.24,4482 4447.56,4555.32 4447.56,4578.13 R342.1@4462.94,4593.51
  L1_Top Layer w10: R343.1@4211.59,4333.02 R348.2@4211.59,4382.29
SDCLKOUT5-: R345.2 U24.23 | length 192.6
  L1_Top Layer w6: R345.2@4527.48,4596.86 4542.86,4612.24 4542.86,4635.06 4551.34,4643.55 ; 4545.13,4637.34 4557.39,4649.59 4557.39,4744.34 4561.73,4748.69 U24.23@4561.73,4766.5
SDCLKOUT5-*: R345.1 R346.1 R347.2 | length 421.9
  L1_Top Layer w6: R346.1@4267.97,4331.64 R346.1@4268.82,4332.48 ; R347.2@4268.82,4382.29 4268.82,4400.1 4245.71,4423.22 4245.71,4447 4269.71,4471 4378.8,4471 4455.88,4548.08 4478.69,4548.08 R345.1@4494.07,4563.46
  L1_Top Layer w10: R346.1@4268.82,4332.48 R347.2@4268.82,4382.29
SDCLKOUT5_N: R235.1 R346.2 U22.1 | length 3283.5
  L1_Top Layer w6: v1(2968.8,4261.13) 2986.94,4242.99 2986.94,3796.06 3143,3640 3409.78,3640 3424.5,3654.72 3424.5,3723.22 3432.78,3731.5 3451.22,3731.5 3459.5,3723.22 3459.5,3563.22 3474.22,3548.5 3501.78,3548.5 3516.5,3563.22 3516.5,3723.22 3524.78,3731.5 3543.22,3731.5 3551.5,3723.22 3551.5,3563.22 3566.22,3548.5 3593.78,3548.5 3608.5,3563.22 3608.5,3723.22 3616.78,3731.5 3635.22,3731.5 3643.5,3723.22 3643.5,3654.72 3658.22,3640 4110,3640 4245.97,3775.97 4245.97,4240.65 4267.97,4262.65 R346.2@4267.97,4284.39
  L12_Bottom Layer w6: U22.1@2968.8,4181.94 v1(2968.8,4261.13)
SDCLKOUT5_P: R234.2 R235.2 R343.2 U22.2 | length 3345.9
  L1_Top Layer w6: v1(3016.08,4261.16) 2997.94,4243.02 2997.94,4216 3015,4198.94 3015,4181 2997.94,4163.94 2997.94,4145.06 3015,4128 3015,4114 2997.94,4096.94 2997.94,3800.61 3147.56,3651 3405.22,3651 3413.5,3659.28 3413.5,3727.78 3428.22,3742.5 3455.78,3742.5 3470.5,3727.78 3470.5,3567.78 3478.78,3559.5 3497.22,3559.5 3505.5,3567.78 3505.5,3727.78 3520.22,3742.5 3547.78,3742.5 3562.5,3727.78 3562.5,3567.78 3570.78,3559.5 3589.22,3559.5 3597.5,3567.78 3597.5,3727.78 3612.22,3742.5 3639.78,3742.5 3654.5,3727.78 3654.5,3659.28 3662.78,3651 4105.44,3651 4234.97,3780.53 4234.97,4240.65 4212.97,4262.65 R343.2@4212.97,4284.39
  L12_Bottom Layer w6: v1(3016.08,4261.16) 3018.8,4258.43 U22.2@3018.8,4181.94
  L12_Bottom Layer w11: R234.2@3018.8,4112.54 U22.2@3018.8,4181.94
SDCLKOUT11+: R349.2 U24.56 | length 201.2
  L1_Top Layer w6: R349.2@4584.67,5307.31 4584.67,5280.09 4596.76,5268 4596.76,5135.11 4601.1,5130.76 U24.56@4601.1,5112.95
SDCLKOUT11+*: R349.1 R350.1 R367.2 | length 427.4
  L1_Top Layer w6: R367.2@4306.23,5496.99 4306.23,5479.18 4282.86,5455.81 4282.86,5438 4299.86,5421 4443.77,5421 4508.67,5356.1 4535.89,5356.1 R349.1@4551.27,5340.72
  L1_Top Layer w10: R367.2@4306.23,5496.99 R350.1@4306.23,5546.99
SDCLKOUT11-: R354.2 U24.57 | length 192.1
  L1_Top Layer w6: R354.2@4549.67,5272.31 4576.9,5272.31 4585.76,5263.45 4585.76,5135.11 4581.42,5130.76 U24.57@4581.42,5112.95
SDCLKOUT11-*: R354.1 R355.1 R366.2 | length 436.5
  L1_Top Layer w6: R366.2@4248.48,5496.99 4248.48,5479.18 4271.86,5455.81 4271.86,5433.44 4295.3,5410 4439.21,5410 4500.89,5348.32 4500.89,5321.1 R354.1@4516.27,5305.72
  L1_Top Layer w10: R366.2@4248.48,5496.99 R355.1@4248.48,5546.99
SDCLKOUT11_N: R194.1 R355.2 U20.1 | length 3262.1
  L1_Top Layer w6: R355.2@4249.86,5595.62 4249.86,5617.36 4271.86,5639.36 4271.86,5675 v2(4252.86,5694)
  L12_Bottom Layer w6: U20.1@1582.81,5636.03 1582.81,5559.78 R194.1@1583.28,5559.32 1583.28,5541.51 1565.16,5523.38 1565.16,5491 1580,5476.16 1580,5459.84 1565.16,5445 1565.16,5415.4 1596.56,5384 1620,5384 1635,5399 1651,5399 1666,5384 1682,5384 1697,5399 1714,5399 1729,5384 2890,5384 3134,5628 4249,5628 4271.86,5650.86 4271.86,5675 v2(4252.86,5694)
SDCLKOUT11_P: R193.2 R194.2 R350.2 U20.2 | length 3333
  L1_Top Layer w6: v2(4301.86,5694) 4282.86,5675 4282.86,5639.36 4304.86,5617.36 R350.2@4304.86,5595.62
  L12_Bottom Layer w6: U20.2@1532.81,5636.03 1532.81,5562.54 R194.2@1536.04,5559.32 1536.04,5541.51 1554.16,5523.38 1554.16,5410.84 1592,5373 2894.56,5373 2934.56,5413 3138.56,5617 4253.56,5617 4282.86,5646.3 4282.86,5675 v2(4301.86,5694)
  L12_Bottom Layer w10: U20.2@1532.81,5636.03 R193.2@1532.81,5706.52
SDCLKOUT13+: R360.1 R363.2 U24.60 | length 771.2
  L1_Top Layer w6: R363.2@4139,5558.5 4139,5540.69 4115.62,5517.32 4115.62,5466.38 4214,5368 4380.45,5368 4518.02,5230.42 4518.02,5135.11 4522.36,5130.76 U24.60@4522.36,5112.95
  L1_Top Layer w10: R363.2@4139,5558.5 R360.1@4139,5608.5
SDCLKOUT13-: R361.1 R362.2 U24.61 | length 771.2
  L1_Top Layer w6: R362.2@4081.25,5558.5 4081.25,5540.69 4104.62,5517.32 4104.62,5461.82 4209.44,5357 4375.89,5357 4507.02,5225.87 4507.02,5135.11 4502.68,5130.76 U24.61@4502.68,5112.95
  L1_Top Layer w10: R362.2@4081.25,5558.5 R361.1@4081.25,5608.5
SDCLKOUT13_N: J2.1 J51.Z21 R361.2 R391.1 | length 7242.1
  L1_Top Layer w10: J2.1@3917.7,6153.02 4047.28,6153.02 4096.29,6104 4096.29,5694.54 4082.62,5680.87 v1(4082.62,5657.13)
  L4_Signal Layer 1 w4.9: v1(4082.62,5657.13) 4104.12,5678.63 4104.12,5729.09 4156.03,5781 4827,5781 5067.49,5540.51 5695.46,5540.51 5922,5313.97 5922,4331.97 6320.97,3933 6616.97,3933 6860.86,3689.11 6860.86,1511.84 6842.03,1493.01 6785.44,1493.01 v1(6766.44,1474.01) v1@6766.44,1476.5
SDCLKOUT13_P: J1.1 J51.Z20 R360.2 R390.1 | length 7241.2
  L1_Top Layer w10: v1(4137.62,5657.13) 4137.62,5680.87 4124.29,5694.21 4124.29,6104 4173.29,6153 J1.1@4302.89,6153
  L4_Signal Layer 1 w4.9: v1(4137.62,5657.13) 4116.12,5678.63 4116.12,5724.12 4161,5769 4186,5769 4198,5757 4221,5757 4233,5769 4250,5769 4262,5757 4285,5757 4297,5769 4321,5769 4333,5757 4356,5757 4368,5769 4385,5769 4397,5757 4420,5757 4432,5769 4458,5769 4470,5757 4493,5757 4505,5769 4522,5769 4534,5757 4557,5757 4569,5769 4822.03,5769 5062.51,5528.51 5690.49,5528.51 5910,5309 5910,4327 6316,3921 6612,3921 6848.86,3684.14 6848.86,1516.81 6837.06,1505.01 6785.44,1505.01 v1(6766.44,1524.01) ; v1@6766.75,1526.81 v1@6767.99,1525.57
SMB_CLK: J32.9 J62.4 R81.1 R162.1 R352.1 R442.2 R594.1 U9.13 U18.13 U25.8 | length 15200.7
  L1_Top Layer w11: U9.13@3112.97,9534.95 3126.28,9534.95 3148.9,9557.57 3148.9,9593.89 3185.03,9630.03 v1(3187.61,9630.03) ; U18.13@3181.3,3189.19 3194.61,3189.19 3217.23,3211.81 3217.23,3248.12 3253.36,3284.26 R162.1@3255.94,3284.26 3293.68,3322 v1@3630,3322 ; v1(4256,7157) 4333.5,7079.5 R442.2@4334.36,7079.5 ; J32.9@6398.35,10734.59 6399.65,10735.89 R594.1@6492.27,10735.89
  L4_Signal Layer 1 w5.5: v1(3187.61,9630.03) 3219.58,9662 3535,9662 3956,10083 4688,10083 5033,10428 5108,10428 J62.4@5159,10479 5206,10526 5820.6,10526 5980.5,10685.9 6349.67,10685.9 J32.9@6398.35,10734.59
  L10_Signal Layer 2 w6.5: v1(3630,3323.57) 3630,3874.75 4125.25,4370 4393.54,4370 4781.22,4757.68 4781.22,5230.87 4892,5341.64 4892,6203.5 4882.75,6212.75 4256,6839.5 v1(4256,7157) 4256,9380 4317,9441 4612,9441 4739,9568 4925,9568 5120.34,9763.34 5120.34,9862.66 5266,10008.32 5266,10237 5202,10301 5202,10436 J62.4@5159,10479
  L12_Bottom Layer w11: v1(4256,7157) 4256,6812.69 5082.47,5986.22 R352.1@5330.97,5986.22 5331.35,5985.84 U25.8@5393.18,5985.84
SMB_DAT: J32.10 J62.2 J62.6 R80.1 R161.1 R353.1 R443.2 U9.12 U18.12 U25.7 | length 15800
  L1_Top Layer w11: U9.12@3112.97,9515.27 3135.85,9515.27 v1(3187.61,9567.03) ; U18.12@3181.3,3169.5 3204.18,3169.5 R161.1@3255.94,3221.26 3264.28,3221.26 3294.48,3251.46 3343.38,3251.46 3343.84,3251 v1@3611.22,3251 ; v1@4214,7158 4214,7136.91 R443.2@4271.61,7079.3
  L4_Signal Layer 1 w5.5: v1(3187.61,9567.03) 3166,9588.63 3166,9643 3207,9684 3525,9684 3941,10100 4680,10100 J62.6@5059,10479 5126,10546 5821,10546 6009.59,10734.59 J32.10@6298.35,10734.59
  L10_Signal Layer 2 w6.5: v1@3611.5,3252 3611.5,3873.93 4120.07,4382.5 4388.37,4382.5 4768.72,4762.86 4768.72,5236.04 4879.5,5346.82 4879.5,6198.32 4338.41,6739.41 4243.5,6834.32 4243.5,7131.22 v1(4214,7160.72) 4240,7186.72 4240,9398 4299,9457 4593,9457 4728,9592 4920,9592 5099,9771 5099,9868 5248,10017 5248,10144 5106,10286 5106,10432 J62.6@5059,10479
  L12_Bottom Layer w11: v1(4214,7160.72) 4231.69,7143.04 4231.69,6795.31 5075,5952 5652,5952 5680.97,5980.97 R353.1@5680.97,5986.22 5680.59,5985.84 U25.7@5618.77,5985.84 ; J62.6@5059,10479 5108,10528 5210,10528 J62.2@5259,10479
  other v1: 3612.22,3252
STATUS_LD1: R372.1 U24.31 | length 503.5
  L1_Top Layer w9.84: 4719.22,4730 U24.31@4719.22,4766.5
  L1_Top Layer w11: 4719.22,4730 4719.22,4647.19 4988.39,4378.01 R372.1@4988.39,4374.47
STATUS_LD2: R373.1 U24.48 | length 407.1
  L1_Top Layer w9.84: U24.48@4764.49,5087.36 4786.36,5087.36 4796.29,5097.29
  L1_Top Layer w11: 4796.29,5097.29 4837,5138 4837,5183 4901,5247 5041.11,5247 R373.1@5067.97,5220.14
SYNC: R229.2 R412.2 R413.1 R414.2 R636.2 | length 11651.7
  L1_Top Layer w11: v2(5960,7385) 5960,7385.54 5974.99,7400.52 R413.1@6008.57,7400.52 ; v2(6004,1117) 6047.68,1117 R414.2@6060,1104.68
  L4_Signal Layer 1 w11: v2(5139,5863) 5231,5863 5549,6181 5549,6613.85 5650.24,6715.09 5650.24,6921.66 5540.95,7030.94 5540.95,7274.95 5651,7385 v2(5960,7385)
  L10_Signal Layer 2 w11: v2(5679,3388.99) 5061.99,3388.99 4551,2878 4551,1234.15 4741.15,1044 5817.83,1044 5890.83,1117 v2(6004,1117)
  L12_Bottom Layer w11: v2@5135,5863 4708,5863 4150,5305 4150,5151.44 R412.2@4181.03,5120.41 4186,5115.44 4186,4844 4120,4778 4120,3490 4241.73,3368.27 5525.46,3368.27 5584.57,3427.38 R229.2@5679,3427.38 ; v2(5679,3388.99) R229.2@5679,3427.38 ; R636.2@5735.38,3428 5679.62,3428 R229.2@5679,3427.38
SYNC1_N: J46.G13 R69.1 | length 4749.9
  L4_Signal Layer 1 w4.9: v1(2018.1,8396.54) 2041.35,8419.8 2081.77,8419.8 2115,8453.03 2115,8545 2156.49,8586.49 2264.51,8586.49 2304,8547 2646.03,8547 2760.03,8433 5623,8433 5708.19,8518.19 5956.11,8518.19 6235.29,8239.01 6394.11,8239.01 v1(6413.11,8220.01)
SYNC1_P: J46.G12 R68.1 | length 4749.9
  L4_Signal Layer 1 w4.9: v1(2018.1,8455.06) 2041.35,8431.8 2076.8,8431.8 2103,8458 2103,8549.97 2151.51,8598.49 2269.49,8598.49 2308.97,8559 2651,8559 2765,8445 5618.03,8445 5703.22,8530.19 5961.08,8530.19 6240.26,8251.01 6394.11,8251.01 v1(6413.11,8270.01)
SYNC1_SE: J46.H31 R587.1 R633.1 | length 321.2
  L1_Top Layer w11: R633.1@6055.82,7353.28 6055.92,7353.39 R587.1@6105.11,7353.39 6112.48,7346.01 6337.11,7346.01 v1(6363.11,7320.01)
SYNC1SE: R71.1 R72.2 U8.C2 | length 147.4
  L12_Bottom Layer w11: R71.1@2116.17,8352.47 R72.2@2166.17,8352.47 2197.85,8352.47 2214.99,8335.33 v1(2256.43,8335.33)
SYNC2_N: J51.G13 R150.1 | length 4752.7
  L4_Signal Layer 1 w4.9: v1(2011.43,2052.55) 2034.68,2075.8 2075.1,2075.8 2108.33,2109.03 2108.33,2214.33 2136.49,2242.49 2239.54,2242.49 2279.03,2203 2639.36,2203 2753.36,2089 5616.33,2089 5682.33,2155 5902.03,2155 6162.02,1895.01 6395.44,1895.01 v1(6416.44,1874.01)
SYNC2_P: J51.G12 R149.1 | length 4751
  L4_Signal Layer 1 w4.9: v1(2011.43,2111.06) 2034.68,2087.8 2070.13,2087.8 2096.33,2114 2096.33,2219.3 2131.52,2254.49 2244.51,2254.49 2284,2215 2644.33,2215 2758.33,2101 5611.36,2101 5677.36,2167 5907,2167 6166.99,1907.01 6399.44,1907.01 v1(6416.44,1924.01)
SYNC2_SE: J51.H31 R589.1 R637.1 | length 320.6
  L1_Top Layer w11: R637.1@6060,1010.19 R589.1@6108.75,1010.19 6116.13,1002.81 6340.75,1002.81 v1@6366.75,976.81
  other v1: 6366.44,974.01
SYNC2SE: R152.1 R153.2 U17.C2 | length 157.4
  L12_Bottom Layer w10: R152.1@2109.5,2006.48 2201.18,2006.48 2218.32,1989.33 v1(2259.76,1989.33)
SYNC_ADC1: R71.2 R413.2 R633.2 | length 4447.7
  L1_Top Layer w11: v2(5358.57,7570.9) 5493.47,7436 6020.34,7436 R413.2@6055.82,7400.52
  L4_Signal Layer 1 w5.5: v1(2156.93,8465.8) 2156.93,8465.89 2184.04,8493 2638.66,8493 2908.49,8223.17 4706.3,8223.17 v2(5358.57,7570.9) v2@5358.57,7568.9
  L12_Bottom Layer w11: R71.2@2116.17,8399.72 2156.93,8440.48 v1(2156.93,8465.8)
SYNC_ADC2: R152.2 R414.1 R637.2 | length 4461.2
  L1_Top Layer w11: v2(5351.9,1226.91) 5487.27,1091.53 6025.9,1091.53 R414.1@6060,1057.43
  L4_Signal Layer 1 w3.5: v2@5351.9,1224.91 v2(5351.9,1226.91) v2@5356.6,1226.91
  L4_Signal Layer 1 w5.5: v1(2150.26,2121.8) 2150.26,2121.89 2175.37,2147 2634,2147 2901.82,1879.18 4699.63,1879.18 v2(5351.9,1226.91)
  L12_Bottom Layer w11: R152.2@2109.5,2055.72 2150.26,2096.48 v1(2150.26,2121.8)
SYNCSE_EXTIN: J56.1 R631.1 U64.1 | length 568.6
  L12_Bottom Layer w11: U64.1@5931.19,3479.41 5970.99,3479.41 R631.1@5991.9,3500.32 6035.32,3500.32 6233.82,3698.82 J56.1@6408.9,3698.82
SYNCSE_EXTOUT: J57.1 R588.2 R632.1 U64.2 | length 792.5
  L12_Bottom Layer w11: R588.2@5884.62,3643 5884.62,3472.38 5903.18,3453.82 U64.2@5931.19,3453.82 5973.4,3453.82 R632.1@5991.9,3435.31 6035.32,3435.31 6233.82,3236.82 J57.1@6408.9,3236.82
SYS1+: C94.2 C321.2 U8.K1 | length 132.6
  L1_Top Layer w6: C321.2@2105.51,8126.19 2127.26,8126.19 2148.83,8104.61 2200.81,8104.61 2211.06,8114.86 U8.K1@2224.94,8114.86
SYS1-: C95.2 C325.2 U8.L1 | length 131.9
  L1_Top Layer w6: C325.2@2104.13,8077.19 2127.26,8077.19 2143.68,8093.61 2200.81,8093.61 2211.06,8083.36 U8.L1@2224.94,8083.36
SYS2+: C254.2 C334.2 U17.K1 | length 132.6
  L1_Top Layer w6: C334.2@2108.84,1780.19 2130.59,1780.19 2152.16,1758.61 2204.15,1758.61 2214.39,1768.86 U17.K1@2228.27,1768.86
SYS2-: C255.2 C341.2 U17.L1 | length 131.9
  L1_Top Layer w6: C255.2@2107.46,1731.19 2108.76,1731.19 C341.2@2108.84,1731.19 2130.59,1731.19 2147.01,1747.61 2204.15,1747.61 2214.39,1737.37 U17.L1@2228.27,1737.37
TDI_1: J51.D30 J52.1 | length 790.4
  L12_Bottom Layer w5: 6102.4,1030.16 6125.05,1052.81 6540.75,1052.81 J51.D30@6566.75,1026.81
  L12_Bottom Layer w11: J52.1@5830.85,951.48 5894.55,1015.18 6087.42,1015.18 6102.4,1030.16 ; J51.D30@6565.19,1025.26 J51.D30@6566.44,1024.01
TDIODE1+: J11.1 R78.2 U8.K2 | length 2251.5
  L10_Signal Layer 2 w5.5: v1(2256.43,8114.86) 2266.18,8105.11 2266.18,8089.8 2257.18,8080.8 2174.82,8080.8 2147.83,8107.79 2147.83,8228.87 2075,8301.7 2075,8461.97 1964,8572.97 1964,9373 2078,9487 2453.64,9487 2486.42,9519.77 2486.42,9548.16 J11.1@2530.82,9592.56
  L12_Bottom Layer w11: J11.1@2530.82,9592.56 R78.2@2603.93,9592.56 R78.2@2604.16,9592.79
TDIODE1-: J11.2 R79.2 U8.K3 | length 2288.4
  L10_Signal Layer 2 w5.5: v1(2287.93,8114.86) 2278.18,8105.11 2278.18,8084.83 2262.15,8068.8 2169.85,8068.8 2137.67,8100.98 2135.83,8102.82 2135.83,8223.9 2063,8296.73 2063,8457 1952,8568 1952,9377.97 1957,9382.97 2073.03,9499 2448.67,9499 2474.42,9524.74 2474.42,9548.96 J11.2@2430.82,9592.56
  L12_Bottom Layer w11: R79.2@2360.16,9592.17 2360.56,9592.56 J11.2@2430.82,9592.56
TDIODE1N: C116.2 C117.2 Q1.2 R79.1 U9.5 | length 962
  L1_Top Layer w6: Q1.2@2781.35,9484.05 2783.13,9482.27 v2(2840.1,9482.27) C117.2@2890.1,9482.27 2896.47,9475.9 U9.5@2963.36,9475.9
  L12_Bottom Layer w6: R79.1@2360.16,9544.93 2453.62,9544.93 2476.55,9522 2476.55,9480.9 2591.75,9365.69 2870,9365.69 2899.44,9395.14 2899.44,9448.7 2884,9464.15 2858.22,9464.15 v2(2840.1,9482.27)
TDIODE1P: C116.1 R78.1 U9.7 | length 888.6
  L1_Top Layer w6: v2(2961.9,9404.89) 2963.36,9406.36 U9.7@2963.36,9436.53
  L4_Signal Layer 1 w5.5: v2(2840.1,9435.03) 2870.24,9404.89 v2(2961.9,9404.89)
  L12_Bottom Layer w6: R78.1@2603.93,9545.32 2510.87,9545.32 2487.55,9522 2487.55,9485.45 2596.31,9376.69 2865.44,9376.69 2888.44,9399.69 2888.44,9444.15 2879.44,9453.15 2858.22,9453.15 v2(2840.1,9435.03)
TDIODE2+: J22.1 R159.2 U17.K2 | length 2296.3
  L10_Signal Layer 2 w5.5: v1(2259.76,1768.86) 2269.51,1759.11 2269.51,1743.8 2260.51,1734.8 2178.15,1734.8 2151.16,1761.8 2151.16,1888.81 2070.26,1969.71 2070.26,2210.74 1983.05,2297.95 1983.05,3036.05 2100,3153 2530.97,3153 2551.75,3173.78 2551.75,3202.17 J22.1@2596.15,3246.57
  L12_Bottom Layer w11: J22.1@2596.15,3246.57 R159.2@2669.26,3246.57
TDIODE2-: J22.2 R160.2 U17.K3 | length 2332.9
  L10_Signal Layer 2 w5.5: 2141,1754.98 2173.18,1722.8 2265.48,1722.8 2281.51,1738.83 2281.51,1759.11 v1(2291.26,1768.86) ; 2141,1754.98 2139.16,1756.83 2139.16,1883.84 2058.26,1964.74 2058.26,2205.77 1971.05,2292.98 1971.05,3041.02 2095.03,3165 2526,3165 2539.75,3178.75 2539.75,3202.97 J22.2@2496.15,3246.57
  L12_Bottom Layer w11: R160.2@2425.89,3246.57 J22.2@2496.15,3246.57
TDIODE2N: C276.2 C277.2 Q2.2 R160.1 U18.5 | length 968.6
  L1_Top Layer w6: Q2.2@2849.68,3138.28 2851.46,3136.5 v2(2908.43,3136.5) C277.2@2958.43,3136.5 2964.8,3130.13 U18.5@3031.69,3130.13
  L12_Bottom Layer w6: R160.1@2425.49,3198.93 2517.85,3198.93 2541.88,3174.91 2541.88,3127.57 2649.52,3019.93 2938.33,3019.93 2967.77,3049.37 2967.77,3102.94 2952.33,3118.38 2926.55,3118.38 v2(2908.43,3136.5)
TDIODE2P: C276.1 R159.1 U18.7 | length 895.2
  L1_Top Layer w6: v2(3030.23,3059.12) 3031.69,3060.59 U18.7@3031.69,3090.76
  L4_Signal Layer 1 w5.5: v2(2908.43,3089.26) 3000.09,3089.26 v2(3030.23,3059.12)
  L12_Bottom Layer w6: R159.1@2669.26,3199.32 2577.3,3199.32 2552.88,3174.91 2552.88,3132.12 2654.07,3030.93 2933.77,3030.93 2956.77,3053.93 2956.77,3098.38 2947.77,3107.38 2926.56,3107.38 v2(2908.43,3089.26)
TDO_1: J51.D31 J52.2 | length 668
  L12_Bottom Layer w5: 6094.65,986.91 6108.55,1000.81 6542.75,1000.81 J51.D31@6566.75,976.81
  L12_Bottom Layer w11: J52.2@5930.85,951.48 6059.22,951.48 6094.65,986.91 ; J51.D31@6565.19,975.26 J51.D31@6566.44,974.01
TMSP1+: J8.1 R67.1 | length 1943.7
  L10_Signal Layer 2 w5.5: 1874.98,9410 1874.98,9423.02 ; v1(1969,8502) 1968.59,8501.59 v1@1968.59,8500.04 ; v1@1970.85,8502.3 1969.78,8501.22 v1@1968.59,8500.04 ; J8.1@2067.22,9677.9 1926.32,9677.9 1875,9626.58 1875,9464 1886.98,9452.02 1886.98,9435.02 1875,9423.04 1875,9310.03 1854,9289.03 1854,8263.97 1863.97,8254 1888,8254 1897,8263 1897,8411.97 1916.83,8431.8 1939.03,8431.8 1968.59,8461.36 v1@1968.59,8500.04
TMSP1-: J9.1 R70.1 | length 1941.6
  L10_Signal Layer 2 w5.5: J9.1@1669.62,9677.9 1810.52,9677.9 1863,9625.42 1863,9315 1842,9294 1842,8259 1859,8242 1892.97,8242 1909,8258.03 1909,8407 1921.8,8419.8 1939.03,8419.8 1968.59,8390.24 v1@1968.59,8351.56 ; v1(1969,8349) 1968.59,8349.41 v1@1968.59,8351.56 ; v1@1970.85,8349.3 1970.08,8350.08 v1@1968.59,8351.56
TMSP2+: J19.1 R148.1 | length 1943.3
  L10_Signal Layer 2 w5.5: J19.1@1662.64,440.91 1803.54,440.91 1856.02,493.38 1856.02,2043.78 1897.25,2085.01 1935,2085.01 1960.25,2110.26 1960.25,2151.88 1961,2152.63 v1(1961,2156)
TMSP2-: J20.1 R151.1 | length 1941.7
  L10_Signal Layer 2 w5.5: 1868,1947 1868,1970 ; 1868.02,1946.98 1879.98,1935.02 1879.98,1918.02 1868.02,1906.06 1868.02,492.23 1919.34,440.91 J20.1@2060.24,440.91 ; 1868.02,1970.02 1880,1982 1880,1999 1868.02,2010.98 1868.02,2038.8 1902.22,2073.01 1935,2073.01 1960.25,2047.76 1960.25,2006.13 1960,2005.88 v1(1960,2003)
TMSTP1+: R67.2 R68.2 U8.B1 | length 306.4
  L1_Top Layer w6: R67.2@2007.79,8501.5 2018.1,8501.5 2025.6,8501.5 2096.6,8430.5 2133.78,8430.5 2151.93,8412.36 2151.93,8369.8 2165.15,8356.58 2200.81,8356.58 2211.06,8366.83 U8.B1@2224.94,8366.83
TMSTP1-: R69.2 R70.2 U8.C1 | length 306.4
  L1_Top Layer w6: R69.2@2007.79,8348.5 2018.1,8348.5 2025.6,8348.5 2096.6,8419.5 2129.23,8419.5 2140.93,8407.8 2140.93,8365.24 2160.6,8345.58 2200.81,8345.58 2211.06,8335.33 U8.C1@2224.94,8335.33
TMSTP2+: R148.2 R149.2 U17.B1 | length 306.4
  L1_Top Layer w6: R148.2@2011.12,2155.51 2028.93,2155.51 2099.93,2084.51 2137.12,2084.51 2155.26,2066.36 2155.26,2023.8 2168.48,2010.58 2204.15,2010.58 2214.39,2020.83 U17.B1@2228.27,2020.83
TMSTP2-: R150.2 R151.2 U17.C1 | length 306.4
  L1_Top Layer w6: R150.2@2011.12,2002.51 2028.93,2002.51 2099.93,2073.51 2132.56,2073.51 2144.26,2061.8 2144.26,2019.25 2163.93,1999.58 2204.15,1999.58 2214.39,1989.33 U17.C1@2228.27,1989.33
USB_ACTIVITY: R549.1 U34.34 | length 186.3
  L1_Top Layer w11: R549.1@4935.88,10102.97 R549.1@4940.08,10098.77 ; R549.1@4938.31,10097 5023.38,10011.92 U34.34@5083.38,10011.92
USB_DM: J72.2 R472.1 | length 117.2
  L1_Top Layer w8.2: R472.1@6493.24,10140.92 6518.28,10165.95 6536.49,10165.95 6545.14,10157.31 J72.2@6596.53,10157.31
USB_DP: J72.3 R539.1 | length 117.1
  L1_Top Layer w8.2: R539.1@6493.24,10204.92 6518,10180.15 6536.49,10180.15 6545.14,10188.8 J72.3@6596.53,10188.8
V1P1V: C535.2 C536.2 C542.2 C543.2 C577.2 C578.2 J59.22 J59.24 J59.26 L37.1 L38.1 L39.1 L40.1 L84.1 TP26.1
  other v2: 2066,2323 2097,2323 2066,2360 2097,2360 2066,2393 2097,2393 2079,2427 2110,2427 2937.71,2728.5 2985.71,2728.5 3033.71,2728.5 2937.71,2776.5 2985.71,2776.5 3033.71,2776.5 2937.71,2824.5 2985.71,2824.5 3033.71,2824.5 2045.2,8628 1997,8661 2028,8661 2059,8661 2084.87,8683.63 2115.87,8683.63 1997,8698 2028,8698 2059,8698 2869.94,9081.91 2917.94,9081.91 2965.94,9081.91 2869.94,9129.91 2917.94,9129.91 2965.94,9129.91 2869.94,9177.91 2917.94,9177.91 2965.94,9177.91 2429,10020 2603,10020 2429,10078 2603,10078 2429,10136 2487,10136 2545,10136 2603,10136
V1P1V_IN: C539.2 C540.2 C541.2 J59.21 J59.23 J59.25 L84.2 R618.2 U43.3
  other v2: 2440,10435 2479,10435 2518,10435 2557,10435 2596,10435
V1P9V: C532.2 C533.2 C534.2 C581.2 C582.2 J59.12 J59.14 J59.16 L35.1 L36.1 L72.1 L83.1 TP22.1
  other v2: 2031.21,1530.63 2062.21,1530.63 2093.21,1530.63 2031.21,1567.63 2062.21,1567.63 2093.21,1567.63 2031.21,1604.63 2062.21,1604.63 2093.21,1604.63 2038,7881 2069,7881 2100,7881 2038,7918 2069,7918 2100,7918 2038,7955 2069,7955 2100,7955 6596.11,9765.8 6633.11,9765.8 6596.11,9802.8 6633.11,9802.8 6596.11,9839.8 6633.11,9839.8 6596.11,9876.8 6633.11,9876.8 2928,10020 3102,10020 2928,10078 3102,10078 2928,10136 2986,10136 3044,10136 3102,10136
V1P9V_IN: C496.2 C497.2 C498.2 J59.11 J59.13 J59.15 L83.2 R614.2 U40.3
  other v2: 3057,10396 3096,10396 3018,10435 3057,10435 3096,10435
V3P3: C545.1 C546.2 C547.1 C548.2 C549.1 C550.2 C551.1 C552.2 C553.2 C554.2 C555.2 C556.2 C579.2 C580.2 J59.2 J59.4 J59.6 L41.1 L42.1 L43.1 L44.1 L45.1 L46.1 L47.1 L73.1 L74.1 TP33.1
  other v2: 5364,3576 5414.07,3576.12 5462.07,3576.12 5510.07,3576.12 5558.07,3576.12 5414.07,3624.12 5462.07,3624.12 5510.07,3624.12 5558.07,3624.12 2741.91,4653.28 2777.91,4653.28 2813.91,4653.28 1297.64,4677.39 1345.64,4677.39 2742,4702 2778,4702 2814,4702 1297.64,4725.39 1345.64,4725.39 2741.91,4749.28 2777.91,4749.28 2813.91,4749.28 1297.64,4773.39 1345.64,4773.39 1297.64,4821.39 1345.64,4821.39 1297.64,4869.39 1345.64,4869.39 1297.64,4917.39 1345.64,4917.39 2933,5910 2965,5910 2997,5910 3029,5910 2933,5958 2965,5958 2997,5958 3029,5958 3454,10015 3602,10020 3602,10078 3428,10136 3486,10136 3544,10136 3602,10136 4626,10705 4661,10705 4626,10746 4661,10746
V3P3_IN: C602.2 C603.2 C604.2 J59.1 J59.3 J59.5 L74.2 R622.2 U46.3
  other v2: 3732,10339 3771,10339 3810,10339 3732,10378 3771,10378 3810,10378
V3P3_LMK48XX: C625.1 C626.1 C627.2 C628.1 L22.1 L23.1 L24.1 L25.1 L29.1 L30.1 L31.1 L45.2 R228.1 R271.2 R286.2 R321.1 R340.1 R369.1 TP37.1 | length 722.3
  L1_Top Layer w15: R321.1@5234.67,4982.2 v2@5263.1,4982.2 ; R340.1@5234.67,5132.45 v2@5263.1,5132.45
  L1_Top Layer w20: v2(3858.62,5219.44) R271.2@3893.85,5219.44 ; v2(4049.16,4748.08) R286.2@4084.39,4748.08 ; v2(4302.47,4616.94) 4302.89,4616.52 L23.1@4350.97,4616.52 ; v2(4310.89,5250) 4310.89,5244.52 4316.9,5238.51 L31.1@4365.97,5238.51
  L12_Bottom Layer w20: v2(3858.62,5219.44) v2@3859.84,5218.22 ; v2(4049.16,4748.08) v2@4050.38,4746.86 ; v1(4226.47,4912.94) R369.1@4270.47,4956.94 ; v2(4278.89,5119) 4278.89,5100.38 R228.1@4322.27,5057 ; L24.1@4565.97,4620.52 L25.1@4627.97,4620.52 4627.97,4575.44 v1(4608.47,4555.94) ; L30.1@4769.05,5168.44 4803.61,5203 v1(4818,5203) ; L22.1@4846.97,4729.52 4871.37,4729.52 4899.89,4701 v2(4924.89,4701) ; L29.1@4908.97,5173.51 v2(4958.9,5173.51)
  other v2: 5011.23,3785.01 5071.23,3785.01 5131.23,3785.01 5011.23,3833.01 5071.23,3833.01 5131.23,3833.01 5071.23,3881.01 5131.23,3881.01 5264.17,4982.98 5264.17,5133.23
V3P3_LMK61E2: C629.1 C630.1 C631.2 C632.1 L21.2 L46.2 L56.1 R163.2 R352.2 R353.2 R358.1 TP38.1 | length 235.3
  L1_Top Layer w20: R163.2@5872.89,6058.6 5872.89,6095.89 v2(5873,6096)
  L12_Bottom Layer w11: R358.1@5505.84,5799 R358.1@5505.97,5798.87 ; L21.2@5512.38,5642.51 L21.2@5512.51,5642.64
  L12_Bottom Layer w20: v2(5303.08,6033.46) R352.2@5330.97,6033.46 ; v2(5468,5799) R358.1@5505.84,5799 ; L21.2@5512.51,5642.64 v2(5512.51,5680.48) ; R353.2@5680.97,6033.46 5717.02,6033.46 v2(5717.14,6033.35) ; v2@5770.78,5976.81 5788.35,5994.39 L56.1@5788.35,6027.22
  other v2: 5908,5399 5956,5399 5908,5447 5956,5447 5861,5472 5861,5520 5771.08,5976.52
V3P3_LMK00304: C381.1 C382.1 C383.1 C485.1 C486.1 C487.2 C488.1 J24.1 J24.2 J24.3 J24.4 L73.2 R245.2 R246.2 R247.2 R248.2 R249.2 R250.2 R251.2 TP24.1 | length 437.9
  L1_Top Layer w11: R245.2@3164.5,5131.41 R245.2@3168,5134.91
  L1_Top Layer w20: v2(3038,4966) 3038.21,4965.79 R246.2@3079.88,4965.79 ; R245.2@3168,5134.91 v2(3168,5173) ; v2(3178.76,4762) 3178.38,4762.38 C383.1@3219,4762.38 3219.71,4761.67 R251.2@3270.5,4761.67 ; v2(3237.62,5200.62) 3237.83,5200.41 R249.2@3279.5,5200.41 ; R250.2@3330.5,5200.91 3372.17,5200.91 v2(3372.38,5200.7) ; C382.1@3545.12,4916.29 3586.79,4916.29 v2(3587,4916.07) ; R247.2@3545.12,4966.29 3586.79,4966.29 v2(3587,4966.07) ; R248.2@3545.12,5021.29 3586.79,5021.29 v2(3587,5021.07) ; C381.1@3561,4857.79 3610.79,4857.79 v2(3611,4858)
  other v2: 3029,4483 2947,4524 2988,4524 3029,4524 3029,4565
V3P3_LMX1: C328.2 C329.2 C330.2 C331.2 C350.2 C596.1 C597.1 C598.2 C599.1 L41.2 R165.1 R167.1 R170.1 R171.2 R172.1 R173.2 TP31.1 U20.8 | length 1526.2
  L1_Top Layer w30: C329.2@1827.11,5592.72 C329.2@1828.17,5593.78 ; C328.2@1829.2,5669.45 C328.2@1830.26,5670.52 ; v2(1829.23,5533.54) C329.2@1829.23,5592.72 C329.2@1828.17,5593.78 ; v2(1830.26,5729.69) C328.2@1830.26,5670.52 ; C328.2@1831.33,5669.45 C328.2@1830.26,5670.52 ; v2(1865.09,5991.92) R173.2@1904.23,5991.92 ; v2(1887.34,5593.78) C329.2@1828.17,5593.78 ; v2(1889.44,5670.52) C328.2@1830.26,5670.52 ; v2(1992.88,6477.14) R171.2@2026.45,6477.14 ; v2(2069.52,5857.32) R172.1@2108.66,5857.32 ; C331.2@2767.14,6078.05 C331.2@2768.2,6079.11 ; v2(2767.17,6211.96) 2767.17,6153.85 C330.2@2767.17,6152.79 ; C330.2@2768.23,6151.73 C330.2@2767.17,6152.79 ; v2(2769.26,6018.88) C331.2@2769.26,6078.05 C331.2@2768.2,6079.11 ; v2(2827.37,6079.11) C331.2@2768.2,6079.11 ; v2(2827.41,6153.85) C330.2@2768.23,6153.85 C330.2@2767.17,6152.79
  L4_Signal Layer 1 w30: v2(1992.88,6477.14) 2185.86,6477.14 2270,6393 2270,6266 2291.68,6244.32 v2(2385.81,6244.32)
  L12_Bottom Layer w20: U20.8@1582.81,5821.27 1650.97,5821.27 C350.2@1651.97,5820.27 v2(1703.17,5820.27) ; R165.1@2245.1,5805.31 2334.42,5805.31 v2(2369.86,5769.87) ; v2(2385.81,6244.32) 2385.81,6212.28 R170.1@2404.81,6193.28 ; R167.1@2468.86,6038.93 R167.1@2463.84,6033.92 v2(2502.86,6033.87)
  other v2: 1291,5251 1333.94,5251.3 1393.94,5251.3 1453.94,5251.3 1513.94,5251.3 1291,5311 1333.94,5311.3 1453.94,5311.3 1291,5371 1333.94,5371.3
V3P3_LMX1RF: C528.1 C529.1 C605.1 C606.2 C607.1 L17.1 L18.1 L42.2 R169.1 TP34.1 | length 350.9
  L1_Top Layer w20: C528.1@2172,6475.5 2172,6423.84 v2(2183.37,6412.47) L17.1@2216.07,6412.47 ; L18.1@2487.51,6256.72 v2(2487.51,6289.42) 2488.5,6290.41 C529.1@2488.5,6340
  L12_Bottom Layer w20: v2(2389.81,6300.72) 2390.37,6301.28 R169.1@2390.37,6338.72
  L12_Bottom Layer w30: R169.1@2390.37,6338.72 2457.03,6338.72 2487.51,6308.23 v2(2487.51,6289.42)
  other v2: 2908.28,6275.23 2956.28,6275.23 3004.28,6275.23 2908.28,6335.23 2956.28,6335.23 3004.28,6335.23 2908.28,6395.23 2956.28,6395.23 3004.28,6395.23
V3P3_LMX2: C358.2 C359.2 C360.2 C361.2 C380.2 C609.1 C610.1 C611.2 C612.1 L43.2 R206.1 R208.1 R211.1 R212.2 R213.1 R214.2 TP35.1 U22.8 | length 1423.7
  L1_Top Layer w30: v2(1706.98,3811.53) C358.2@1766.15,3811.53 ; v2(1709.07,3888.26) 1767.18,3888.26 C359.2@1768.25,3888.26 ; C358.2@1765.09,3812.59 C358.2@1766.15,3811.53 ; v2(1766.15,3752.35) C358.2@1766.15,3811.53 ; C358.2@1767.21,3812.59 C358.2@1766.15,3811.53 ; v2(1767.18,3948.5) C359.2@1767.18,3889.33 C359.2@1768.25,3888.26 ; C359.2@1769.31,3889.33 C359.2@1768.25,3888.26 ; R213.1@2442.96,3960.65 v2(2482.1,3960.65) ; R212.2@2525.87,3340.13 v2(2559.44,3340.13) ; R214.2@2647.39,3826.06 v2(2686.53,3826.06) ; v2(2689.21,4183.18) C361.2@2748.38,4183.18 C361.2@2749.45,4184.24 ; C361.2@2748.38,4185.31 C361.2@2749.45,4184.24 ; v2(2749.45,4125.07) C361.2@2749.45,4184.24 ; C360.2@2822.06,4184.21 C360.2@2823.12,4185.28 ; v2(2824.18,4125.04) C360.2@2824.18,4184.21 C360.2@2823.12,4185.28 ; v2(2882.29,4185.28) 2824.18,4185.28 C360.2@2823.12,4185.28
  L4_Signal Layer 1 w30: v2(2048.76,3784.1) 2024.1,3784.1 1982,3742 1982,3629 2034.84,3576.16 v2(2169.57,3576.16)
  L12_Bottom Layer w20: v2@2048.8,3784.06 R208.1@2087.78,3784.06 R208.1@2082.76,3779.04 ; R211.1@2142.48,3622.45 2169.83,3595.1 2169.57,3594.84 v2(2169.57,3576.16) ; v2(2181.76,4048.1) 2217.2,4012.66 R206.1@2306.51,4012.66 ; v2(2932,3844) 2953,3844 2967.8,3858.8 C380.2@2967.8,3899.45 2968.8,3900.46 U22.8@2968.8,3992.97
  other v2: 1574,4465 1634,4465 1694,4465 1574,4513 1634,4513 1694,4513 1574,4561 1634,4561 1694,4561
V3P3_LMX2RF: C530.1 C531.1 C622.1 C623.2 C624.1 L19.1 L20.1 L44.2 R210.1 TP36.1 | length 222.2
  L1_Top Layer w20: L20.1@2064.1,3561.26 v2(2064.1,3528.56) 2064.1,3495.39 C531.1@2082.5,3477 ; L19.1@2335.55,3405.5 v2(2368.25,3405.5) 2386,3387.75 C530.1@2386,3353.5
  L12_Bottom Layer w20: R210.1@2156.32,3477.61 2156.32,3515.05 v2(2156.88,3515.61)
  other v2: 1543.1,4031.68 1593.1,4031.68 1643.1,4031.68 1543.1,4079.68 1593.1,4079.68 1643.1,4079.68 1543.1,4127.68 1593.1,4127.68 1643.1,4127.68
V3P3_VDD: C69.2 C70.1 C107.1 C108.1 C109.1 C147.1 C148.1 C229.2 C230.1 C267.1 C268.1 C269.1 C441.2 C444.2 C447.2 C449.2 C451.2 C453.2 C455.2 C468.2 C489.2 C508.1 C511.1 C633.1 C634.1 C635.2 C636.1 C737.2 C741.2 D5.1 D10.1 J71.1 L47.2 R49.2 R74.2 R75.2 R76.2 R80.2 R81.2 R130.2 R155.2 R156.2 R157.2 R161.2 R162.2 R404.1 R406.1 R411.1 R420.1 R425.1 R429.1 R430.1 R431.1 R440.1 R441.1 R467.1 R468.1 R541.2 R548.2 R550.2 R631.2 R632.2 R634.2 R635.2 TP39.1 U7.8 U9.2 U16.8 U18.2 U18.9 U26.1 U26.2 U26.8 U26.16 U27.1 U27.7 U27.8 U27.16 U29.1 U29.2 U29.7 U29.8 U29.16 U30.1 U30.2 U30.7 U30.8 U30.16 U31.1 U31.2 U31.7 U31.8 U31.16 U32.16 U33.16 U54.5 U55.16 U57.1 U57.16 U58.2 U58.16 U63.5 U64.5 U73.1 U75.8 | length 7221.1
  L1_Top Layer w8: U18.9@3181.3,3110.45 3208.5,3110.45 v1(3218.92,3100.02)
  L1_Top Layer w10: 2929.96,9534.95 U9.2@2963.36,9534.95 ; 2998.29,3189.19 U18.2@3031.69,3189.19
  L1_Top Layer w11: U75.8@4081.01,9224.47 4100.53,9224.47 4110,9215 4110,9174.5 C148.1@4104.5,9169 ; C444.2@4908.68,9072.79 U27.16@4908.68,9127.63 ; U27.7@5140.96,9281.18 U27.8@5140.96,9306.77
  L1_Top Layer w12: v2(3775.15,6629.3) 3775.21,6629.24 U30.2@3827.61,6629.24 ; v2(3775.15,6757.26) 3775.21,6757.2 U30.7@3827.61,6757.2 ; v2(3778.48,283.31) 3778.54,283.25 U31.2@3830.94,283.25 ; v2(3778.48,411.26) 3778.54,411.2 U31.7@3830.94,411.2 ; U30.1@3827.61,6603.65 v2(3880.07,6603.59) v2(3880.07,6603.59) ; U30.8@3827.61,6782.79 3880.01,6782.79 v2(3880.07,6782.73) ; U31.1@3830.94,257.66 3883.34,257.66 v2(3883.4,257.6) ; U31.8@3830.94,436.79 3883.34,436.79 v2(3883.4,436.73)
  L1_Top Layer w15: U58.16@3430.04,4098.58 3557.33,4098.58 3582.92,4124.17 U58.2@3662.32,4124.17 ; U27.1@5140.96,9127.63 5202.18,9127.63 v2(5202.72,9127.09) ; v2@5474.72,10302 U26.8@5474.72,10333.41 ; U26.2@5474.72,10486.95 5432.05,10486.95 v2(5421,10498) 5435.54,10512.54 U26.1@5474.72,10512.54 ; U26.16@5707,10512.54 5707,10572.74 C441.2@5707.21,10572.95 ; v2(6079.83,9557.28) R420.1@6127.55,9557.28
  L1_Top Layer w20: v2(2654.9,9614.89) 2701.38,9614.89 C108.1@2747.1,9569.17 ; v2(2656.9,9568.89) 2656.62,9569.17 C108.1@2747.1,9569.17 ; v2(2657.9,9524.89) 2702.83,9524.89 C108.1@2747.1,9569.17 ; v2(2725.23,3223.12) 2724.95,3223.4 C268.1@2815.43,3223.4 ; v2(2726.23,3179.12) 2771.16,3179.12 C268.1@2815.43,3223.4 ; v2(2750,3273) 2765.83,3273 C268.1@2815.43,3223.4 ; 2929.96,9534.95 2917.17,9534.95 C109.1@2890.1,9562.03 2841.1,9562.03 C107.1@2840.1,9563.03 2753.24,9563.03 C108.1@2747.1,9569.17 ; 2998.29,3189.19 2985.5,3189.19 C269.1@2958.43,3216.26 2909.43,3216.26 C267.1@2908.43,3217.26 2821.57,3217.26 C268.1@2815.43,3223.4 ; v2(3022.9,9622.89) 3023.03,9623.03 R76.2@3065.48,9623.03 ; v2(3091.23,3277.12) 3091.36,3277.26 R157.2@3133.81,3277.26 ; R74.2@3238.72,9447.03 v2(3281.17,9447.03) ; R75.2@3238.72,9510.03 v2(3281.17,9510.03) ; R80.2@3250.6,9567.03 3293.05,9567.03 v2(3293.18,9567.16) ; R81.2@3250.6,9630.03 v2@3293.05,9630.03 ; D5.1@3255.1,9385.08 3275.09,9405.06 v2(3312,9405.06) ; R155.2@3307.06,3101.26 v2(3349.5,3101.26) ; R156.2@3307.06,3164.26 v2(3349.5,3164.26) ; R161.2@3318.93,3221.26 3361.38,3221.26 v2(3361.51,3221.39) ; R162.2@3318.93,3284.26 3361.38,3284.26 v2(3361.51,3284.39) ; v2(3321,4022.37) R550.2@3321,4067.06 ; R550.2@3321.18,4067.06 R550.2@3323.18,4069.06 ; D10.1@3323.43,3039.31 3351.05,3066.93 v2(3369.66,3066.93) ; U58.16@3430.04,4098.58 3430.04,4033.8 C489.2@3430.68,4033.15 3430.68,3988.32 v2(3431,3988) ; v2(3549.2,6906.63) 3549.6,6906.22 R440.1@3595.07,6906.22 ; v2(3550,1005) 3550.07,1004.93 R468.1@3598.4,1004.93 ; v2(3552.53,560.63) 3552.93,560.23 R441.1@3598.4,560.23 ; v2(3553.07,6537.02) 3554.03,6537.97 C449.2@3595.33,6537.97 ; v2(3553.07,6981.73) 3554.03,6982.68 C453.2@3595.33,6982.68 U32.16@3595.33,7048.36 ; v2(3556.4,191.02) 3557.36,191.98 C451.2@3598.66,191.98 ; v2(3556.4,635.73) 3557.36,636.68 C455.2@3598.66,636.68 ; C449.2@3595.08,6537.73 C449.2@3595.33,6537.97 ; U30.16@3595.33,6603.65 C449.2@3595.33,6537.97 ; R467.1@3595.43,7347.75 v2(3642.93,7347.75) ; C451.2@3598.41,191.73 C451.2@3598.66,191.98 ; C455.2@3598.41,636.44 C455.2@3598.66,636.68 ; U31.16@3598.66,257.66 C451.2@3598.66,191.98 ; U33.16@3598.66,702.36 C455.2@3598.66,636.68 ; R406.1@3937.5,9347 v2(3971,9380.5) ; R431.1@3937.5,9443 v2(3991,9443) ; R430.1@3937.5,9543 v2(3997,9543) ; R429.1@3937.5,9643 v2(3997,9643) ; U57.1@3967.01,649.08 v2(3967.06,693.32) v2(3967.06,693.32) ; C148.1@4104.5,9169 4108,9165.5 v2(4108,9125) ; U55.16@4195.96,6995.08 C737.2@4195.96,7057.16 ; C737.2@4196.32,7057.51 v2@4196.32,7104.48 ; U57.16@4199.29,649.08 4199.29,711.16 4199.65,711.52 C741.2@4199.65,718.52 4199.65,758.48 v2(4199.4,758.73) ; R548.2@4313.15,685.6 4313.15,743.48 v2(4313.4,743.73) ; v2(4407,6855) 4407.09,6855.09 R541.2@4407.09,6917 ; v2(4899.87,10213.5) 4959.86,10213.5 C468.2@4962.88,10210.47 ; v2(4910,9001) 4910,9067 C444.2@4911,9068 ; C468.2@4964.79,10208.57 U54.5@5029.75,10208.57 ; v2(4970.91,9309.13) 4971.31,9309.53 R411.1@4971.31,9355 ; v2(5138.21,7402.68) 5137.71,7403.18 C70.1@5092.71,7403.18 5086.83,7397.31 C69.2@5086.83,7346.18 5086.83,7297.06 5106.71,7277.18 U7.8@5163.7,7277.18 ; U27.8@5140.96,9306.77 5140.96,9344.96 v2(5141,9345) ; v2(5221.3,994.75) 5220.8,995.25 C230.1@5175.79,995.25 5169.92,989.38 C229.2@5169.92,938.25 5169.92,889.13 5189.8,869.25 U16.8@5246.78,869.25 ; R49.2@5309.83,7277.18 5345.71,7277.18 v2(5346.21,7276.68) ; R130.2@5392.92,869.25 5428.8,869.25 v2(5429.3,868.75) ; v2(5644,10235) R404.1@5644.01,10276 ; v2(5707,10619.58) 5707.21,10619.79 C441.2@5707.21,10572.95
  L1_Top Layer w40: TP39.1@4801.4,10334.82 v2(4801.4,10437.82)
  L12_Bottom Layer w15: v2(5290.95,9163.46) U29.1@5343.68,9163.43 ; v2(5290.95,9317) U29.7@5343.68,9316.98 U29.8@5343.68,9342.57 ; U29.2@5343.68,9189.02 v2@5396.38,9189.02 ; C511.1@5781.48,3479.41 U64.5@5842.61,3479.41 ; U63.5@5838.18,3745.69 C508.1@5838.18,3796.77
  L12_Bottom Layer w20: v2(2656.9,9568.89) 3089.49,9568.89 3253.31,9405.06 v2(3312,9405.06) ; v2(4116,6414) 4116,6008 4158.5,5965.5 C147.1@4158.5,5931 ; U73.1@4158.74,5850.4 C147.1@4158.74,5930.75 ; v2(5465,9423) 5491.32,9423 R425.1@5513.32,9401 ; U29.16@5575.96,9163.43 5575.96,9105.35 C447.2@5576.31,9105 5613.63,9105 5615.63,9107 v2(5623,9107) ; C511.1@5781.15,3479.74 5781.15,3515.4 v2(5781.21,3515.45) ; v2(5837.9,3832.82) 5837.84,3832.76 C508.1@5837.84,3797.1 C508.1@5838.18,3796.77 ; v2(5955.86,3372.05) 5955.92,3371.99 R632.2@5991.57,3371.99 ; v2(5955.86,3563.04) 5955.92,3562.98 R631.2@5991.57,3562.98 ; v2(5958.86,3635.05) 5958.92,3634.99 R634.2@5994.57,3634.99 ; v2(5958.86,3826.04) 5958.92,3825.98 R635.2@5994.57,3825.98
  other v2: 5439,6765 5487,6765 5535,6765 5583,6765 5439,6813 5487,6813 5535,6813 5583,6813 4196.07,7104.73 5396.4,9189 3293.18,9630.16 5475,10298 4849.4,10437.82 4897.4,10437.82 4801.4,10497.82 4849.4,10497.82 4897.4,10497.82
V_BUS: C471.1 C472.2 C738.2 J71.3 L34.2 R544.2 R545.2 R546.2 U56.8 | length 2363.8
  L1_Top Layer w11: v2(6134.57,9870.57) L34.2@6134.57,9915.69
  L1_Top Layer w20: R545.2@5279.88,9410.97 5279.88,9368.46 v2(5280.87,9367.47) ; R546.2@5421.88,9544.47 v2(5421.87,9582.47) ; C738.2@5491.88,9045.47 U56.8@5491.88,9119.69 ; v2(5492.39,8996.99) 5491.88,8997.49 5491.88,9044.47 C738.2@5492.38,9044.97 ; R544.2@5510.88,9543.47 v2(5510.88,9581.46)
  L10_Signal Layer 2 w20: v2(5492.39,8996.99) 5443.9,9045.47 5296.53,9045.47 5233,9109 5233,9319.6 v2(5280.87,9367.47) 5421.87,9508.47 v2(5421.87,9582.47) 5509.87,9582.47 v2(5510.88,9581.46)
  L12_Bottom Layer w20: v2(5510.88,9581.46) 5665.46,9581.46 5775,9691 5775,9891 J71.3@5829,9945
  L12_Bottom Layer w30: C471.1@6139,9923.91 6139.59,9924.5 C472.2@6242,9924.5
  L12_Bottom Layer w40: J71.3@5829,9945 5962,9812 6076,9812 v2(6134.57,9870.57) 6139,9875 C471.1@6139,9923.91
VA1P1_ADC1: C119.1 C120.1 C121.1 C122.1 C123.1 C124.1 C125.1 C126.1 C127.1 C128.1 C129.1 C130.1 C131.1 C132.1 C133.1 L37.2 TP4.1 U8.C5 U8.D2 U8.D3 U8.D5 U8.E5 U8.F5 U8.G5 U8.H5 U8.J2 U8.J3 U8.J5 U8.K5 | length 61.3
  L12_Bottom Layer w10: C132.1@2338.77,8454.56 2338.77,8410.47 C121.1@2350.92,8398.32
  other v1: 2350.92,8114.86 2256.43,8146.35 2287.93,8146.35 2350.92,8146.35 2350.92,8177.85 2350.92,8209.35 2350.92,8240.84 2350.92,8272.34 2256.43,8303.83 2287.93,8303.83 2350.92,8303.83 2172.81,8304.79 2350.92,8335.33
  other v2: 2192.32,8518.24 2153.06,8518.43 2192.32,8553.24 2153.06,8553.43
VA1P1_ADC2: C279.1 C280.1 C281.1 C282.1 C283.1 C284.1 C285.1 C286.1 C287.1 C288.1 C289.1 C290.1 C291.1 C292.1 C293.1 L38.2 TP10.1 U17.C5 U17.D2 U17.D3 U17.D5 U17.E5 U17.F5 U17.G5 U17.H5 U17.J2 U17.J3 U17.J5 U17.K5 | length 61.3
  L12_Bottom Layer w10: C292.1@2342.1,2108.56 2354.25,2096.41 C281.1@2354.25,2052.33
  other v1: 2354.25,1768.86 2259.76,1800.36 2291.26,1800.36 2354.25,1800.36 2354.25,1831.85 2354.25,1863.35 2354.25,1894.85 2354.25,1926.34 2259.76,1957.84 2291.26,1957.84 2354.25,1957.84 2176.14,1958.8 2354.25,1989.33
  other v2: 2147,2172 2186.26,2171.8 2147,2207 2186.26,2206.8
VA1P9_ADC1: C134.1 C135.1 C136.1 C137.1 C138.1 C139.1 C140.1 C141.1 C142.1 C143.1 C144.1 C145.1 C146.1 L35.2 R54.1 R55.1 R56.1 R57.1 R63.2 R64.2 TP5.1 U8.C4 U8.D4 U8.E2 U8.E3 U8.E4 U8.F4 U8.G4 U8.H2 U8.H3 U8.H4 U8.J4 U8.K4 | length 376.8
  L12_Bottom Layer w15: C145.1@2183.26,7958.56 v1(2183.26,7993.56)
  L12_Bottom Layer w20: R63.2@3103.92,9260.91 R64.2@3193.68,9260.91 ; R57.1@3915.42,8970.99 3967.96,8970.99 v2(3968.08,8970.87) ; R56.1@3915.42,9071.99 3967.96,9071.99 v2(3968.08,9071.87) ; R55.1@3915.42,9171.99 3967.96,9171.99 v2(3968.08,9171.87) ; R54.1@3915.42,9271.99 3967.96,9271.99 3967,9271.03 v2(3967,9231)
  other v1: 2183.26,8029.56 2319.43,8114.86 2319.43,8146.35 2173.81,8177.79 2256.43,8177.85 2287.93,8177.85 2319.43,8177.85 2319.43,8209.35 2319.43,8240.84 2172.81,8267.79 2256.43,8272.34 2287.93,8272.34 2319.43,8272.34 2319.43,8303.83 2319.43,8335.33 2250.26,8435.56 2250.26,8470.56
  other v2: 2235.17,7980.92 2268.27,7981 2235.09,8014.02 2268.19,8014.1 3145.3,9259.91
VA1P9_ADC2: C294.1 C295.1 C296.1 C297.1 C298.1 C299.1 C300.1 C301.1 C302.1 C303.1 C304.1 C305.1 C306.1 L36.2 R135.1 R136.1 R137.1 R138.1 R144.2 R145.2 TP11.1 U17.C4 U17.D4 U17.E2 U17.E3 U17.E4 U17.F4 U17.G4 U17.H2 U17.H3 U17.H4 U17.J4 U17.K4 | length 293
  L12_Bottom Layer w15: C305.1@2176.59,1609.56 v1(2176.59,1644.56)
  L12_Bottom Layer w20: R144.2@3173.61,2905.76 3174.35,2906.49 v2(3216.28,2906.49) R145.2@3256.65,2906.49 ; R138.1@3997.06,2686.1 v2(4040.6,2686.1) v2@4040.48,2686.22 ; R137.1@3997.06,2787.1 v2(4040.6,2787.1) v2@4040.48,2787.22 ; R136.1@3997.06,2887.1 4040.6,2887.1 v2(4040.72,2886.98) ; R135.1@3997.06,2987.1 v2@4040.6,2987.1
  other v1: 2176.59,1680.56 2322.76,1768.86 2322.76,1800.36 2177.14,1831.8 2259.76,1831.85 2291.26,1831.85 2322.76,1831.85 2322.76,1863.35 2322.76,1894.85 2176.14,1921.8 2259.76,1926.34 2291.26,1926.34 2322.76,1926.34 2322.76,1957.84 2322.76,1989.33 2253.59,2089.56 2253.59,2124.56
  other v2: 2229.11,1634.01 2262.21,1634.09 2229.03,1667.11 2262.14,1667.19 4040.72,2986.98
